VERSION 5.7 ;
  NOWIREEXTENSIONATPIN ON ;
  DIVIDERCHAR "/" ;
  BUSBITCHARS "[]" ;
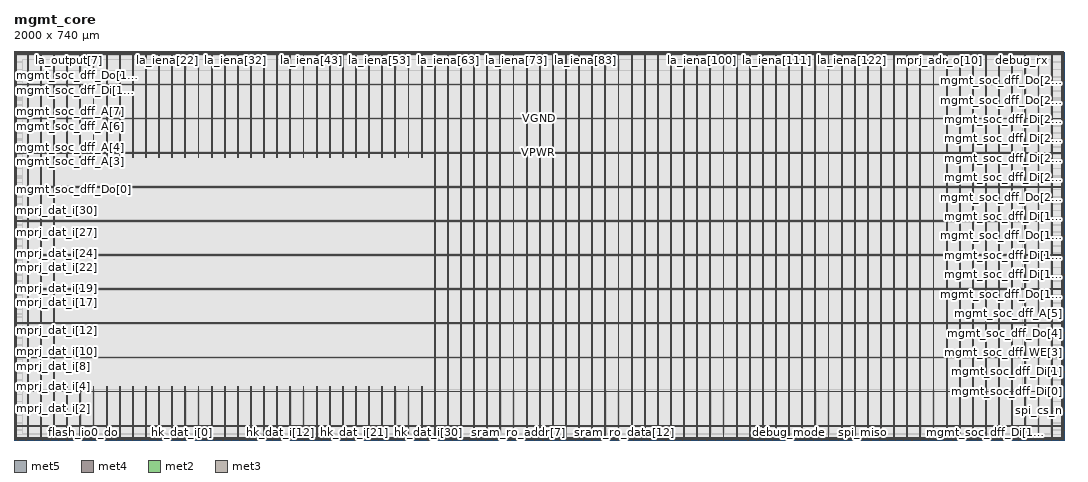
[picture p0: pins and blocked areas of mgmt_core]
MACRO mgmt_core
  CLASS BLOCK ;
  FOREIGN mgmt_core ;
  ORIGIN 0.000 0.000 ;
  SIZE 2000.000 BY 740.000 ;
  PIN VGND
    DIRECTION INPUT ;
    USE GROUND ;
    PORT
      LAYER met5 ;
        RECT 0.020 0.780 1999.600 2.380 ;
    END
    PORT
      LAYER met5 ;
        RECT 0.020 91.490 1999.600 93.090 ;
    END
    PORT
      LAYER met5 ;
        RECT 0.020 221.490 1999.600 223.090 ;
    END
    PORT
      LAYER met5 ;
        RECT 0.020 351.490 1999.600 353.090 ;
    END
    PORT
      LAYER met5 ;
        RECT 0.020 481.490 1999.600 483.090 ;
    END
    PORT
      LAYER met5 ;
        RECT 0.020 611.490 1999.600 613.090 ;
    END
    PORT
      LAYER met5 ;
        RECT 0.020 737.460 1999.600 739.060 ;
    END
    PORT
      LAYER met4 ;
        RECT 100.640 0.780 102.240 101.240 ;
    END
    PORT
      LAYER met4 ;
        RECT 150.640 0.780 152.240 101.240 ;
    END
    PORT
      LAYER met4 ;
        RECT 200.640 0.780 202.240 101.240 ;
    END
    PORT
      LAYER met4 ;
        RECT 250.640 0.780 252.240 101.240 ;
    END
    PORT
      LAYER met4 ;
        RECT 300.640 0.780 302.240 101.240 ;
    END
    PORT
      LAYER met4 ;
        RECT 350.640 0.780 352.240 101.240 ;
    END
    PORT
      LAYER met4 ;
        RECT 400.640 0.780 402.240 101.240 ;
    END
    PORT
      LAYER met4 ;
        RECT 450.640 0.780 452.240 101.240 ;
    END
    PORT
      LAYER met4 ;
        RECT 500.640 0.780 502.240 101.240 ;
    END
    PORT
      LAYER met4 ;
        RECT 550.640 0.780 552.240 101.240 ;
    END
    PORT
      LAYER met4 ;
        RECT 600.640 0.780 602.240 101.240 ;
    END
    PORT
      LAYER met4 ;
        RECT 650.640 0.780 652.240 101.240 ;
    END
    PORT
      LAYER met4 ;
        RECT 700.640 0.780 702.240 101.240 ;
    END
    PORT
      LAYER met4 ;
        RECT 750.640 0.780 752.240 101.240 ;
    END
    PORT
      LAYER met4 ;
        RECT 0.020 0.780 1.620 739.060 ;
    END
    PORT
      LAYER met4 ;
        RECT 50.640 0.780 52.240 739.060 ;
    END
    PORT
      LAYER met4 ;
        RECT 100.640 537.300 102.240 739.060 ;
    END
    PORT
      LAYER met4 ;
        RECT 150.640 537.300 152.240 739.060 ;
    END
    PORT
      LAYER met4 ;
        RECT 200.640 537.300 202.240 739.060 ;
    END
    PORT
      LAYER met4 ;
        RECT 250.640 537.300 252.240 739.060 ;
    END
    PORT
      LAYER met4 ;
        RECT 300.640 537.300 302.240 739.060 ;
    END
    PORT
      LAYER met4 ;
        RECT 350.640 537.300 352.240 739.060 ;
    END
    PORT
      LAYER met4 ;
        RECT 400.640 537.300 402.240 739.060 ;
    END
    PORT
      LAYER met4 ;
        RECT 450.640 537.300 452.240 739.060 ;
    END
    PORT
      LAYER met4 ;
        RECT 500.640 537.300 502.240 739.060 ;
    END
    PORT
      LAYER met4 ;
        RECT 550.640 537.300 552.240 739.060 ;
    END
    PORT
      LAYER met4 ;
        RECT 600.640 537.300 602.240 739.060 ;
    END
    PORT
      LAYER met4 ;
        RECT 650.640 537.300 652.240 739.060 ;
    END
    PORT
      LAYER met4 ;
        RECT 700.640 537.300 702.240 739.060 ;
    END
    PORT
      LAYER met4 ;
        RECT 750.640 537.300 752.240 739.060 ;
    END
    PORT
      LAYER met4 ;
        RECT 800.640 0.780 802.240 739.060 ;
    END
    PORT
      LAYER met4 ;
        RECT 850.640 0.780 852.240 739.060 ;
    END
    PORT
      LAYER met4 ;
        RECT 900.640 0.780 902.240 739.060 ;
    END
    PORT
      LAYER met4 ;
        RECT 950.640 0.780 952.240 739.060 ;
    END
    PORT
      LAYER met4 ;
        RECT 1000.640 0.780 1002.240 739.060 ;
    END
    PORT
      LAYER met4 ;
        RECT 1050.640 0.780 1052.240 739.060 ;
    END
    PORT
      LAYER met4 ;
        RECT 1100.640 0.780 1102.240 739.060 ;
    END
    PORT
      LAYER met4 ;
        RECT 1150.640 0.780 1152.240 739.060 ;
    END
    PORT
      LAYER met4 ;
        RECT 1200.640 0.780 1202.240 739.060 ;
    END
    PORT
      LAYER met4 ;
        RECT 1250.640 0.780 1252.240 739.060 ;
    END
    PORT
      LAYER met4 ;
        RECT 1300.640 0.780 1302.240 739.060 ;
    END
    PORT
      LAYER met4 ;
        RECT 1350.640 0.780 1352.240 739.060 ;
    END
    PORT
      LAYER met4 ;
        RECT 1400.640 0.780 1402.240 739.060 ;
    END
    PORT
      LAYER met4 ;
        RECT 1450.640 0.780 1452.240 739.060 ;
    END
    PORT
      LAYER met4 ;
        RECT 1500.640 0.780 1502.240 739.060 ;
    END
    PORT
      LAYER met4 ;
        RECT 1550.640 0.780 1552.240 739.060 ;
    END
    PORT
      LAYER met4 ;
        RECT 1600.640 0.780 1602.240 739.060 ;
    END
    PORT
      LAYER met4 ;
        RECT 1650.640 0.780 1652.240 739.060 ;
    END
    PORT
      LAYER met4 ;
        RECT 1700.640 0.780 1702.240 739.060 ;
    END
    PORT
      LAYER met4 ;
        RECT 1750.640 0.780 1752.240 739.060 ;
    END
    PORT
      LAYER met4 ;
        RECT 1800.640 0.780 1802.240 739.060 ;
    END
    PORT
      LAYER met4 ;
        RECT 1850.640 0.780 1852.240 739.060 ;
    END
    PORT
      LAYER met4 ;
        RECT 1900.640 0.780 1902.240 739.060 ;
    END
    PORT
      LAYER met4 ;
        RECT 1950.640 0.780 1952.240 739.060 ;
    END
    PORT
      LAYER met4 ;
        RECT 1998.000 0.780 1999.600 739.060 ;
    END
  END VGND
  PIN VPWR
    DIRECTION INPUT ;
    USE POWER ;
    PORT
      LAYER met5 ;
        RECT 3.320 4.080 1996.300 5.680 ;
    END
    PORT
      LAYER met5 ;
        RECT 0.020 26.490 1999.600 28.090 ;
    END
    PORT
      LAYER met5 ;
        RECT 0.020 156.490 1999.600 158.090 ;
    END
    PORT
      LAYER met5 ;
        RECT 0.020 286.490 1999.600 288.090 ;
    END
    PORT
      LAYER met5 ;
        RECT 0.020 416.490 1999.600 418.090 ;
    END
    PORT
      LAYER met5 ;
        RECT 0.020 546.490 1999.600 548.090 ;
    END
    PORT
      LAYER met5 ;
        RECT 0.020 676.490 1999.600 678.090 ;
    END
    PORT
      LAYER met5 ;
        RECT 3.320 734.160 1996.300 735.760 ;
    END
    PORT
      LAYER met4 ;
        RECT 125.640 0.780 127.240 101.240 ;
    END
    PORT
      LAYER met4 ;
        RECT 175.640 0.780 177.240 101.240 ;
    END
    PORT
      LAYER met4 ;
        RECT 225.640 0.780 227.240 101.240 ;
    END
    PORT
      LAYER met4 ;
        RECT 275.640 0.780 277.240 101.240 ;
    END
    PORT
      LAYER met4 ;
        RECT 325.640 0.780 327.240 101.240 ;
    END
    PORT
      LAYER met4 ;
        RECT 375.640 0.780 377.240 101.240 ;
    END
    PORT
      LAYER met4 ;
        RECT 425.640 0.780 427.240 101.240 ;
    END
    PORT
      LAYER met4 ;
        RECT 475.640 0.780 477.240 101.240 ;
    END
    PORT
      LAYER met4 ;
        RECT 525.640 0.780 527.240 101.240 ;
    END
    PORT
      LAYER met4 ;
        RECT 575.640 0.780 577.240 101.240 ;
    END
    PORT
      LAYER met4 ;
        RECT 625.640 0.780 627.240 101.240 ;
    END
    PORT
      LAYER met4 ;
        RECT 675.640 0.780 677.240 101.240 ;
    END
    PORT
      LAYER met4 ;
        RECT 725.640 0.780 727.240 101.240 ;
    END
    PORT
      LAYER met4 ;
        RECT 775.640 0.780 777.240 101.240 ;
    END
    PORT
      LAYER met4 ;
        RECT 3.320 4.080 4.920 735.760 ;
    END
    PORT
      LAYER met4 ;
        RECT 1994.700 4.080 1996.300 735.760 ;
    END
    PORT
      LAYER met4 ;
        RECT 25.640 0.780 27.240 739.060 ;
    END
    PORT
      LAYER met4 ;
        RECT 75.640 0.780 77.240 739.060 ;
    END
    PORT
      LAYER met4 ;
        RECT 125.640 537.300 127.240 739.060 ;
    END
    PORT
      LAYER met4 ;
        RECT 175.640 537.300 177.240 739.060 ;
    END
    PORT
      LAYER met4 ;
        RECT 225.640 537.300 227.240 739.060 ;
    END
    PORT
      LAYER met4 ;
        RECT 275.640 537.300 277.240 739.060 ;
    END
    PORT
      LAYER met4 ;
        RECT 325.640 537.300 327.240 739.060 ;
    END
    PORT
      LAYER met4 ;
        RECT 375.640 537.300 377.240 739.060 ;
    END
    PORT
      LAYER met4 ;
        RECT 425.640 537.300 427.240 739.060 ;
    END
    PORT
      LAYER met4 ;
        RECT 475.640 537.300 477.240 739.060 ;
    END
    PORT
      LAYER met4 ;
        RECT 525.640 537.300 527.240 739.060 ;
    END
    PORT
      LAYER met4 ;
        RECT 575.640 537.300 577.240 739.060 ;
    END
    PORT
      LAYER met4 ;
        RECT 625.640 537.300 627.240 739.060 ;
    END
    PORT
      LAYER met4 ;
        RECT 675.640 537.300 677.240 739.060 ;
    END
    PORT
      LAYER met4 ;
        RECT 725.640 537.300 727.240 739.060 ;
    END
    PORT
      LAYER met4 ;
        RECT 775.640 537.300 777.240 739.060 ;
    END
    PORT
      LAYER met4 ;
        RECT 825.640 0.780 827.240 739.060 ;
    END
    PORT
      LAYER met4 ;
        RECT 875.640 0.780 877.240 739.060 ;
    END
    PORT
      LAYER met4 ;
        RECT 925.640 0.780 927.240 739.060 ;
    END
    PORT
      LAYER met4 ;
        RECT 975.640 0.780 977.240 739.060 ;
    END
    PORT
      LAYER met4 ;
        RECT 1025.640 0.780 1027.240 739.060 ;
    END
    PORT
      LAYER met4 ;
        RECT 1075.640 0.780 1077.240 739.060 ;
    END
    PORT
      LAYER met4 ;
        RECT 1125.640 0.780 1127.240 739.060 ;
    END
    PORT
      LAYER met4 ;
        RECT 1175.640 0.780 1177.240 739.060 ;
    END
    PORT
      LAYER met4 ;
        RECT 1225.640 0.780 1227.240 739.060 ;
    END
    PORT
      LAYER met4 ;
        RECT 1275.640 0.780 1277.240 739.060 ;
    END
    PORT
      LAYER met4 ;
        RECT 1325.640 0.780 1327.240 739.060 ;
    END
    PORT
      LAYER met4 ;
        RECT 1375.640 0.780 1377.240 739.060 ;
    END
    PORT
      LAYER met4 ;
        RECT 1425.640 0.780 1427.240 739.060 ;
    END
    PORT
      LAYER met4 ;
        RECT 1475.640 0.780 1477.240 739.060 ;
    END
    PORT
      LAYER met4 ;
        RECT 1525.640 0.780 1527.240 739.060 ;
    END
    PORT
      LAYER met4 ;
        RECT 1575.640 0.780 1577.240 739.060 ;
    END
    PORT
      LAYER met4 ;
        RECT 1625.640 0.780 1627.240 739.060 ;
    END
    PORT
      LAYER met4 ;
        RECT 1675.640 0.780 1677.240 739.060 ;
    END
    PORT
      LAYER met4 ;
        RECT 1725.640 0.780 1727.240 739.060 ;
    END
    PORT
      LAYER met4 ;
        RECT 1775.640 0.780 1777.240 739.060 ;
    END
    PORT
      LAYER met4 ;
        RECT 1825.640 0.780 1827.240 739.060 ;
    END
    PORT
      LAYER met4 ;
        RECT 1875.640 0.780 1877.240 739.060 ;
    END
    PORT
      LAYER met4 ;
        RECT 1925.640 0.780 1927.240 739.060 ;
    END
    PORT
      LAYER met4 ;
        RECT 1975.640 0.780 1977.240 739.060 ;
    END
  END VPWR
  PIN core_clk
    DIRECTION INPUT ;
    USE SIGNAL ;
    PORT
      LAYER met2 ;
        RECT 1.470 736.000 1.750 740.000 ;
    END
  END core_clk
  PIN core_rst
    DIRECTION INPUT ;
    USE SIGNAL ;
    PORT
      LAYER met2 ;
        RECT 1569.610 0.000 1569.890 4.000 ;
    END
  END core_rst
  PIN debug_mode
    DIRECTION OUTPUT TRISTATE ;
    USE SIGNAL ;
    PORT
      LAYER met2 ;
        RECT 1476.230 0.000 1476.510 4.000 ;
    END
  END debug_mode
  PIN debug_oeb
    DIRECTION OUTPUT TRISTATE ;
    USE SIGNAL ;
    PORT
      LAYER met2 ;
        RECT 1491.870 0.000 1492.150 4.000 ;
    END
  END debug_oeb
  PIN debug_rx
    DIRECTION INPUT ;
    USE SIGNAL ;
    PORT
      LAYER met2 ;
        RECT 1919.670 736.000 1919.950 740.000 ;
    END
  END debug_rx
  PIN debug_tx
    DIRECTION OUTPUT TRISTATE ;
    USE SIGNAL ;
    PORT
      LAYER met2 ;
        RECT 1585.250 0.000 1585.530 4.000 ;
    END
  END debug_tx
  PIN flash_clk
    DIRECTION OUTPUT TRISTATE ;
    USE SIGNAL ;
    PORT
      LAYER met2 ;
        RECT 100.830 0.000 101.110 4.000 ;
    END
  END flash_clk
  PIN flash_cs_n
    DIRECTION OUTPUT TRISTATE ;
    USE SIGNAL ;
    PORT
      LAYER met2 ;
        RECT 1600.890 0.000 1601.170 4.000 ;
    END
  END flash_cs_n
  PIN flash_io0_di
    DIRECTION INPUT ;
    USE SIGNAL ;
    PORT
      LAYER met2 ;
        RECT 116.470 0.000 116.750 4.000 ;
    END
  END flash_io0_di
  PIN flash_io0_do
    DIRECTION OUTPUT TRISTATE ;
    USE SIGNAL ;
    PORT
      LAYER met2 ;
        RECT 132.110 0.000 132.390 4.000 ;
    END
  END flash_io0_do
  PIN flash_io0_oeb
    DIRECTION OUTPUT TRISTATE ;
    USE SIGNAL ;
    PORT
      LAYER met2 ;
        RECT 147.750 0.000 148.030 4.000 ;
    END
  END flash_io0_oeb
  PIN flash_io1_di
    DIRECTION INPUT ;
    USE SIGNAL ;
    PORT
      LAYER met2 ;
        RECT 163.390 0.000 163.670 4.000 ;
    END
  END flash_io1_di
  PIN flash_io1_do
    DIRECTION INPUT ;
    USE SIGNAL ;
    PORT
      LAYER met2 ;
        RECT 179.030 0.000 179.310 4.000 ;
    END
  END flash_io1_do
  PIN flash_io1_oeb
    DIRECTION INPUT ;
    USE SIGNAL ;
    PORT
      LAYER met2 ;
        RECT 194.670 0.000 194.950 4.000 ;
    END
  END flash_io1_oeb
  PIN flash_io2_di
    DIRECTION INPUT ;
    USE SIGNAL ;
    PORT
      LAYER met2 ;
        RECT 210.310 0.000 210.590 4.000 ;
    END
  END flash_io2_di
  PIN flash_io2_do
    DIRECTION INPUT ;
    USE SIGNAL ;
    PORT
      LAYER met2 ;
        RECT 225.950 0.000 226.230 4.000 ;
    END
  END flash_io2_do
  PIN flash_io2_oeb
    DIRECTION INPUT ;
    USE SIGNAL ;
    PORT
      LAYER met3 ;
        RECT 0.000 19.080 4.000 19.680 ;
    END
  END flash_io2_oeb
  PIN flash_io3_di
    DIRECTION INPUT ;
    USE SIGNAL ;
    PORT
      LAYER met2 ;
        RECT 241.590 0.000 241.870 4.000 ;
    END
  END flash_io3_di
  PIN flash_io3_do
    DIRECTION INPUT ;
    USE SIGNAL ;
    PORT
      LAYER met2 ;
        RECT 257.230 0.000 257.510 4.000 ;
    END
  END flash_io3_do
  PIN flash_io3_oeb
    DIRECTION INPUT ;
    USE SIGNAL ;
    PORT
      LAYER met3 ;
        RECT 0.000 6.160 4.000 6.760 ;
    END
  END flash_io3_oeb
  PIN gpio_in_pad
    DIRECTION INPUT ;
    USE SIGNAL ;
    PORT
      LAYER met2 ;
        RECT 7.450 0.000 7.730 4.000 ;
    END
  END gpio_in_pad
  PIN gpio_inenb_pad
    DIRECTION OUTPUT TRISTATE ;
    USE SIGNAL ;
    PORT
      LAYER met2 ;
        RECT 22.630 0.000 22.910 4.000 ;
    END
  END gpio_inenb_pad
  PIN gpio_mode0_pad
    DIRECTION OUTPUT TRISTATE ;
    USE SIGNAL ;
    PORT
      LAYER met2 ;
        RECT 38.270 0.000 38.550 4.000 ;
    END
  END gpio_mode0_pad
  PIN gpio_mode1_pad
    DIRECTION OUTPUT TRISTATE ;
    USE SIGNAL ;
    PORT
      LAYER met2 ;
        RECT 53.910 0.000 54.190 4.000 ;
    END
  END gpio_mode1_pad
  PIN gpio_out_pad
    DIRECTION OUTPUT TRISTATE ;
    USE SIGNAL ;
    PORT
      LAYER met2 ;
        RECT 69.550 0.000 69.830 4.000 ;
    END
  END gpio_out_pad
  PIN gpio_outenb_pad
    DIRECTION OUTPUT TRISTATE ;
    USE SIGNAL ;
    PORT
      LAYER met2 ;
        RECT 85.190 0.000 85.470 4.000 ;
    END
  END gpio_outenb_pad
  PIN hk_ack_i
    DIRECTION INPUT ;
    USE SIGNAL ;
    PORT
      LAYER met2 ;
        RECT 288.510 0.000 288.790 4.000 ;
    END
  END hk_ack_i
  PIN hk_dat_i[0]
    DIRECTION INPUT ;
    USE SIGNAL ;
    PORT
      LAYER met2 ;
        RECT 319.790 0.000 320.070 4.000 ;
    END
  END hk_dat_i[0]
  PIN hk_dat_i[10]
    DIRECTION INPUT ;
    USE SIGNAL ;
    PORT
      LAYER met2 ;
        RECT 476.190 0.000 476.470 4.000 ;
    END
  END hk_dat_i[10]
  PIN hk_dat_i[11]
    DIRECTION INPUT ;
    USE SIGNAL ;
    PORT
      LAYER met2 ;
        RECT 491.830 0.000 492.110 4.000 ;
    END
  END hk_dat_i[11]
  PIN hk_dat_i[12]
    DIRECTION INPUT ;
    USE SIGNAL ;
    PORT
      LAYER met2 ;
        RECT 507.470 0.000 507.750 4.000 ;
    END
  END hk_dat_i[12]
  PIN hk_dat_i[13]
    DIRECTION INPUT ;
    USE SIGNAL ;
    PORT
      LAYER met2 ;
        RECT 522.650 0.000 522.930 4.000 ;
    END
  END hk_dat_i[13]
  PIN hk_dat_i[14]
    DIRECTION INPUT ;
    USE SIGNAL ;
    PORT
      LAYER met2 ;
        RECT 538.290 0.000 538.570 4.000 ;
    END
  END hk_dat_i[14]
  PIN hk_dat_i[15]
    DIRECTION INPUT ;
    USE SIGNAL ;
    PORT
      LAYER met2 ;
        RECT 553.930 0.000 554.210 4.000 ;
    END
  END hk_dat_i[15]
  PIN hk_dat_i[16]
    DIRECTION INPUT ;
    USE SIGNAL ;
    PORT
      LAYER met2 ;
        RECT 569.570 0.000 569.850 4.000 ;
    END
  END hk_dat_i[16]
  PIN hk_dat_i[17]
    DIRECTION INPUT ;
    USE SIGNAL ;
    PORT
      LAYER met2 ;
        RECT 585.210 0.000 585.490 4.000 ;
    END
  END hk_dat_i[17]
  PIN hk_dat_i[18]
    DIRECTION INPUT ;
    USE SIGNAL ;
    PORT
      LAYER met2 ;
        RECT 600.850 0.000 601.130 4.000 ;
    END
  END hk_dat_i[18]
  PIN hk_dat_i[19]
    DIRECTION INPUT ;
    USE SIGNAL ;
    PORT
      LAYER met2 ;
        RECT 616.490 0.000 616.770 4.000 ;
    END
  END hk_dat_i[19]
  PIN hk_dat_i[1]
    DIRECTION INPUT ;
    USE SIGNAL ;
    PORT
      LAYER met2 ;
        RECT 335.430 0.000 335.710 4.000 ;
    END
  END hk_dat_i[1]
  PIN hk_dat_i[20]
    DIRECTION INPUT ;
    USE SIGNAL ;
    PORT
      LAYER met2 ;
        RECT 632.130 0.000 632.410 4.000 ;
    END
  END hk_dat_i[20]
  PIN hk_dat_i[21]
    DIRECTION INPUT ;
    USE SIGNAL ;
    PORT
      LAYER met2 ;
        RECT 647.770 0.000 648.050 4.000 ;
    END
  END hk_dat_i[21]
  PIN hk_dat_i[22]
    DIRECTION INPUT ;
    USE SIGNAL ;
    PORT
      LAYER met2 ;
        RECT 663.410 0.000 663.690 4.000 ;
    END
  END hk_dat_i[22]
  PIN hk_dat_i[23]
    DIRECTION INPUT ;
    USE SIGNAL ;
    PORT
      LAYER met2 ;
        RECT 679.050 0.000 679.330 4.000 ;
    END
  END hk_dat_i[23]
  PIN hk_dat_i[24]
    DIRECTION INPUT ;
    USE SIGNAL ;
    PORT
      LAYER met2 ;
        RECT 694.690 0.000 694.970 4.000 ;
    END
  END hk_dat_i[24]
  PIN hk_dat_i[25]
    DIRECTION INPUT ;
    USE SIGNAL ;
    PORT
      LAYER met2 ;
        RECT 710.330 0.000 710.610 4.000 ;
    END
  END hk_dat_i[25]
  PIN hk_dat_i[26]
    DIRECTION INPUT ;
    USE SIGNAL ;
    PORT
      LAYER met2 ;
        RECT 725.970 0.000 726.250 4.000 ;
    END
  END hk_dat_i[26]
  PIN hk_dat_i[27]
    DIRECTION INPUT ;
    USE SIGNAL ;
    PORT
      LAYER met2 ;
        RECT 741.610 0.000 741.890 4.000 ;
    END
  END hk_dat_i[27]
  PIN hk_dat_i[28]
    DIRECTION INPUT ;
    USE SIGNAL ;
    PORT
      LAYER met2 ;
        RECT 757.250 0.000 757.530 4.000 ;
    END
  END hk_dat_i[28]
  PIN hk_dat_i[29]
    DIRECTION INPUT ;
    USE SIGNAL ;
    PORT
      LAYER met2 ;
        RECT 772.890 0.000 773.170 4.000 ;
    END
  END hk_dat_i[29]
  PIN hk_dat_i[2]
    DIRECTION INPUT ;
    USE SIGNAL ;
    PORT
      LAYER met2 ;
        RECT 351.070 0.000 351.350 4.000 ;
    END
  END hk_dat_i[2]
  PIN hk_dat_i[30]
    DIRECTION INPUT ;
    USE SIGNAL ;
    PORT
      LAYER met2 ;
        RECT 788.530 0.000 788.810 4.000 ;
    END
  END hk_dat_i[30]
  PIN hk_dat_i[31]
    DIRECTION INPUT ;
    USE SIGNAL ;
    PORT
      LAYER met2 ;
        RECT 804.170 0.000 804.450 4.000 ;
    END
  END hk_dat_i[31]
  PIN hk_dat_i[3]
    DIRECTION INPUT ;
    USE SIGNAL ;
    PORT
      LAYER met2 ;
        RECT 366.710 0.000 366.990 4.000 ;
    END
  END hk_dat_i[3]
  PIN hk_dat_i[4]
    DIRECTION INPUT ;
    USE SIGNAL ;
    PORT
      LAYER met2 ;
        RECT 382.350 0.000 382.630 4.000 ;
    END
  END hk_dat_i[4]
  PIN hk_dat_i[5]
    DIRECTION INPUT ;
    USE SIGNAL ;
    PORT
      LAYER met2 ;
        RECT 397.990 0.000 398.270 4.000 ;
    END
  END hk_dat_i[5]
  PIN hk_dat_i[6]
    DIRECTION INPUT ;
    USE SIGNAL ;
    PORT
      LAYER met2 ;
        RECT 413.630 0.000 413.910 4.000 ;
    END
  END hk_dat_i[6]
  PIN hk_dat_i[7]
    DIRECTION INPUT ;
    USE SIGNAL ;
    PORT
      LAYER met2 ;
        RECT 429.270 0.000 429.550 4.000 ;
    END
  END hk_dat_i[7]
  PIN hk_dat_i[8]
    DIRECTION INPUT ;
    USE SIGNAL ;
    PORT
      LAYER met2 ;
        RECT 444.910 0.000 445.190 4.000 ;
    END
  END hk_dat_i[8]
  PIN hk_dat_i[9]
    DIRECTION INPUT ;
    USE SIGNAL ;
    PORT
      LAYER met2 ;
        RECT 460.550 0.000 460.830 4.000 ;
    END
  END hk_dat_i[9]
  PIN hk_stb_o
    DIRECTION OUTPUT TRISTATE ;
    USE SIGNAL ;
    PORT
      LAYER met2 ;
        RECT 304.150 0.000 304.430 4.000 ;
    END
  END hk_stb_o
  PIN la_iena[0]
    DIRECTION OUTPUT TRISTATE ;
    USE SIGNAL ;
    PORT
      LAYER met2 ;
        RECT 4.690 736.000 4.970 740.000 ;
    END
  END la_iena[0]
  PIN la_iena[100]
    DIRECTION OUTPUT TRISTATE ;
    USE SIGNAL ;
    PORT
      LAYER met2 ;
        RECT 1309.710 736.000 1309.990 740.000 ;
    END
  END la_iena[100]
  PIN la_iena[101]
    DIRECTION OUTPUT TRISTATE ;
    USE SIGNAL ;
    PORT
      LAYER met2 ;
        RECT 1322.590 736.000 1322.870 740.000 ;
    END
  END la_iena[101]
  PIN la_iena[102]
    DIRECTION OUTPUT TRISTATE ;
    USE SIGNAL ;
    PORT
      LAYER met2 ;
        RECT 1335.930 736.000 1336.210 740.000 ;
    END
  END la_iena[102]
  PIN la_iena[103]
    DIRECTION OUTPUT TRISTATE ;
    USE SIGNAL ;
    PORT
      LAYER met2 ;
        RECT 1348.810 736.000 1349.090 740.000 ;
    END
  END la_iena[103]
  PIN la_iena[104]
    DIRECTION OUTPUT TRISTATE ;
    USE SIGNAL ;
    PORT
      LAYER met2 ;
        RECT 1361.690 736.000 1361.970 740.000 ;
    END
  END la_iena[104]
  PIN la_iena[105]
    DIRECTION OUTPUT TRISTATE ;
    USE SIGNAL ;
    PORT
      LAYER met2 ;
        RECT 1375.030 736.000 1375.310 740.000 ;
    END
  END la_iena[105]
  PIN la_iena[106]
    DIRECTION OUTPUT TRISTATE ;
    USE SIGNAL ;
    PORT
      LAYER met2 ;
        RECT 1387.910 736.000 1388.190 740.000 ;
    END
  END la_iena[106]
  PIN la_iena[107]
    DIRECTION OUTPUT TRISTATE ;
    USE SIGNAL ;
    PORT
      LAYER met2 ;
        RECT 1400.790 736.000 1401.070 740.000 ;
    END
  END la_iena[107]
  PIN la_iena[108]
    DIRECTION OUTPUT TRISTATE ;
    USE SIGNAL ;
    PORT
      LAYER met2 ;
        RECT 1414.130 736.000 1414.410 740.000 ;
    END
  END la_iena[108]
  PIN la_iena[109]
    DIRECTION OUTPUT TRISTATE ;
    USE SIGNAL ;
    PORT
      LAYER met2 ;
        RECT 1427.010 736.000 1427.290 740.000 ;
    END
  END la_iena[109]
  PIN la_iena[10]
    DIRECTION OUTPUT TRISTATE ;
    USE SIGNAL ;
    PORT
      LAYER met2 ;
        RECT 134.870 736.000 135.150 740.000 ;
    END
  END la_iena[10]
  PIN la_iena[110]
    DIRECTION OUTPUT TRISTATE ;
    USE SIGNAL ;
    PORT
      LAYER met2 ;
        RECT 1440.350 736.000 1440.630 740.000 ;
    END
  END la_iena[110]
  PIN la_iena[111]
    DIRECTION OUTPUT TRISTATE ;
    USE SIGNAL ;
    PORT
      LAYER met2 ;
        RECT 1453.230 736.000 1453.510 740.000 ;
    END
  END la_iena[111]
  PIN la_iena[112]
    DIRECTION OUTPUT TRISTATE ;
    USE SIGNAL ;
    PORT
      LAYER met2 ;
        RECT 1466.110 736.000 1466.390 740.000 ;
    END
  END la_iena[112]
  PIN la_iena[113]
    DIRECTION OUTPUT TRISTATE ;
    USE SIGNAL ;
    PORT
      LAYER met2 ;
        RECT 1479.450 736.000 1479.730 740.000 ;
    END
  END la_iena[113]
  PIN la_iena[114]
    DIRECTION OUTPUT TRISTATE ;
    USE SIGNAL ;
    PORT
      LAYER met2 ;
        RECT 1492.330 736.000 1492.610 740.000 ;
    END
  END la_iena[114]
  PIN la_iena[115]
    DIRECTION OUTPUT TRISTATE ;
    USE SIGNAL ;
    PORT
      LAYER met2 ;
        RECT 1505.210 736.000 1505.490 740.000 ;
    END
  END la_iena[115]
  PIN la_iena[116]
    DIRECTION OUTPUT TRISTATE ;
    USE SIGNAL ;
    PORT
      LAYER met2 ;
        RECT 1518.550 736.000 1518.830 740.000 ;
    END
  END la_iena[116]
  PIN la_iena[117]
    DIRECTION OUTPUT TRISTATE ;
    USE SIGNAL ;
    PORT
      LAYER met2 ;
        RECT 1531.430 736.000 1531.710 740.000 ;
    END
  END la_iena[117]
  PIN la_iena[118]
    DIRECTION OUTPUT TRISTATE ;
    USE SIGNAL ;
    PORT
      LAYER met2 ;
        RECT 1544.310 736.000 1544.590 740.000 ;
    END
  END la_iena[118]
  PIN la_iena[119]
    DIRECTION OUTPUT TRISTATE ;
    USE SIGNAL ;
    PORT
      LAYER met2 ;
        RECT 1557.650 736.000 1557.930 740.000 ;
    END
  END la_iena[119]
  PIN la_iena[11]
    DIRECTION OUTPUT TRISTATE ;
    USE SIGNAL ;
    PORT
      LAYER met2 ;
        RECT 148.210 736.000 148.490 740.000 ;
    END
  END la_iena[11]
  PIN la_iena[120]
    DIRECTION OUTPUT TRISTATE ;
    USE SIGNAL ;
    PORT
      LAYER met2 ;
        RECT 1570.530 736.000 1570.810 740.000 ;
    END
  END la_iena[120]
  PIN la_iena[121]
    DIRECTION OUTPUT TRISTATE ;
    USE SIGNAL ;
    PORT
      LAYER met2 ;
        RECT 1583.870 736.000 1584.150 740.000 ;
    END
  END la_iena[121]
  PIN la_iena[122]
    DIRECTION OUTPUT TRISTATE ;
    USE SIGNAL ;
    PORT
      LAYER met2 ;
        RECT 1596.750 736.000 1597.030 740.000 ;
    END
  END la_iena[122]
  PIN la_iena[123]
    DIRECTION OUTPUT TRISTATE ;
    USE SIGNAL ;
    PORT
      LAYER met2 ;
        RECT 1609.630 736.000 1609.910 740.000 ;
    END
  END la_iena[123]
  PIN la_iena[124]
    DIRECTION OUTPUT TRISTATE ;
    USE SIGNAL ;
    PORT
      LAYER met2 ;
        RECT 1622.970 736.000 1623.250 740.000 ;
    END
  END la_iena[124]
  PIN la_iena[125]
    DIRECTION OUTPUT TRISTATE ;
    USE SIGNAL ;
    PORT
      LAYER met2 ;
        RECT 1635.850 736.000 1636.130 740.000 ;
    END
  END la_iena[125]
  PIN la_iena[126]
    DIRECTION OUTPUT TRISTATE ;
    USE SIGNAL ;
    PORT
      LAYER met2 ;
        RECT 1648.730 736.000 1649.010 740.000 ;
    END
  END la_iena[126]
  PIN la_iena[127]
    DIRECTION OUTPUT TRISTATE ;
    USE SIGNAL ;
    PORT
      LAYER met2 ;
        RECT 1662.070 736.000 1662.350 740.000 ;
    END
  END la_iena[127]
  PIN la_iena[12]
    DIRECTION OUTPUT TRISTATE ;
    USE SIGNAL ;
    PORT
      LAYER met2 ;
        RECT 161.090 736.000 161.370 740.000 ;
    END
  END la_iena[12]
  PIN la_iena[13]
    DIRECTION OUTPUT TRISTATE ;
    USE SIGNAL ;
    PORT
      LAYER met2 ;
        RECT 173.970 736.000 174.250 740.000 ;
    END
  END la_iena[13]
  PIN la_iena[14]
    DIRECTION OUTPUT TRISTATE ;
    USE SIGNAL ;
    PORT
      LAYER met2 ;
        RECT 187.310 736.000 187.590 740.000 ;
    END
  END la_iena[14]
  PIN la_iena[15]
    DIRECTION OUTPUT TRISTATE ;
    USE SIGNAL ;
    PORT
      LAYER met2 ;
        RECT 200.190 736.000 200.470 740.000 ;
    END
  END la_iena[15]
  PIN la_iena[16]
    DIRECTION OUTPUT TRISTATE ;
    USE SIGNAL ;
    PORT
      LAYER met2 ;
        RECT 213.530 736.000 213.810 740.000 ;
    END
  END la_iena[16]
  PIN la_iena[17]
    DIRECTION OUTPUT TRISTATE ;
    USE SIGNAL ;
    PORT
      LAYER met2 ;
        RECT 226.410 736.000 226.690 740.000 ;
    END
  END la_iena[17]
  PIN la_iena[18]
    DIRECTION OUTPUT TRISTATE ;
    USE SIGNAL ;
    PORT
      LAYER met2 ;
        RECT 239.290 736.000 239.570 740.000 ;
    END
  END la_iena[18]
  PIN la_iena[19]
    DIRECTION OUTPUT TRISTATE ;
    USE SIGNAL ;
    PORT
      LAYER met2 ;
        RECT 252.630 736.000 252.910 740.000 ;
    END
  END la_iena[19]
  PIN la_iena[1]
    DIRECTION OUTPUT TRISTATE ;
    USE SIGNAL ;
    PORT
      LAYER met2 ;
        RECT 17.570 736.000 17.850 740.000 ;
    END
  END la_iena[1]
  PIN la_iena[20]
    DIRECTION OUTPUT TRISTATE ;
    USE SIGNAL ;
    PORT
      LAYER met2 ;
        RECT 265.510 736.000 265.790 740.000 ;
    END
  END la_iena[20]
  PIN la_iena[21]
    DIRECTION OUTPUT TRISTATE ;
    USE SIGNAL ;
    PORT
      LAYER met2 ;
        RECT 278.390 736.000 278.670 740.000 ;
    END
  END la_iena[21]
  PIN la_iena[22]
    DIRECTION OUTPUT TRISTATE ;
    USE SIGNAL ;
    PORT
      LAYER met2 ;
        RECT 291.730 736.000 292.010 740.000 ;
    END
  END la_iena[22]
  PIN la_iena[23]
    DIRECTION OUTPUT TRISTATE ;
    USE SIGNAL ;
    PORT
      LAYER met2 ;
        RECT 304.610 736.000 304.890 740.000 ;
    END
  END la_iena[23]
  PIN la_iena[24]
    DIRECTION OUTPUT TRISTATE ;
    USE SIGNAL ;
    PORT
      LAYER met2 ;
        RECT 317.950 736.000 318.230 740.000 ;
    END
  END la_iena[24]
  PIN la_iena[25]
    DIRECTION OUTPUT TRISTATE ;
    USE SIGNAL ;
    PORT
      LAYER met2 ;
        RECT 330.830 736.000 331.110 740.000 ;
    END
  END la_iena[25]
  PIN la_iena[26]
    DIRECTION OUTPUT TRISTATE ;
    USE SIGNAL ;
    PORT
      LAYER met2 ;
        RECT 343.710 736.000 343.990 740.000 ;
    END
  END la_iena[26]
  PIN la_iena[27]
    DIRECTION OUTPUT TRISTATE ;
    USE SIGNAL ;
    PORT
      LAYER met2 ;
        RECT 357.050 736.000 357.330 740.000 ;
    END
  END la_iena[27]
  PIN la_iena[28]
    DIRECTION OUTPUT TRISTATE ;
    USE SIGNAL ;
    PORT
      LAYER met2 ;
        RECT 369.930 736.000 370.210 740.000 ;
    END
  END la_iena[28]
  PIN la_iena[29]
    DIRECTION OUTPUT TRISTATE ;
    USE SIGNAL ;
    PORT
      LAYER met2 ;
        RECT 382.810 736.000 383.090 740.000 ;
    END
  END la_iena[29]
  PIN la_iena[2]
    DIRECTION OUTPUT TRISTATE ;
    USE SIGNAL ;
    PORT
      LAYER met2 ;
        RECT 30.450 736.000 30.730 740.000 ;
    END
  END la_iena[2]
  PIN la_iena[30]
    DIRECTION OUTPUT TRISTATE ;
    USE SIGNAL ;
    PORT
      LAYER met2 ;
        RECT 396.150 736.000 396.430 740.000 ;
    END
  END la_iena[30]
  PIN la_iena[31]
    DIRECTION OUTPUT TRISTATE ;
    USE SIGNAL ;
    PORT
      LAYER met2 ;
        RECT 409.030 736.000 409.310 740.000 ;
    END
  END la_iena[31]
  PIN la_iena[32]
    DIRECTION OUTPUT TRISTATE ;
    USE SIGNAL ;
    PORT
      LAYER met2 ;
        RECT 421.910 736.000 422.190 740.000 ;
    END
  END la_iena[32]
  PIN la_iena[33]
    DIRECTION OUTPUT TRISTATE ;
    USE SIGNAL ;
    PORT
      LAYER met2 ;
        RECT 435.250 736.000 435.530 740.000 ;
    END
  END la_iena[33]
  PIN la_iena[34]
    DIRECTION OUTPUT TRISTATE ;
    USE SIGNAL ;
    PORT
      LAYER met2 ;
        RECT 448.130 736.000 448.410 740.000 ;
    END
  END la_iena[34]
  PIN la_iena[35]
    DIRECTION OUTPUT TRISTATE ;
    USE SIGNAL ;
    PORT
      LAYER met2 ;
        RECT 461.470 736.000 461.750 740.000 ;
    END
  END la_iena[35]
  PIN la_iena[36]
    DIRECTION OUTPUT TRISTATE ;
    USE SIGNAL ;
    PORT
      LAYER met2 ;
        RECT 474.350 736.000 474.630 740.000 ;
    END
  END la_iena[36]
  PIN la_iena[37]
    DIRECTION OUTPUT TRISTATE ;
    USE SIGNAL ;
    PORT
      LAYER met2 ;
        RECT 487.230 736.000 487.510 740.000 ;
    END
  END la_iena[37]
  PIN la_iena[38]
    DIRECTION OUTPUT TRISTATE ;
    USE SIGNAL ;
    PORT
      LAYER met2 ;
        RECT 500.570 736.000 500.850 740.000 ;
    END
  END la_iena[38]
  PIN la_iena[39]
    DIRECTION OUTPUT TRISTATE ;
    USE SIGNAL ;
    PORT
      LAYER met2 ;
        RECT 513.450 736.000 513.730 740.000 ;
    END
  END la_iena[39]
  PIN la_iena[3]
    DIRECTION OUTPUT TRISTATE ;
    USE SIGNAL ;
    PORT
      LAYER met2 ;
        RECT 43.790 736.000 44.070 740.000 ;
    END
  END la_iena[3]
  PIN la_iena[40]
    DIRECTION OUTPUT TRISTATE ;
    USE SIGNAL ;
    PORT
      LAYER met2 ;
        RECT 526.330 736.000 526.610 740.000 ;
    END
  END la_iena[40]
  PIN la_iena[41]
    DIRECTION OUTPUT TRISTATE ;
    USE SIGNAL ;
    PORT
      LAYER met2 ;
        RECT 539.670 736.000 539.950 740.000 ;
    END
  END la_iena[41]
  PIN la_iena[42]
    DIRECTION OUTPUT TRISTATE ;
    USE SIGNAL ;
    PORT
      LAYER met2 ;
        RECT 552.550 736.000 552.830 740.000 ;
    END
  END la_iena[42]
  PIN la_iena[43]
    DIRECTION OUTPUT TRISTATE ;
    USE SIGNAL ;
    PORT
      LAYER met2 ;
        RECT 565.890 736.000 566.170 740.000 ;
    END
  END la_iena[43]
  PIN la_iena[44]
    DIRECTION OUTPUT TRISTATE ;
    USE SIGNAL ;
    PORT
      LAYER met2 ;
        RECT 578.770 736.000 579.050 740.000 ;
    END
  END la_iena[44]
  PIN la_iena[45]
    DIRECTION OUTPUT TRISTATE ;
    USE SIGNAL ;
    PORT
      LAYER met2 ;
        RECT 591.650 736.000 591.930 740.000 ;
    END
  END la_iena[45]
  PIN la_iena[46]
    DIRECTION OUTPUT TRISTATE ;
    USE SIGNAL ;
    PORT
      LAYER met2 ;
        RECT 604.990 736.000 605.270 740.000 ;
    END
  END la_iena[46]
  PIN la_iena[47]
    DIRECTION OUTPUT TRISTATE ;
    USE SIGNAL ;
    PORT
      LAYER met2 ;
        RECT 617.870 736.000 618.150 740.000 ;
    END
  END la_iena[47]
  PIN la_iena[48]
    DIRECTION OUTPUT TRISTATE ;
    USE SIGNAL ;
    PORT
      LAYER met2 ;
        RECT 630.750 736.000 631.030 740.000 ;
    END
  END la_iena[48]
  PIN la_iena[49]
    DIRECTION OUTPUT TRISTATE ;
    USE SIGNAL ;
    PORT
      LAYER met2 ;
        RECT 644.090 736.000 644.370 740.000 ;
    END
  END la_iena[49]
  PIN la_iena[4]
    DIRECTION OUTPUT TRISTATE ;
    USE SIGNAL ;
    PORT
      LAYER met2 ;
        RECT 56.670 736.000 56.950 740.000 ;
    END
  END la_iena[4]
  PIN la_iena[50]
    DIRECTION OUTPUT TRISTATE ;
    USE SIGNAL ;
    PORT
      LAYER met2 ;
        RECT 656.970 736.000 657.250 740.000 ;
    END
  END la_iena[50]
  PIN la_iena[51]
    DIRECTION OUTPUT TRISTATE ;
    USE SIGNAL ;
    PORT
      LAYER met2 ;
        RECT 670.310 736.000 670.590 740.000 ;
    END
  END la_iena[51]
  PIN la_iena[52]
    DIRECTION OUTPUT TRISTATE ;
    USE SIGNAL ;
    PORT
      LAYER met2 ;
        RECT 683.190 736.000 683.470 740.000 ;
    END
  END la_iena[52]
  PIN la_iena[53]
    DIRECTION OUTPUT TRISTATE ;
    USE SIGNAL ;
    PORT
      LAYER met2 ;
        RECT 696.070 736.000 696.350 740.000 ;
    END
  END la_iena[53]
  PIN la_iena[54]
    DIRECTION OUTPUT TRISTATE ;
    USE SIGNAL ;
    PORT
      LAYER met2 ;
        RECT 709.410 736.000 709.690 740.000 ;
    END
  END la_iena[54]
  PIN la_iena[55]
    DIRECTION OUTPUT TRISTATE ;
    USE SIGNAL ;
    PORT
      LAYER met2 ;
        RECT 722.290 736.000 722.570 740.000 ;
    END
  END la_iena[55]
  PIN la_iena[56]
    DIRECTION OUTPUT TRISTATE ;
    USE SIGNAL ;
    PORT
      LAYER met2 ;
        RECT 735.170 736.000 735.450 740.000 ;
    END
  END la_iena[56]
  PIN la_iena[57]
    DIRECTION OUTPUT TRISTATE ;
    USE SIGNAL ;
    PORT
      LAYER met2 ;
        RECT 748.510 736.000 748.790 740.000 ;
    END
  END la_iena[57]
  PIN la_iena[58]
    DIRECTION OUTPUT TRISTATE ;
    USE SIGNAL ;
    PORT
      LAYER met2 ;
        RECT 761.390 736.000 761.670 740.000 ;
    END
  END la_iena[58]
  PIN la_iena[59]
    DIRECTION OUTPUT TRISTATE ;
    USE SIGNAL ;
    PORT
      LAYER met2 ;
        RECT 774.730 736.000 775.010 740.000 ;
    END
  END la_iena[59]
  PIN la_iena[5]
    DIRECTION OUTPUT TRISTATE ;
    USE SIGNAL ;
    PORT
      LAYER met2 ;
        RECT 69.550 736.000 69.830 740.000 ;
    END
  END la_iena[5]
  PIN la_iena[60]
    DIRECTION OUTPUT TRISTATE ;
    USE SIGNAL ;
    PORT
      LAYER met2 ;
        RECT 787.610 736.000 787.890 740.000 ;
    END
  END la_iena[60]
  PIN la_iena[61]
    DIRECTION OUTPUT TRISTATE ;
    USE SIGNAL ;
    PORT
      LAYER met2 ;
        RECT 800.490 736.000 800.770 740.000 ;
    END
  END la_iena[61]
  PIN la_iena[62]
    DIRECTION OUTPUT TRISTATE ;
    USE SIGNAL ;
    PORT
      LAYER met2 ;
        RECT 813.830 736.000 814.110 740.000 ;
    END
  END la_iena[62]
  PIN la_iena[63]
    DIRECTION OUTPUT TRISTATE ;
    USE SIGNAL ;
    PORT
      LAYER met2 ;
        RECT 826.710 736.000 826.990 740.000 ;
    END
  END la_iena[63]
  PIN la_iena[64]
    DIRECTION OUTPUT TRISTATE ;
    USE SIGNAL ;
    PORT
      LAYER met2 ;
        RECT 839.590 736.000 839.870 740.000 ;
    END
  END la_iena[64]
  PIN la_iena[65]
    DIRECTION OUTPUT TRISTATE ;
    USE SIGNAL ;
    PORT
      LAYER met2 ;
        RECT 852.930 736.000 853.210 740.000 ;
    END
  END la_iena[65]
  PIN la_iena[66]
    DIRECTION OUTPUT TRISTATE ;
    USE SIGNAL ;
    PORT
      LAYER met2 ;
        RECT 865.810 736.000 866.090 740.000 ;
    END
  END la_iena[66]
  PIN la_iena[67]
    DIRECTION OUTPUT TRISTATE ;
    USE SIGNAL ;
    PORT
      LAYER met2 ;
        RECT 879.150 736.000 879.430 740.000 ;
    END
  END la_iena[67]
  PIN la_iena[68]
    DIRECTION OUTPUT TRISTATE ;
    USE SIGNAL ;
    PORT
      LAYER met2 ;
        RECT 892.030 736.000 892.310 740.000 ;
    END
  END la_iena[68]
  PIN la_iena[69]
    DIRECTION OUTPUT TRISTATE ;
    USE SIGNAL ;
    PORT
      LAYER met2 ;
        RECT 904.910 736.000 905.190 740.000 ;
    END
  END la_iena[69]
  PIN la_iena[6]
    DIRECTION OUTPUT TRISTATE ;
    USE SIGNAL ;
    PORT
      LAYER met2 ;
        RECT 82.890 736.000 83.170 740.000 ;
    END
  END la_iena[6]
  PIN la_iena[70]
    DIRECTION OUTPUT TRISTATE ;
    USE SIGNAL ;
    PORT
      LAYER met2 ;
        RECT 918.250 736.000 918.530 740.000 ;
    END
  END la_iena[70]
  PIN la_iena[71]
    DIRECTION OUTPUT TRISTATE ;
    USE SIGNAL ;
    PORT
      LAYER met2 ;
        RECT 931.130 736.000 931.410 740.000 ;
    END
  END la_iena[71]
  PIN la_iena[72]
    DIRECTION OUTPUT TRISTATE ;
    USE SIGNAL ;
    PORT
      LAYER met2 ;
        RECT 944.010 736.000 944.290 740.000 ;
    END
  END la_iena[72]
  PIN la_iena[73]
    DIRECTION OUTPUT TRISTATE ;
    USE SIGNAL ;
    PORT
      LAYER met2 ;
        RECT 957.350 736.000 957.630 740.000 ;
    END
  END la_iena[73]
  PIN la_iena[74]
    DIRECTION OUTPUT TRISTATE ;
    USE SIGNAL ;
    PORT
      LAYER met2 ;
        RECT 970.230 736.000 970.510 740.000 ;
    END
  END la_iena[74]
  PIN la_iena[75]
    DIRECTION OUTPUT TRISTATE ;
    USE SIGNAL ;
    PORT
      LAYER met2 ;
        RECT 983.110 736.000 983.390 740.000 ;
    END
  END la_iena[75]
  PIN la_iena[76]
    DIRECTION OUTPUT TRISTATE ;
    USE SIGNAL ;
    PORT
      LAYER met2 ;
        RECT 996.450 736.000 996.730 740.000 ;
    END
  END la_iena[76]
  PIN la_iena[77]
    DIRECTION OUTPUT TRISTATE ;
    USE SIGNAL ;
    PORT
      LAYER met2 ;
        RECT 1009.330 736.000 1009.610 740.000 ;
    END
  END la_iena[77]
  PIN la_iena[78]
    DIRECTION OUTPUT TRISTATE ;
    USE SIGNAL ;
    PORT
      LAYER met2 ;
        RECT 1022.670 736.000 1022.950 740.000 ;
    END
  END la_iena[78]
  PIN la_iena[79]
    DIRECTION OUTPUT TRISTATE ;
    USE SIGNAL ;
    PORT
      LAYER met2 ;
        RECT 1035.550 736.000 1035.830 740.000 ;
    END
  END la_iena[79]
  PIN la_iena[7]
    DIRECTION OUTPUT TRISTATE ;
    USE SIGNAL ;
    PORT
      LAYER met2 ;
        RECT 95.770 736.000 96.050 740.000 ;
    END
  END la_iena[7]
  PIN la_iena[80]
    DIRECTION OUTPUT TRISTATE ;
    USE SIGNAL ;
    PORT
      LAYER met2 ;
        RECT 1048.430 736.000 1048.710 740.000 ;
    END
  END la_iena[80]
  PIN la_iena[81]
    DIRECTION OUTPUT TRISTATE ;
    USE SIGNAL ;
    PORT
      LAYER met2 ;
        RECT 1061.770 736.000 1062.050 740.000 ;
    END
  END la_iena[81]
  PIN la_iena[82]
    DIRECTION OUTPUT TRISTATE ;
    USE SIGNAL ;
    PORT
      LAYER met2 ;
        RECT 1074.650 736.000 1074.930 740.000 ;
    END
  END la_iena[82]
  PIN la_iena[83]
    DIRECTION OUTPUT TRISTATE ;
    USE SIGNAL ;
    PORT
      LAYER met2 ;
        RECT 1087.530 736.000 1087.810 740.000 ;
    END
  END la_iena[83]
  PIN la_iena[84]
    DIRECTION OUTPUT TRISTATE ;
    USE SIGNAL ;
    PORT
      LAYER met2 ;
        RECT 1100.870 736.000 1101.150 740.000 ;
    END
  END la_iena[84]
  PIN la_iena[85]
    DIRECTION OUTPUT TRISTATE ;
    USE SIGNAL ;
    PORT
      LAYER met2 ;
        RECT 1113.750 736.000 1114.030 740.000 ;
    END
  END la_iena[85]
  PIN la_iena[86]
    DIRECTION OUTPUT TRISTATE ;
    USE SIGNAL ;
    PORT
      LAYER met2 ;
        RECT 1127.090 736.000 1127.370 740.000 ;
    END
  END la_iena[86]
  PIN la_iena[87]
    DIRECTION OUTPUT TRISTATE ;
    USE SIGNAL ;
    PORT
      LAYER met2 ;
        RECT 1139.970 736.000 1140.250 740.000 ;
    END
  END la_iena[87]
  PIN la_iena[88]
    DIRECTION OUTPUT TRISTATE ;
    USE SIGNAL ;
    PORT
      LAYER met2 ;
        RECT 1152.850 736.000 1153.130 740.000 ;
    END
  END la_iena[88]
  PIN la_iena[89]
    DIRECTION OUTPUT TRISTATE ;
    USE SIGNAL ;
    PORT
      LAYER met2 ;
        RECT 1166.190 736.000 1166.470 740.000 ;
    END
  END la_iena[89]
  PIN la_iena[8]
    DIRECTION OUTPUT TRISTATE ;
    USE SIGNAL ;
    PORT
      LAYER met2 ;
        RECT 109.110 736.000 109.390 740.000 ;
    END
  END la_iena[8]
  PIN la_iena[90]
    DIRECTION OUTPUT TRISTATE ;
    USE SIGNAL ;
    PORT
      LAYER met2 ;
        RECT 1179.070 736.000 1179.350 740.000 ;
    END
  END la_iena[90]
  PIN la_iena[91]
    DIRECTION OUTPUT TRISTATE ;
    USE SIGNAL ;
    PORT
      LAYER met2 ;
        RECT 1191.950 736.000 1192.230 740.000 ;
    END
  END la_iena[91]
  PIN la_iena[92]
    DIRECTION OUTPUT TRISTATE ;
    USE SIGNAL ;
    PORT
      LAYER met2 ;
        RECT 1205.290 736.000 1205.570 740.000 ;
    END
  END la_iena[92]
  PIN la_iena[93]
    DIRECTION OUTPUT TRISTATE ;
    USE SIGNAL ;
    PORT
      LAYER met2 ;
        RECT 1218.170 736.000 1218.450 740.000 ;
    END
  END la_iena[93]
  PIN la_iena[94]
    DIRECTION OUTPUT TRISTATE ;
    USE SIGNAL ;
    PORT
      LAYER met2 ;
        RECT 1231.510 736.000 1231.790 740.000 ;
    END
  END la_iena[94]
  PIN la_iena[95]
    DIRECTION OUTPUT TRISTATE ;
    USE SIGNAL ;
    PORT
      LAYER met2 ;
        RECT 1244.390 736.000 1244.670 740.000 ;
    END
  END la_iena[95]
  PIN la_iena[96]
    DIRECTION OUTPUT TRISTATE ;
    USE SIGNAL ;
    PORT
      LAYER met2 ;
        RECT 1257.270 736.000 1257.550 740.000 ;
    END
  END la_iena[96]
  PIN la_iena[97]
    DIRECTION OUTPUT TRISTATE ;
    USE SIGNAL ;
    PORT
      LAYER met2 ;
        RECT 1270.610 736.000 1270.890 740.000 ;
    END
  END la_iena[97]
  PIN la_iena[98]
    DIRECTION OUTPUT TRISTATE ;
    USE SIGNAL ;
    PORT
      LAYER met2 ;
        RECT 1283.490 736.000 1283.770 740.000 ;
    END
  END la_iena[98]
  PIN la_iena[99]
    DIRECTION OUTPUT TRISTATE ;
    USE SIGNAL ;
    PORT
      LAYER met2 ;
        RECT 1296.370 736.000 1296.650 740.000 ;
    END
  END la_iena[99]
  PIN la_iena[9]
    DIRECTION OUTPUT TRISTATE ;
    USE SIGNAL ;
    PORT
      LAYER met2 ;
        RECT 121.990 736.000 122.270 740.000 ;
    END
  END la_iena[9]
  PIN la_input[0]
    DIRECTION INPUT ;
    USE SIGNAL ;
    PORT
      LAYER met2 ;
        RECT 7.910 736.000 8.190 740.000 ;
    END
  END la_input[0]
  PIN la_input[100]
    DIRECTION INPUT ;
    USE SIGNAL ;
    PORT
      LAYER met2 ;
        RECT 1312.930 736.000 1313.210 740.000 ;
    END
  END la_input[100]
  PIN la_input[101]
    DIRECTION INPUT ;
    USE SIGNAL ;
    PORT
      LAYER met2 ;
        RECT 1325.810 736.000 1326.090 740.000 ;
    END
  END la_input[101]
  PIN la_input[102]
    DIRECTION INPUT ;
    USE SIGNAL ;
    PORT
      LAYER met2 ;
        RECT 1339.150 736.000 1339.430 740.000 ;
    END
  END la_input[102]
  PIN la_input[103]
    DIRECTION INPUT ;
    USE SIGNAL ;
    PORT
      LAYER met2 ;
        RECT 1352.030 736.000 1352.310 740.000 ;
    END
  END la_input[103]
  PIN la_input[104]
    DIRECTION INPUT ;
    USE SIGNAL ;
    PORT
      LAYER met2 ;
        RECT 1364.910 736.000 1365.190 740.000 ;
    END
  END la_input[104]
  PIN la_input[105]
    DIRECTION INPUT ;
    USE SIGNAL ;
    PORT
      LAYER met2 ;
        RECT 1378.250 736.000 1378.530 740.000 ;
    END
  END la_input[105]
  PIN la_input[106]
    DIRECTION INPUT ;
    USE SIGNAL ;
    PORT
      LAYER met2 ;
        RECT 1391.130 736.000 1391.410 740.000 ;
    END
  END la_input[106]
  PIN la_input[107]
    DIRECTION INPUT ;
    USE SIGNAL ;
    PORT
      LAYER met2 ;
        RECT 1404.010 736.000 1404.290 740.000 ;
    END
  END la_input[107]
  PIN la_input[108]
    DIRECTION INPUT ;
    USE SIGNAL ;
    PORT
      LAYER met2 ;
        RECT 1417.350 736.000 1417.630 740.000 ;
    END
  END la_input[108]
  PIN la_input[109]
    DIRECTION INPUT ;
    USE SIGNAL ;
    PORT
      LAYER met2 ;
        RECT 1430.230 736.000 1430.510 740.000 ;
    END
  END la_input[109]
  PIN la_input[10]
    DIRECTION INPUT ;
    USE SIGNAL ;
    PORT
      LAYER met2 ;
        RECT 138.090 736.000 138.370 740.000 ;
    END
  END la_input[10]
  PIN la_input[110]
    DIRECTION INPUT ;
    USE SIGNAL ;
    PORT
      LAYER met2 ;
        RECT 1443.570 736.000 1443.850 740.000 ;
    END
  END la_input[110]
  PIN la_input[111]
    DIRECTION INPUT ;
    USE SIGNAL ;
    PORT
      LAYER met2 ;
        RECT 1456.450 736.000 1456.730 740.000 ;
    END
  END la_input[111]
  PIN la_input[112]
    DIRECTION INPUT ;
    USE SIGNAL ;
    PORT
      LAYER met2 ;
        RECT 1469.330 736.000 1469.610 740.000 ;
    END
  END la_input[112]
  PIN la_input[113]
    DIRECTION INPUT ;
    USE SIGNAL ;
    PORT
      LAYER met2 ;
        RECT 1482.670 736.000 1482.950 740.000 ;
    END
  END la_input[113]
  PIN la_input[114]
    DIRECTION INPUT ;
    USE SIGNAL ;
    PORT
      LAYER met2 ;
        RECT 1495.550 736.000 1495.830 740.000 ;
    END
  END la_input[114]
  PIN la_input[115]
    DIRECTION INPUT ;
    USE SIGNAL ;
    PORT
      LAYER met2 ;
        RECT 1508.430 736.000 1508.710 740.000 ;
    END
  END la_input[115]
  PIN la_input[116]
    DIRECTION INPUT ;
    USE SIGNAL ;
    PORT
      LAYER met2 ;
        RECT 1521.770 736.000 1522.050 740.000 ;
    END
  END la_input[116]
  PIN la_input[117]
    DIRECTION INPUT ;
    USE SIGNAL ;
    PORT
      LAYER met2 ;
        RECT 1534.650 736.000 1534.930 740.000 ;
    END
  END la_input[117]
  PIN la_input[118]
    DIRECTION INPUT ;
    USE SIGNAL ;
    PORT
      LAYER met2 ;
        RECT 1547.990 736.000 1548.270 740.000 ;
    END
  END la_input[118]
  PIN la_input[119]
    DIRECTION INPUT ;
    USE SIGNAL ;
    PORT
      LAYER met2 ;
        RECT 1560.870 736.000 1561.150 740.000 ;
    END
  END la_input[119]
  PIN la_input[11]
    DIRECTION INPUT ;
    USE SIGNAL ;
    PORT
      LAYER met2 ;
        RECT 151.430 736.000 151.710 740.000 ;
    END
  END la_input[11]
  PIN la_input[120]
    DIRECTION INPUT ;
    USE SIGNAL ;
    PORT
      LAYER met2 ;
        RECT 1573.750 736.000 1574.030 740.000 ;
    END
  END la_input[120]
  PIN la_input[121]
    DIRECTION INPUT ;
    USE SIGNAL ;
    PORT
      LAYER met2 ;
        RECT 1587.090 736.000 1587.370 740.000 ;
    END
  END la_input[121]
  PIN la_input[122]
    DIRECTION INPUT ;
    USE SIGNAL ;
    PORT
      LAYER met2 ;
        RECT 1599.970 736.000 1600.250 740.000 ;
    END
  END la_input[122]
  PIN la_input[123]
    DIRECTION INPUT ;
    USE SIGNAL ;
    PORT
      LAYER met2 ;
        RECT 1612.850 736.000 1613.130 740.000 ;
    END
  END la_input[123]
  PIN la_input[124]
    DIRECTION INPUT ;
    USE SIGNAL ;
    PORT
      LAYER met2 ;
        RECT 1626.190 736.000 1626.470 740.000 ;
    END
  END la_input[124]
  PIN la_input[125]
    DIRECTION INPUT ;
    USE SIGNAL ;
    PORT
      LAYER met2 ;
        RECT 1639.070 736.000 1639.350 740.000 ;
    END
  END la_input[125]
  PIN la_input[126]
    DIRECTION INPUT ;
    USE SIGNAL ;
    PORT
      LAYER met2 ;
        RECT 1652.410 736.000 1652.690 740.000 ;
    END
  END la_input[126]
  PIN la_input[127]
    DIRECTION INPUT ;
    USE SIGNAL ;
    PORT
      LAYER met2 ;
        RECT 1665.290 736.000 1665.570 740.000 ;
    END
  END la_input[127]
  PIN la_input[12]
    DIRECTION INPUT ;
    USE SIGNAL ;
    PORT
      LAYER met2 ;
        RECT 164.310 736.000 164.590 740.000 ;
    END
  END la_input[12]
  PIN la_input[13]
    DIRECTION INPUT ;
    USE SIGNAL ;
    PORT
      LAYER met2 ;
        RECT 177.650 736.000 177.930 740.000 ;
    END
  END la_input[13]
  PIN la_input[14]
    DIRECTION INPUT ;
    USE SIGNAL ;
    PORT
      LAYER met2 ;
        RECT 190.530 736.000 190.810 740.000 ;
    END
  END la_input[14]
  PIN la_input[15]
    DIRECTION INPUT ;
    USE SIGNAL ;
    PORT
      LAYER met2 ;
        RECT 203.410 736.000 203.690 740.000 ;
    END
  END la_input[15]
  PIN la_input[16]
    DIRECTION INPUT ;
    USE SIGNAL ;
    PORT
      LAYER met2 ;
        RECT 216.750 736.000 217.030 740.000 ;
    END
  END la_input[16]
  PIN la_input[17]
    DIRECTION INPUT ;
    USE SIGNAL ;
    PORT
      LAYER met2 ;
        RECT 229.630 736.000 229.910 740.000 ;
    END
  END la_input[17]
  PIN la_input[18]
    DIRECTION INPUT ;
    USE SIGNAL ;
    PORT
      LAYER met2 ;
        RECT 242.510 736.000 242.790 740.000 ;
    END
  END la_input[18]
  PIN la_input[19]
    DIRECTION INPUT ;
    USE SIGNAL ;
    PORT
      LAYER met2 ;
        RECT 255.850 736.000 256.130 740.000 ;
    END
  END la_input[19]
  PIN la_input[1]
    DIRECTION INPUT ;
    USE SIGNAL ;
    PORT
      LAYER met2 ;
        RECT 20.790 736.000 21.070 740.000 ;
    END
  END la_input[1]
  PIN la_input[20]
    DIRECTION INPUT ;
    USE SIGNAL ;
    PORT
      LAYER met2 ;
        RECT 268.730 736.000 269.010 740.000 ;
    END
  END la_input[20]
  PIN la_input[21]
    DIRECTION INPUT ;
    USE SIGNAL ;
    PORT
      LAYER met2 ;
        RECT 281.610 736.000 281.890 740.000 ;
    END
  END la_input[21]
  PIN la_input[22]
    DIRECTION INPUT ;
    USE SIGNAL ;
    PORT
      LAYER met2 ;
        RECT 294.950 736.000 295.230 740.000 ;
    END
  END la_input[22]
  PIN la_input[23]
    DIRECTION INPUT ;
    USE SIGNAL ;
    PORT
      LAYER met2 ;
        RECT 307.830 736.000 308.110 740.000 ;
    END
  END la_input[23]
  PIN la_input[24]
    DIRECTION INPUT ;
    USE SIGNAL ;
    PORT
      LAYER met2 ;
        RECT 321.170 736.000 321.450 740.000 ;
    END
  END la_input[24]
  PIN la_input[25]
    DIRECTION INPUT ;
    USE SIGNAL ;
    PORT
      LAYER met2 ;
        RECT 334.050 736.000 334.330 740.000 ;
    END
  END la_input[25]
  PIN la_input[26]
    DIRECTION INPUT ;
    USE SIGNAL ;
    PORT
      LAYER met2 ;
        RECT 346.930 736.000 347.210 740.000 ;
    END
  END la_input[26]
  PIN la_input[27]
    DIRECTION INPUT ;
    USE SIGNAL ;
    PORT
      LAYER met2 ;
        RECT 360.270 736.000 360.550 740.000 ;
    END
  END la_input[27]
  PIN la_input[28]
    DIRECTION INPUT ;
    USE SIGNAL ;
    PORT
      LAYER met2 ;
        RECT 373.150 736.000 373.430 740.000 ;
    END
  END la_input[28]
  PIN la_input[29]
    DIRECTION INPUT ;
    USE SIGNAL ;
    PORT
      LAYER met2 ;
        RECT 386.030 736.000 386.310 740.000 ;
    END
  END la_input[29]
  PIN la_input[2]
    DIRECTION INPUT ;
    USE SIGNAL ;
    PORT
      LAYER met2 ;
        RECT 33.670 736.000 33.950 740.000 ;
    END
  END la_input[2]
  PIN la_input[30]
    DIRECTION INPUT ;
    USE SIGNAL ;
    PORT
      LAYER met2 ;
        RECT 399.370 736.000 399.650 740.000 ;
    END
  END la_input[30]
  PIN la_input[31]
    DIRECTION INPUT ;
    USE SIGNAL ;
    PORT
      LAYER met2 ;
        RECT 412.250 736.000 412.530 740.000 ;
    END
  END la_input[31]
  PIN la_input[32]
    DIRECTION INPUT ;
    USE SIGNAL ;
    PORT
      LAYER met2 ;
        RECT 425.590 736.000 425.870 740.000 ;
    END
  END la_input[32]
  PIN la_input[33]
    DIRECTION INPUT ;
    USE SIGNAL ;
    PORT
      LAYER met2 ;
        RECT 438.470 736.000 438.750 740.000 ;
    END
  END la_input[33]
  PIN la_input[34]
    DIRECTION INPUT ;
    USE SIGNAL ;
    PORT
      LAYER met2 ;
        RECT 451.350 736.000 451.630 740.000 ;
    END
  END la_input[34]
  PIN la_input[35]
    DIRECTION INPUT ;
    USE SIGNAL ;
    PORT
      LAYER met2 ;
        RECT 464.690 736.000 464.970 740.000 ;
    END
  END la_input[35]
  PIN la_input[36]
    DIRECTION INPUT ;
    USE SIGNAL ;
    PORT
      LAYER met2 ;
        RECT 477.570 736.000 477.850 740.000 ;
    END
  END la_input[36]
  PIN la_input[37]
    DIRECTION INPUT ;
    USE SIGNAL ;
    PORT
      LAYER met2 ;
        RECT 490.450 736.000 490.730 740.000 ;
    END
  END la_input[37]
  PIN la_input[38]
    DIRECTION INPUT ;
    USE SIGNAL ;
    PORT
      LAYER met2 ;
        RECT 503.790 736.000 504.070 740.000 ;
    END
  END la_input[38]
  PIN la_input[39]
    DIRECTION INPUT ;
    USE SIGNAL ;
    PORT
      LAYER met2 ;
        RECT 516.670 736.000 516.950 740.000 ;
    END
  END la_input[39]
  PIN la_input[3]
    DIRECTION INPUT ;
    USE SIGNAL ;
    PORT
      LAYER met2 ;
        RECT 47.010 736.000 47.290 740.000 ;
    END
  END la_input[3]
  PIN la_input[40]
    DIRECTION INPUT ;
    USE SIGNAL ;
    PORT
      LAYER met2 ;
        RECT 530.010 736.000 530.290 740.000 ;
    END
  END la_input[40]
  PIN la_input[41]
    DIRECTION INPUT ;
    USE SIGNAL ;
    PORT
      LAYER met2 ;
        RECT 542.890 736.000 543.170 740.000 ;
    END
  END la_input[41]
  PIN la_input[42]
    DIRECTION INPUT ;
    USE SIGNAL ;
    PORT
      LAYER met2 ;
        RECT 555.770 736.000 556.050 740.000 ;
    END
  END la_input[42]
  PIN la_input[43]
    DIRECTION INPUT ;
    USE SIGNAL ;
    PORT
      LAYER met2 ;
        RECT 569.110 736.000 569.390 740.000 ;
    END
  END la_input[43]
  PIN la_input[44]
    DIRECTION INPUT ;
    USE SIGNAL ;
    PORT
      LAYER met2 ;
        RECT 581.990 736.000 582.270 740.000 ;
    END
  END la_input[44]
  PIN la_input[45]
    DIRECTION INPUT ;
    USE SIGNAL ;
    PORT
      LAYER met2 ;
        RECT 594.870 736.000 595.150 740.000 ;
    END
  END la_input[45]
  PIN la_input[46]
    DIRECTION INPUT ;
    USE SIGNAL ;
    PORT
      LAYER met2 ;
        RECT 608.210 736.000 608.490 740.000 ;
    END
  END la_input[46]
  PIN la_input[47]
    DIRECTION INPUT ;
    USE SIGNAL ;
    PORT
      LAYER met2 ;
        RECT 621.090 736.000 621.370 740.000 ;
    END
  END la_input[47]
  PIN la_input[48]
    DIRECTION INPUT ;
    USE SIGNAL ;
    PORT
      LAYER met2 ;
        RECT 634.430 736.000 634.710 740.000 ;
    END
  END la_input[48]
  PIN la_input[49]
    DIRECTION INPUT ;
    USE SIGNAL ;
    PORT
      LAYER met2 ;
        RECT 647.310 736.000 647.590 740.000 ;
    END
  END la_input[49]
  PIN la_input[4]
    DIRECTION INPUT ;
    USE SIGNAL ;
    PORT
      LAYER met2 ;
        RECT 59.890 736.000 60.170 740.000 ;
    END
  END la_input[4]
  PIN la_input[50]
    DIRECTION INPUT ;
    USE SIGNAL ;
    PORT
      LAYER met2 ;
        RECT 660.190 736.000 660.470 740.000 ;
    END
  END la_input[50]
  PIN la_input[51]
    DIRECTION INPUT ;
    USE SIGNAL ;
    PORT
      LAYER met2 ;
        RECT 673.530 736.000 673.810 740.000 ;
    END
  END la_input[51]
  PIN la_input[52]
    DIRECTION INPUT ;
    USE SIGNAL ;
    PORT
      LAYER met2 ;
        RECT 686.410 736.000 686.690 740.000 ;
    END
  END la_input[52]
  PIN la_input[53]
    DIRECTION INPUT ;
    USE SIGNAL ;
    PORT
      LAYER met2 ;
        RECT 699.290 736.000 699.570 740.000 ;
    END
  END la_input[53]
  PIN la_input[54]
    DIRECTION INPUT ;
    USE SIGNAL ;
    PORT
      LAYER met2 ;
        RECT 712.630 736.000 712.910 740.000 ;
    END
  END la_input[54]
  PIN la_input[55]
    DIRECTION INPUT ;
    USE SIGNAL ;
    PORT
      LAYER met2 ;
        RECT 725.510 736.000 725.790 740.000 ;
    END
  END la_input[55]
  PIN la_input[56]
    DIRECTION INPUT ;
    USE SIGNAL ;
    PORT
      LAYER met2 ;
        RECT 738.850 736.000 739.130 740.000 ;
    END
  END la_input[56]
  PIN la_input[57]
    DIRECTION INPUT ;
    USE SIGNAL ;
    PORT
      LAYER met2 ;
        RECT 751.730 736.000 752.010 740.000 ;
    END
  END la_input[57]
  PIN la_input[58]
    DIRECTION INPUT ;
    USE SIGNAL ;
    PORT
      LAYER met2 ;
        RECT 764.610 736.000 764.890 740.000 ;
    END
  END la_input[58]
  PIN la_input[59]
    DIRECTION INPUT ;
    USE SIGNAL ;
    PORT
      LAYER met2 ;
        RECT 777.950 736.000 778.230 740.000 ;
    END
  END la_input[59]
  PIN la_input[5]
    DIRECTION INPUT ;
    USE SIGNAL ;
    PORT
      LAYER met2 ;
        RECT 73.230 736.000 73.510 740.000 ;
    END
  END la_input[5]
  PIN la_input[60]
    DIRECTION INPUT ;
    USE SIGNAL ;
    PORT
      LAYER met2 ;
        RECT 790.830 736.000 791.110 740.000 ;
    END
  END la_input[60]
  PIN la_input[61]
    DIRECTION INPUT ;
    USE SIGNAL ;
    PORT
      LAYER met2 ;
        RECT 803.710 736.000 803.990 740.000 ;
    END
  END la_input[61]
  PIN la_input[62]
    DIRECTION INPUT ;
    USE SIGNAL ;
    PORT
      LAYER met2 ;
        RECT 817.050 736.000 817.330 740.000 ;
    END
  END la_input[62]
  PIN la_input[63]
    DIRECTION INPUT ;
    USE SIGNAL ;
    PORT
      LAYER met2 ;
        RECT 829.930 736.000 830.210 740.000 ;
    END
  END la_input[63]
  PIN la_input[64]
    DIRECTION INPUT ;
    USE SIGNAL ;
    PORT
      LAYER met2 ;
        RECT 842.810 736.000 843.090 740.000 ;
    END
  END la_input[64]
  PIN la_input[65]
    DIRECTION INPUT ;
    USE SIGNAL ;
    PORT
      LAYER met2 ;
        RECT 856.150 736.000 856.430 740.000 ;
    END
  END la_input[65]
  PIN la_input[66]
    DIRECTION INPUT ;
    USE SIGNAL ;
    PORT
      LAYER met2 ;
        RECT 869.030 736.000 869.310 740.000 ;
    END
  END la_input[66]
  PIN la_input[67]
    DIRECTION INPUT ;
    USE SIGNAL ;
    PORT
      LAYER met2 ;
        RECT 882.370 736.000 882.650 740.000 ;
    END
  END la_input[67]
  PIN la_input[68]
    DIRECTION INPUT ;
    USE SIGNAL ;
    PORT
      LAYER met2 ;
        RECT 895.250 736.000 895.530 740.000 ;
    END
  END la_input[68]
  PIN la_input[69]
    DIRECTION INPUT ;
    USE SIGNAL ;
    PORT
      LAYER met2 ;
        RECT 908.130 736.000 908.410 740.000 ;
    END
  END la_input[69]
  PIN la_input[6]
    DIRECTION INPUT ;
    USE SIGNAL ;
    PORT
      LAYER met2 ;
        RECT 86.110 736.000 86.390 740.000 ;
    END
  END la_input[6]
  PIN la_input[70]
    DIRECTION INPUT ;
    USE SIGNAL ;
    PORT
      LAYER met2 ;
        RECT 921.470 736.000 921.750 740.000 ;
    END
  END la_input[70]
  PIN la_input[71]
    DIRECTION INPUT ;
    USE SIGNAL ;
    PORT
      LAYER met2 ;
        RECT 934.350 736.000 934.630 740.000 ;
    END
  END la_input[71]
  PIN la_input[72]
    DIRECTION INPUT ;
    USE SIGNAL ;
    PORT
      LAYER met2 ;
        RECT 947.230 736.000 947.510 740.000 ;
    END
  END la_input[72]
  PIN la_input[73]
    DIRECTION INPUT ;
    USE SIGNAL ;
    PORT
      LAYER met2 ;
        RECT 960.570 736.000 960.850 740.000 ;
    END
  END la_input[73]
  PIN la_input[74]
    DIRECTION INPUT ;
    USE SIGNAL ;
    PORT
      LAYER met2 ;
        RECT 973.450 736.000 973.730 740.000 ;
    END
  END la_input[74]
  PIN la_input[75]
    DIRECTION INPUT ;
    USE SIGNAL ;
    PORT
      LAYER met2 ;
        RECT 986.790 736.000 987.070 740.000 ;
    END
  END la_input[75]
  PIN la_input[76]
    DIRECTION INPUT ;
    USE SIGNAL ;
    PORT
      LAYER met2 ;
        RECT 999.670 736.000 999.950 740.000 ;
    END
  END la_input[76]
  PIN la_input[77]
    DIRECTION INPUT ;
    USE SIGNAL ;
    PORT
      LAYER met2 ;
        RECT 1012.550 736.000 1012.830 740.000 ;
    END
  END la_input[77]
  PIN la_input[78]
    DIRECTION INPUT ;
    USE SIGNAL ;
    PORT
      LAYER met2 ;
        RECT 1025.890 736.000 1026.170 740.000 ;
    END
  END la_input[78]
  PIN la_input[79]
    DIRECTION INPUT ;
    USE SIGNAL ;
    PORT
      LAYER met2 ;
        RECT 1038.770 736.000 1039.050 740.000 ;
    END
  END la_input[79]
  PIN la_input[7]
    DIRECTION INPUT ;
    USE SIGNAL ;
    PORT
      LAYER met2 ;
        RECT 98.990 736.000 99.270 740.000 ;
    END
  END la_input[7]
  PIN la_input[80]
    DIRECTION INPUT ;
    USE SIGNAL ;
    PORT
      LAYER met2 ;
        RECT 1051.650 736.000 1051.930 740.000 ;
    END
  END la_input[80]
  PIN la_input[81]
    DIRECTION INPUT ;
    USE SIGNAL ;
    PORT
      LAYER met2 ;
        RECT 1064.990 736.000 1065.270 740.000 ;
    END
  END la_input[81]
  PIN la_input[82]
    DIRECTION INPUT ;
    USE SIGNAL ;
    PORT
      LAYER met2 ;
        RECT 1077.870 736.000 1078.150 740.000 ;
    END
  END la_input[82]
  PIN la_input[83]
    DIRECTION INPUT ;
    USE SIGNAL ;
    PORT
      LAYER met2 ;
        RECT 1091.210 736.000 1091.490 740.000 ;
    END
  END la_input[83]
  PIN la_input[84]
    DIRECTION INPUT ;
    USE SIGNAL ;
    PORT
      LAYER met2 ;
        RECT 1104.090 736.000 1104.370 740.000 ;
    END
  END la_input[84]
  PIN la_input[85]
    DIRECTION INPUT ;
    USE SIGNAL ;
    PORT
      LAYER met2 ;
        RECT 1116.970 736.000 1117.250 740.000 ;
    END
  END la_input[85]
  PIN la_input[86]
    DIRECTION INPUT ;
    USE SIGNAL ;
    PORT
      LAYER met2 ;
        RECT 1130.310 736.000 1130.590 740.000 ;
    END
  END la_input[86]
  PIN la_input[87]
    DIRECTION INPUT ;
    USE SIGNAL ;
    PORT
      LAYER met2 ;
        RECT 1143.190 736.000 1143.470 740.000 ;
    END
  END la_input[87]
  PIN la_input[88]
    DIRECTION INPUT ;
    USE SIGNAL ;
    PORT
      LAYER met2 ;
        RECT 1156.070 736.000 1156.350 740.000 ;
    END
  END la_input[88]
  PIN la_input[89]
    DIRECTION INPUT ;
    USE SIGNAL ;
    PORT
      LAYER met2 ;
        RECT 1169.410 736.000 1169.690 740.000 ;
    END
  END la_input[89]
  PIN la_input[8]
    DIRECTION INPUT ;
    USE SIGNAL ;
    PORT
      LAYER met2 ;
        RECT 112.330 736.000 112.610 740.000 ;
    END
  END la_input[8]
  PIN la_input[90]
    DIRECTION INPUT ;
    USE SIGNAL ;
    PORT
      LAYER met2 ;
        RECT 1182.290 736.000 1182.570 740.000 ;
    END
  END la_input[90]
  PIN la_input[91]
    DIRECTION INPUT ;
    USE SIGNAL ;
    PORT
      LAYER met2 ;
        RECT 1195.630 736.000 1195.910 740.000 ;
    END
  END la_input[91]
  PIN la_input[92]
    DIRECTION INPUT ;
    USE SIGNAL ;
    PORT
      LAYER met2 ;
        RECT 1208.510 736.000 1208.790 740.000 ;
    END
  END la_input[92]
  PIN la_input[93]
    DIRECTION INPUT ;
    USE SIGNAL ;
    PORT
      LAYER met2 ;
        RECT 1221.390 736.000 1221.670 740.000 ;
    END
  END la_input[93]
  PIN la_input[94]
    DIRECTION INPUT ;
    USE SIGNAL ;
    PORT
      LAYER met2 ;
        RECT 1234.730 736.000 1235.010 740.000 ;
    END
  END la_input[94]
  PIN la_input[95]
    DIRECTION INPUT ;
    USE SIGNAL ;
    PORT
      LAYER met2 ;
        RECT 1247.610 736.000 1247.890 740.000 ;
    END
  END la_input[95]
  PIN la_input[96]
    DIRECTION INPUT ;
    USE SIGNAL ;
    PORT
      LAYER met2 ;
        RECT 1260.490 736.000 1260.770 740.000 ;
    END
  END la_input[96]
  PIN la_input[97]
    DIRECTION INPUT ;
    USE SIGNAL ;
    PORT
      LAYER met2 ;
        RECT 1273.830 736.000 1274.110 740.000 ;
    END
  END la_input[97]
  PIN la_input[98]
    DIRECTION INPUT ;
    USE SIGNAL ;
    PORT
      LAYER met2 ;
        RECT 1286.710 736.000 1286.990 740.000 ;
    END
  END la_input[98]
  PIN la_input[99]
    DIRECTION INPUT ;
    USE SIGNAL ;
    PORT
      LAYER met2 ;
        RECT 1300.050 736.000 1300.330 740.000 ;
    END
  END la_input[99]
  PIN la_input[9]
    DIRECTION INPUT ;
    USE SIGNAL ;
    PORT
      LAYER met2 ;
        RECT 125.210 736.000 125.490 740.000 ;
    END
  END la_input[9]
  PIN la_oenb[0]
    DIRECTION OUTPUT TRISTATE ;
    USE SIGNAL ;
    PORT
      LAYER met2 ;
        RECT 11.130 736.000 11.410 740.000 ;
    END
  END la_oenb[0]
  PIN la_oenb[100]
    DIRECTION OUTPUT TRISTATE ;
    USE SIGNAL ;
    PORT
      LAYER met2 ;
        RECT 1316.150 736.000 1316.430 740.000 ;
    END
  END la_oenb[100]
  PIN la_oenb[101]
    DIRECTION OUTPUT TRISTATE ;
    USE SIGNAL ;
    PORT
      LAYER met2 ;
        RECT 1329.030 736.000 1329.310 740.000 ;
    END
  END la_oenb[101]
  PIN la_oenb[102]
    DIRECTION OUTPUT TRISTATE ;
    USE SIGNAL ;
    PORT
      LAYER met2 ;
        RECT 1342.370 736.000 1342.650 740.000 ;
    END
  END la_oenb[102]
  PIN la_oenb[103]
    DIRECTION OUTPUT TRISTATE ;
    USE SIGNAL ;
    PORT
      LAYER met2 ;
        RECT 1355.250 736.000 1355.530 740.000 ;
    END
  END la_oenb[103]
  PIN la_oenb[104]
    DIRECTION OUTPUT TRISTATE ;
    USE SIGNAL ;
    PORT
      LAYER met2 ;
        RECT 1368.130 736.000 1368.410 740.000 ;
    END
  END la_oenb[104]
  PIN la_oenb[105]
    DIRECTION OUTPUT TRISTATE ;
    USE SIGNAL ;
    PORT
      LAYER met2 ;
        RECT 1381.470 736.000 1381.750 740.000 ;
    END
  END la_oenb[105]
  PIN la_oenb[106]
    DIRECTION OUTPUT TRISTATE ;
    USE SIGNAL ;
    PORT
      LAYER met2 ;
        RECT 1394.350 736.000 1394.630 740.000 ;
    END
  END la_oenb[106]
  PIN la_oenb[107]
    DIRECTION OUTPUT TRISTATE ;
    USE SIGNAL ;
    PORT
      LAYER met2 ;
        RECT 1407.690 736.000 1407.970 740.000 ;
    END
  END la_oenb[107]
  PIN la_oenb[108]
    DIRECTION OUTPUT TRISTATE ;
    USE SIGNAL ;
    PORT
      LAYER met2 ;
        RECT 1420.570 736.000 1420.850 740.000 ;
    END
  END la_oenb[108]
  PIN la_oenb[109]
    DIRECTION OUTPUT TRISTATE ;
    USE SIGNAL ;
    PORT
      LAYER met2 ;
        RECT 1433.450 736.000 1433.730 740.000 ;
    END
  END la_oenb[109]
  PIN la_oenb[10]
    DIRECTION OUTPUT TRISTATE ;
    USE SIGNAL ;
    PORT
      LAYER met2 ;
        RECT 141.310 736.000 141.590 740.000 ;
    END
  END la_oenb[10]
  PIN la_oenb[110]
    DIRECTION OUTPUT TRISTATE ;
    USE SIGNAL ;
    PORT
      LAYER met2 ;
        RECT 1446.790 736.000 1447.070 740.000 ;
    END
  END la_oenb[110]
  PIN la_oenb[111]
    DIRECTION OUTPUT TRISTATE ;
    USE SIGNAL ;
    PORT
      LAYER met2 ;
        RECT 1459.670 736.000 1459.950 740.000 ;
    END
  END la_oenb[111]
  PIN la_oenb[112]
    DIRECTION OUTPUT TRISTATE ;
    USE SIGNAL ;
    PORT
      LAYER met2 ;
        RECT 1472.550 736.000 1472.830 740.000 ;
    END
  END la_oenb[112]
  PIN la_oenb[113]
    DIRECTION OUTPUT TRISTATE ;
    USE SIGNAL ;
    PORT
      LAYER met2 ;
        RECT 1485.890 736.000 1486.170 740.000 ;
    END
  END la_oenb[113]
  PIN la_oenb[114]
    DIRECTION OUTPUT TRISTATE ;
    USE SIGNAL ;
    PORT
      LAYER met2 ;
        RECT 1498.770 736.000 1499.050 740.000 ;
    END
  END la_oenb[114]
  PIN la_oenb[115]
    DIRECTION OUTPUT TRISTATE ;
    USE SIGNAL ;
    PORT
      LAYER met2 ;
        RECT 1512.110 736.000 1512.390 740.000 ;
    END
  END la_oenb[115]
  PIN la_oenb[116]
    DIRECTION OUTPUT TRISTATE ;
    USE SIGNAL ;
    PORT
      LAYER met2 ;
        RECT 1524.990 736.000 1525.270 740.000 ;
    END
  END la_oenb[116]
  PIN la_oenb[117]
    DIRECTION OUTPUT TRISTATE ;
    USE SIGNAL ;
    PORT
      LAYER met2 ;
        RECT 1537.870 736.000 1538.150 740.000 ;
    END
  END la_oenb[117]
  PIN la_oenb[118]
    DIRECTION OUTPUT TRISTATE ;
    USE SIGNAL ;
    PORT
      LAYER met2 ;
        RECT 1551.210 736.000 1551.490 740.000 ;
    END
  END la_oenb[118]
  PIN la_oenb[119]
    DIRECTION OUTPUT TRISTATE ;
    USE SIGNAL ;
    PORT
      LAYER met2 ;
        RECT 1564.090 736.000 1564.370 740.000 ;
    END
  END la_oenb[119]
  PIN la_oenb[11]
    DIRECTION OUTPUT TRISTATE ;
    USE SIGNAL ;
    PORT
      LAYER met2 ;
        RECT 154.650 736.000 154.930 740.000 ;
    END
  END la_oenb[11]
  PIN la_oenb[120]
    DIRECTION OUTPUT TRISTATE ;
    USE SIGNAL ;
    PORT
      LAYER met2 ;
        RECT 1576.970 736.000 1577.250 740.000 ;
    END
  END la_oenb[120]
  PIN la_oenb[121]
    DIRECTION OUTPUT TRISTATE ;
    USE SIGNAL ;
    PORT
      LAYER met2 ;
        RECT 1590.310 736.000 1590.590 740.000 ;
    END
  END la_oenb[121]
  PIN la_oenb[122]
    DIRECTION OUTPUT TRISTATE ;
    USE SIGNAL ;
    PORT
      LAYER met2 ;
        RECT 1603.190 736.000 1603.470 740.000 ;
    END
  END la_oenb[122]
  PIN la_oenb[123]
    DIRECTION OUTPUT TRISTATE ;
    USE SIGNAL ;
    PORT
      LAYER met2 ;
        RECT 1616.530 736.000 1616.810 740.000 ;
    END
  END la_oenb[123]
  PIN la_oenb[124]
    DIRECTION OUTPUT TRISTATE ;
    USE SIGNAL ;
    PORT
      LAYER met2 ;
        RECT 1629.410 736.000 1629.690 740.000 ;
    END
  END la_oenb[124]
  PIN la_oenb[125]
    DIRECTION OUTPUT TRISTATE ;
    USE SIGNAL ;
    PORT
      LAYER met2 ;
        RECT 1642.290 736.000 1642.570 740.000 ;
    END
  END la_oenb[125]
  PIN la_oenb[126]
    DIRECTION OUTPUT TRISTATE ;
    USE SIGNAL ;
    PORT
      LAYER met2 ;
        RECT 1655.630 736.000 1655.910 740.000 ;
    END
  END la_oenb[126]
  PIN la_oenb[127]
    DIRECTION OUTPUT TRISTATE ;
    USE SIGNAL ;
    PORT
      LAYER met2 ;
        RECT 1668.510 736.000 1668.790 740.000 ;
    END
  END la_oenb[127]
  PIN la_oenb[12]
    DIRECTION OUTPUT TRISTATE ;
    USE SIGNAL ;
    PORT
      LAYER met2 ;
        RECT 167.530 736.000 167.810 740.000 ;
    END
  END la_oenb[12]
  PIN la_oenb[13]
    DIRECTION OUTPUT TRISTATE ;
    USE SIGNAL ;
    PORT
      LAYER met2 ;
        RECT 180.870 736.000 181.150 740.000 ;
    END
  END la_oenb[13]
  PIN la_oenb[14]
    DIRECTION OUTPUT TRISTATE ;
    USE SIGNAL ;
    PORT
      LAYER met2 ;
        RECT 193.750 736.000 194.030 740.000 ;
    END
  END la_oenb[14]
  PIN la_oenb[15]
    DIRECTION OUTPUT TRISTATE ;
    USE SIGNAL ;
    PORT
      LAYER met2 ;
        RECT 206.630 736.000 206.910 740.000 ;
    END
  END la_oenb[15]
  PIN la_oenb[16]
    DIRECTION OUTPUT TRISTATE ;
    USE SIGNAL ;
    PORT
      LAYER met2 ;
        RECT 219.970 736.000 220.250 740.000 ;
    END
  END la_oenb[16]
  PIN la_oenb[17]
    DIRECTION OUTPUT TRISTATE ;
    USE SIGNAL ;
    PORT
      LAYER met2 ;
        RECT 232.850 736.000 233.130 740.000 ;
    END
  END la_oenb[17]
  PIN la_oenb[18]
    DIRECTION OUTPUT TRISTATE ;
    USE SIGNAL ;
    PORT
      LAYER met2 ;
        RECT 245.730 736.000 246.010 740.000 ;
    END
  END la_oenb[18]
  PIN la_oenb[19]
    DIRECTION OUTPUT TRISTATE ;
    USE SIGNAL ;
    PORT
      LAYER met2 ;
        RECT 259.070 736.000 259.350 740.000 ;
    END
  END la_oenb[19]
  PIN la_oenb[1]
    DIRECTION OUTPUT TRISTATE ;
    USE SIGNAL ;
    PORT
      LAYER met2 ;
        RECT 24.010 736.000 24.290 740.000 ;
    END
  END la_oenb[1]
  PIN la_oenb[20]
    DIRECTION OUTPUT TRISTATE ;
    USE SIGNAL ;
    PORT
      LAYER met2 ;
        RECT 271.950 736.000 272.230 740.000 ;
    END
  END la_oenb[20]
  PIN la_oenb[21]
    DIRECTION OUTPUT TRISTATE ;
    USE SIGNAL ;
    PORT
      LAYER met2 ;
        RECT 285.290 736.000 285.570 740.000 ;
    END
  END la_oenb[21]
  PIN la_oenb[22]
    DIRECTION OUTPUT TRISTATE ;
    USE SIGNAL ;
    PORT
      LAYER met2 ;
        RECT 298.170 736.000 298.450 740.000 ;
    END
  END la_oenb[22]
  PIN la_oenb[23]
    DIRECTION OUTPUT TRISTATE ;
    USE SIGNAL ;
    PORT
      LAYER met2 ;
        RECT 311.050 736.000 311.330 740.000 ;
    END
  END la_oenb[23]
  PIN la_oenb[24]
    DIRECTION OUTPUT TRISTATE ;
    USE SIGNAL ;
    PORT
      LAYER met2 ;
        RECT 324.390 736.000 324.670 740.000 ;
    END
  END la_oenb[24]
  PIN la_oenb[25]
    DIRECTION OUTPUT TRISTATE ;
    USE SIGNAL ;
    PORT
      LAYER met2 ;
        RECT 337.270 736.000 337.550 740.000 ;
    END
  END la_oenb[25]
  PIN la_oenb[26]
    DIRECTION OUTPUT TRISTATE ;
    USE SIGNAL ;
    PORT
      LAYER met2 ;
        RECT 350.150 736.000 350.430 740.000 ;
    END
  END la_oenb[26]
  PIN la_oenb[27]
    DIRECTION OUTPUT TRISTATE ;
    USE SIGNAL ;
    PORT
      LAYER met2 ;
        RECT 363.490 736.000 363.770 740.000 ;
    END
  END la_oenb[27]
  PIN la_oenb[28]
    DIRECTION OUTPUT TRISTATE ;
    USE SIGNAL ;
    PORT
      LAYER met2 ;
        RECT 376.370 736.000 376.650 740.000 ;
    END
  END la_oenb[28]
  PIN la_oenb[29]
    DIRECTION OUTPUT TRISTATE ;
    USE SIGNAL ;
    PORT
      LAYER met2 ;
        RECT 389.710 736.000 389.990 740.000 ;
    END
  END la_oenb[29]
  PIN la_oenb[2]
    DIRECTION OUTPUT TRISTATE ;
    USE SIGNAL ;
    PORT
      LAYER met2 ;
        RECT 37.350 736.000 37.630 740.000 ;
    END
  END la_oenb[2]
  PIN la_oenb[30]
    DIRECTION OUTPUT TRISTATE ;
    USE SIGNAL ;
    PORT
      LAYER met2 ;
        RECT 402.590 736.000 402.870 740.000 ;
    END
  END la_oenb[30]
  PIN la_oenb[31]
    DIRECTION OUTPUT TRISTATE ;
    USE SIGNAL ;
    PORT
      LAYER met2 ;
        RECT 415.470 736.000 415.750 740.000 ;
    END
  END la_oenb[31]
  PIN la_oenb[32]
    DIRECTION OUTPUT TRISTATE ;
    USE SIGNAL ;
    PORT
      LAYER met2 ;
        RECT 428.810 736.000 429.090 740.000 ;
    END
  END la_oenb[32]
  PIN la_oenb[33]
    DIRECTION OUTPUT TRISTATE ;
    USE SIGNAL ;
    PORT
      LAYER met2 ;
        RECT 441.690 736.000 441.970 740.000 ;
    END
  END la_oenb[33]
  PIN la_oenb[34]
    DIRECTION OUTPUT TRISTATE ;
    USE SIGNAL ;
    PORT
      LAYER met2 ;
        RECT 454.570 736.000 454.850 740.000 ;
    END
  END la_oenb[34]
  PIN la_oenb[35]
    DIRECTION OUTPUT TRISTATE ;
    USE SIGNAL ;
    PORT
      LAYER met2 ;
        RECT 467.910 736.000 468.190 740.000 ;
    END
  END la_oenb[35]
  PIN la_oenb[36]
    DIRECTION OUTPUT TRISTATE ;
    USE SIGNAL ;
    PORT
      LAYER met2 ;
        RECT 480.790 736.000 481.070 740.000 ;
    END
  END la_oenb[36]
  PIN la_oenb[37]
    DIRECTION OUTPUT TRISTATE ;
    USE SIGNAL ;
    PORT
      LAYER met2 ;
        RECT 494.130 736.000 494.410 740.000 ;
    END
  END la_oenb[37]
  PIN la_oenb[38]
    DIRECTION OUTPUT TRISTATE ;
    USE SIGNAL ;
    PORT
      LAYER met2 ;
        RECT 507.010 736.000 507.290 740.000 ;
    END
  END la_oenb[38]
  PIN la_oenb[39]
    DIRECTION OUTPUT TRISTATE ;
    USE SIGNAL ;
    PORT
      LAYER met2 ;
        RECT 519.890 736.000 520.170 740.000 ;
    END
  END la_oenb[39]
  PIN la_oenb[3]
    DIRECTION OUTPUT TRISTATE ;
    USE SIGNAL ;
    PORT
      LAYER met2 ;
        RECT 50.230 736.000 50.510 740.000 ;
    END
  END la_oenb[3]
  PIN la_oenb[40]
    DIRECTION OUTPUT TRISTATE ;
    USE SIGNAL ;
    PORT
      LAYER met2 ;
        RECT 533.230 736.000 533.510 740.000 ;
    END
  END la_oenb[40]
  PIN la_oenb[41]
    DIRECTION OUTPUT TRISTATE ;
    USE SIGNAL ;
    PORT
      LAYER met2 ;
        RECT 546.110 736.000 546.390 740.000 ;
    END
  END la_oenb[41]
  PIN la_oenb[42]
    DIRECTION OUTPUT TRISTATE ;
    USE SIGNAL ;
    PORT
      LAYER met2 ;
        RECT 558.990 736.000 559.270 740.000 ;
    END
  END la_oenb[42]
  PIN la_oenb[43]
    DIRECTION OUTPUT TRISTATE ;
    USE SIGNAL ;
    PORT
      LAYER met2 ;
        RECT 572.330 736.000 572.610 740.000 ;
    END
  END la_oenb[43]
  PIN la_oenb[44]
    DIRECTION OUTPUT TRISTATE ;
    USE SIGNAL ;
    PORT
      LAYER met2 ;
        RECT 585.210 736.000 585.490 740.000 ;
    END
  END la_oenb[44]
  PIN la_oenb[45]
    DIRECTION OUTPUT TRISTATE ;
    USE SIGNAL ;
    PORT
      LAYER met2 ;
        RECT 598.550 736.000 598.830 740.000 ;
    END
  END la_oenb[45]
  PIN la_oenb[46]
    DIRECTION OUTPUT TRISTATE ;
    USE SIGNAL ;
    PORT
      LAYER met2 ;
        RECT 611.430 736.000 611.710 740.000 ;
    END
  END la_oenb[46]
  PIN la_oenb[47]
    DIRECTION OUTPUT TRISTATE ;
    USE SIGNAL ;
    PORT
      LAYER met2 ;
        RECT 624.310 736.000 624.590 740.000 ;
    END
  END la_oenb[47]
  PIN la_oenb[48]
    DIRECTION OUTPUT TRISTATE ;
    USE SIGNAL ;
    PORT
      LAYER met2 ;
        RECT 637.650 736.000 637.930 740.000 ;
    END
  END la_oenb[48]
  PIN la_oenb[49]
    DIRECTION OUTPUT TRISTATE ;
    USE SIGNAL ;
    PORT
      LAYER met2 ;
        RECT 650.530 736.000 650.810 740.000 ;
    END
  END la_oenb[49]
  PIN la_oenb[4]
    DIRECTION OUTPUT TRISTATE ;
    USE SIGNAL ;
    PORT
      LAYER met2 ;
        RECT 63.110 736.000 63.390 740.000 ;
    END
  END la_oenb[4]
  PIN la_oenb[50]
    DIRECTION OUTPUT TRISTATE ;
    USE SIGNAL ;
    PORT
      LAYER met2 ;
        RECT 663.410 736.000 663.690 740.000 ;
    END
  END la_oenb[50]
  PIN la_oenb[51]
    DIRECTION OUTPUT TRISTATE ;
    USE SIGNAL ;
    PORT
      LAYER met2 ;
        RECT 676.750 736.000 677.030 740.000 ;
    END
  END la_oenb[51]
  PIN la_oenb[52]
    DIRECTION OUTPUT TRISTATE ;
    USE SIGNAL ;
    PORT
      LAYER met2 ;
        RECT 689.630 736.000 689.910 740.000 ;
    END
  END la_oenb[52]
  PIN la_oenb[53]
    DIRECTION OUTPUT TRISTATE ;
    USE SIGNAL ;
    PORT
      LAYER met2 ;
        RECT 702.510 736.000 702.790 740.000 ;
    END
  END la_oenb[53]
  PIN la_oenb[54]
    DIRECTION OUTPUT TRISTATE ;
    USE SIGNAL ;
    PORT
      LAYER met2 ;
        RECT 715.850 736.000 716.130 740.000 ;
    END
  END la_oenb[54]
  PIN la_oenb[55]
    DIRECTION OUTPUT TRISTATE ;
    USE SIGNAL ;
    PORT
      LAYER met2 ;
        RECT 728.730 736.000 729.010 740.000 ;
    END
  END la_oenb[55]
  PIN la_oenb[56]
    DIRECTION OUTPUT TRISTATE ;
    USE SIGNAL ;
    PORT
      LAYER met2 ;
        RECT 742.070 736.000 742.350 740.000 ;
    END
  END la_oenb[56]
  PIN la_oenb[57]
    DIRECTION OUTPUT TRISTATE ;
    USE SIGNAL ;
    PORT
      LAYER met2 ;
        RECT 754.950 736.000 755.230 740.000 ;
    END
  END la_oenb[57]
  PIN la_oenb[58]
    DIRECTION OUTPUT TRISTATE ;
    USE SIGNAL ;
    PORT
      LAYER met2 ;
        RECT 767.830 736.000 768.110 740.000 ;
    END
  END la_oenb[58]
  PIN la_oenb[59]
    DIRECTION OUTPUT TRISTATE ;
    USE SIGNAL ;
    PORT
      LAYER met2 ;
        RECT 781.170 736.000 781.450 740.000 ;
    END
  END la_oenb[59]
  PIN la_oenb[5]
    DIRECTION OUTPUT TRISTATE ;
    USE SIGNAL ;
    PORT
      LAYER met2 ;
        RECT 76.450 736.000 76.730 740.000 ;
    END
  END la_oenb[5]
  PIN la_oenb[60]
    DIRECTION OUTPUT TRISTATE ;
    USE SIGNAL ;
    PORT
      LAYER met2 ;
        RECT 794.050 736.000 794.330 740.000 ;
    END
  END la_oenb[60]
  PIN la_oenb[61]
    DIRECTION OUTPUT TRISTATE ;
    USE SIGNAL ;
    PORT
      LAYER met2 ;
        RECT 806.930 736.000 807.210 740.000 ;
    END
  END la_oenb[61]
  PIN la_oenb[62]
    DIRECTION OUTPUT TRISTATE ;
    USE SIGNAL ;
    PORT
      LAYER met2 ;
        RECT 820.270 736.000 820.550 740.000 ;
    END
  END la_oenb[62]
  PIN la_oenb[63]
    DIRECTION OUTPUT TRISTATE ;
    USE SIGNAL ;
    PORT
      LAYER met2 ;
        RECT 833.150 736.000 833.430 740.000 ;
    END
  END la_oenb[63]
  PIN la_oenb[64]
    DIRECTION OUTPUT TRISTATE ;
    USE SIGNAL ;
    PORT
      LAYER met2 ;
        RECT 846.490 736.000 846.770 740.000 ;
    END
  END la_oenb[64]
  PIN la_oenb[65]
    DIRECTION OUTPUT TRISTATE ;
    USE SIGNAL ;
    PORT
      LAYER met2 ;
        RECT 859.370 736.000 859.650 740.000 ;
    END
  END la_oenb[65]
  PIN la_oenb[66]
    DIRECTION OUTPUT TRISTATE ;
    USE SIGNAL ;
    PORT
      LAYER met2 ;
        RECT 872.250 736.000 872.530 740.000 ;
    END
  END la_oenb[66]
  PIN la_oenb[67]
    DIRECTION OUTPUT TRISTATE ;
    USE SIGNAL ;
    PORT
      LAYER met2 ;
        RECT 885.590 736.000 885.870 740.000 ;
    END
  END la_oenb[67]
  PIN la_oenb[68]
    DIRECTION OUTPUT TRISTATE ;
    USE SIGNAL ;
    PORT
      LAYER met2 ;
        RECT 898.470 736.000 898.750 740.000 ;
    END
  END la_oenb[68]
  PIN la_oenb[69]
    DIRECTION OUTPUT TRISTATE ;
    USE SIGNAL ;
    PORT
      LAYER met2 ;
        RECT 911.350 736.000 911.630 740.000 ;
    END
  END la_oenb[69]
  PIN la_oenb[6]
    DIRECTION OUTPUT TRISTATE ;
    USE SIGNAL ;
    PORT
      LAYER met2 ;
        RECT 89.330 736.000 89.610 740.000 ;
    END
  END la_oenb[6]
  PIN la_oenb[70]
    DIRECTION OUTPUT TRISTATE ;
    USE SIGNAL ;
    PORT
      LAYER met2 ;
        RECT 924.690 736.000 924.970 740.000 ;
    END
  END la_oenb[70]
  PIN la_oenb[71]
    DIRECTION OUTPUT TRISTATE ;
    USE SIGNAL ;
    PORT
      LAYER met2 ;
        RECT 937.570 736.000 937.850 740.000 ;
    END
  END la_oenb[71]
  PIN la_oenb[72]
    DIRECTION OUTPUT TRISTATE ;
    USE SIGNAL ;
    PORT
      LAYER met2 ;
        RECT 950.910 736.000 951.190 740.000 ;
    END
  END la_oenb[72]
  PIN la_oenb[73]
    DIRECTION OUTPUT TRISTATE ;
    USE SIGNAL ;
    PORT
      LAYER met2 ;
        RECT 963.790 736.000 964.070 740.000 ;
    END
  END la_oenb[73]
  PIN la_oenb[74]
    DIRECTION OUTPUT TRISTATE ;
    USE SIGNAL ;
    PORT
      LAYER met2 ;
        RECT 976.670 736.000 976.950 740.000 ;
    END
  END la_oenb[74]
  PIN la_oenb[75]
    DIRECTION OUTPUT TRISTATE ;
    USE SIGNAL ;
    PORT
      LAYER met2 ;
        RECT 990.010 736.000 990.290 740.000 ;
    END
  END la_oenb[75]
  PIN la_oenb[76]
    DIRECTION OUTPUT TRISTATE ;
    USE SIGNAL ;
    PORT
      LAYER met2 ;
        RECT 1002.890 736.000 1003.170 740.000 ;
    END
  END la_oenb[76]
  PIN la_oenb[77]
    DIRECTION OUTPUT TRISTATE ;
    USE SIGNAL ;
    PORT
      LAYER met2 ;
        RECT 1015.770 736.000 1016.050 740.000 ;
    END
  END la_oenb[77]
  PIN la_oenb[78]
    DIRECTION OUTPUT TRISTATE ;
    USE SIGNAL ;
    PORT
      LAYER met2 ;
        RECT 1029.110 736.000 1029.390 740.000 ;
    END
  END la_oenb[78]
  PIN la_oenb[79]
    DIRECTION OUTPUT TRISTATE ;
    USE SIGNAL ;
    PORT
      LAYER met2 ;
        RECT 1041.990 736.000 1042.270 740.000 ;
    END
  END la_oenb[79]
  PIN la_oenb[7]
    DIRECTION OUTPUT TRISTATE ;
    USE SIGNAL ;
    PORT
      LAYER met2 ;
        RECT 102.210 736.000 102.490 740.000 ;
    END
  END la_oenb[7]
  PIN la_oenb[80]
    DIRECTION OUTPUT TRISTATE ;
    USE SIGNAL ;
    PORT
      LAYER met2 ;
        RECT 1055.330 736.000 1055.610 740.000 ;
    END
  END la_oenb[80]
  PIN la_oenb[81]
    DIRECTION OUTPUT TRISTATE ;
    USE SIGNAL ;
    PORT
      LAYER met2 ;
        RECT 1068.210 736.000 1068.490 740.000 ;
    END
  END la_oenb[81]
  PIN la_oenb[82]
    DIRECTION OUTPUT TRISTATE ;
    USE SIGNAL ;
    PORT
      LAYER met2 ;
        RECT 1081.090 736.000 1081.370 740.000 ;
    END
  END la_oenb[82]
  PIN la_oenb[83]
    DIRECTION OUTPUT TRISTATE ;
    USE SIGNAL ;
    PORT
      LAYER met2 ;
        RECT 1094.430 736.000 1094.710 740.000 ;
    END
  END la_oenb[83]
  PIN la_oenb[84]
    DIRECTION OUTPUT TRISTATE ;
    USE SIGNAL ;
    PORT
      LAYER met2 ;
        RECT 1107.310 736.000 1107.590 740.000 ;
    END
  END la_oenb[84]
  PIN la_oenb[85]
    DIRECTION OUTPUT TRISTATE ;
    USE SIGNAL ;
    PORT
      LAYER met2 ;
        RECT 1120.190 736.000 1120.470 740.000 ;
    END
  END la_oenb[85]
  PIN la_oenb[86]
    DIRECTION OUTPUT TRISTATE ;
    USE SIGNAL ;
    PORT
      LAYER met2 ;
        RECT 1133.530 736.000 1133.810 740.000 ;
    END
  END la_oenb[86]
  PIN la_oenb[87]
    DIRECTION OUTPUT TRISTATE ;
    USE SIGNAL ;
    PORT
      LAYER met2 ;
        RECT 1146.410 736.000 1146.690 740.000 ;
    END
  END la_oenb[87]
  PIN la_oenb[88]
    DIRECTION OUTPUT TRISTATE ;
    USE SIGNAL ;
    PORT
      LAYER met2 ;
        RECT 1159.750 736.000 1160.030 740.000 ;
    END
  END la_oenb[88]
  PIN la_oenb[89]
    DIRECTION OUTPUT TRISTATE ;
    USE SIGNAL ;
    PORT
      LAYER met2 ;
        RECT 1172.630 736.000 1172.910 740.000 ;
    END
  END la_oenb[89]
  PIN la_oenb[8]
    DIRECTION OUTPUT TRISTATE ;
    USE SIGNAL ;
    PORT
      LAYER met2 ;
        RECT 115.550 736.000 115.830 740.000 ;
    END
  END la_oenb[8]
  PIN la_oenb[90]
    DIRECTION OUTPUT TRISTATE ;
    USE SIGNAL ;
    PORT
      LAYER met2 ;
        RECT 1185.510 736.000 1185.790 740.000 ;
    END
  END la_oenb[90]
  PIN la_oenb[91]
    DIRECTION OUTPUT TRISTATE ;
    USE SIGNAL ;
    PORT
      LAYER met2 ;
        RECT 1198.850 736.000 1199.130 740.000 ;
    END
  END la_oenb[91]
  PIN la_oenb[92]
    DIRECTION OUTPUT TRISTATE ;
    USE SIGNAL ;
    PORT
      LAYER met2 ;
        RECT 1211.730 736.000 1212.010 740.000 ;
    END
  END la_oenb[92]
  PIN la_oenb[93]
    DIRECTION OUTPUT TRISTATE ;
    USE SIGNAL ;
    PORT
      LAYER met2 ;
        RECT 1224.610 736.000 1224.890 740.000 ;
    END
  END la_oenb[93]
  PIN la_oenb[94]
    DIRECTION OUTPUT TRISTATE ;
    USE SIGNAL ;
    PORT
      LAYER met2 ;
        RECT 1237.950 736.000 1238.230 740.000 ;
    END
  END la_oenb[94]
  PIN la_oenb[95]
    DIRECTION OUTPUT TRISTATE ;
    USE SIGNAL ;
    PORT
      LAYER met2 ;
        RECT 1250.830 736.000 1251.110 740.000 ;
    END
  END la_oenb[95]
  PIN la_oenb[96]
    DIRECTION OUTPUT TRISTATE ;
    USE SIGNAL ;
    PORT
      LAYER met2 ;
        RECT 1263.710 736.000 1263.990 740.000 ;
    END
  END la_oenb[96]
  PIN la_oenb[97]
    DIRECTION OUTPUT TRISTATE ;
    USE SIGNAL ;
    PORT
      LAYER met2 ;
        RECT 1277.050 736.000 1277.330 740.000 ;
    END
  END la_oenb[97]
  PIN la_oenb[98]
    DIRECTION OUTPUT TRISTATE ;
    USE SIGNAL ;
    PORT
      LAYER met2 ;
        RECT 1289.930 736.000 1290.210 740.000 ;
    END
  END la_oenb[98]
  PIN la_oenb[99]
    DIRECTION OUTPUT TRISTATE ;
    USE SIGNAL ;
    PORT
      LAYER met2 ;
        RECT 1303.270 736.000 1303.550 740.000 ;
    END
  END la_oenb[99]
  PIN la_oenb[9]
    DIRECTION OUTPUT TRISTATE ;
    USE SIGNAL ;
    PORT
      LAYER met2 ;
        RECT 128.430 736.000 128.710 740.000 ;
    END
  END la_oenb[9]
  PIN la_output[0]
    DIRECTION OUTPUT TRISTATE ;
    USE SIGNAL ;
    PORT
      LAYER met2 ;
        RECT 14.350 736.000 14.630 740.000 ;
    END
  END la_output[0]
  PIN la_output[100]
    DIRECTION OUTPUT TRISTATE ;
    USE SIGNAL ;
    PORT
      LAYER met2 ;
        RECT 1319.370 736.000 1319.650 740.000 ;
    END
  END la_output[100]
  PIN la_output[101]
    DIRECTION OUTPUT TRISTATE ;
    USE SIGNAL ;
    PORT
      LAYER met2 ;
        RECT 1332.250 736.000 1332.530 740.000 ;
    END
  END la_output[101]
  PIN la_output[102]
    DIRECTION OUTPUT TRISTATE ;
    USE SIGNAL ;
    PORT
      LAYER met2 ;
        RECT 1345.590 736.000 1345.870 740.000 ;
    END
  END la_output[102]
  PIN la_output[103]
    DIRECTION OUTPUT TRISTATE ;
    USE SIGNAL ;
    PORT
      LAYER met2 ;
        RECT 1358.470 736.000 1358.750 740.000 ;
    END
  END la_output[103]
  PIN la_output[104]
    DIRECTION OUTPUT TRISTATE ;
    USE SIGNAL ;
    PORT
      LAYER met2 ;
        RECT 1371.810 736.000 1372.090 740.000 ;
    END
  END la_output[104]
  PIN la_output[105]
    DIRECTION OUTPUT TRISTATE ;
    USE SIGNAL ;
    PORT
      LAYER met2 ;
        RECT 1384.690 736.000 1384.970 740.000 ;
    END
  END la_output[105]
  PIN la_output[106]
    DIRECTION OUTPUT TRISTATE ;
    USE SIGNAL ;
    PORT
      LAYER met2 ;
        RECT 1397.570 736.000 1397.850 740.000 ;
    END
  END la_output[106]
  PIN la_output[107]
    DIRECTION OUTPUT TRISTATE ;
    USE SIGNAL ;
    PORT
      LAYER met2 ;
        RECT 1410.910 736.000 1411.190 740.000 ;
    END
  END la_output[107]
  PIN la_output[108]
    DIRECTION OUTPUT TRISTATE ;
    USE SIGNAL ;
    PORT
      LAYER met2 ;
        RECT 1423.790 736.000 1424.070 740.000 ;
    END
  END la_output[108]
  PIN la_output[109]
    DIRECTION OUTPUT TRISTATE ;
    USE SIGNAL ;
    PORT
      LAYER met2 ;
        RECT 1436.670 736.000 1436.950 740.000 ;
    END
  END la_output[109]
  PIN la_output[10]
    DIRECTION OUTPUT TRISTATE ;
    USE SIGNAL ;
    PORT
      LAYER met2 ;
        RECT 144.990 736.000 145.270 740.000 ;
    END
  END la_output[10]
  PIN la_output[110]
    DIRECTION OUTPUT TRISTATE ;
    USE SIGNAL ;
    PORT
      LAYER met2 ;
        RECT 1450.010 736.000 1450.290 740.000 ;
    END
  END la_output[110]
  PIN la_output[111]
    DIRECTION OUTPUT TRISTATE ;
    USE SIGNAL ;
    PORT
      LAYER met2 ;
        RECT 1462.890 736.000 1463.170 740.000 ;
    END
  END la_output[111]
  PIN la_output[112]
    DIRECTION OUTPUT TRISTATE ;
    USE SIGNAL ;
    PORT
      LAYER met2 ;
        RECT 1476.230 736.000 1476.510 740.000 ;
    END
  END la_output[112]
  PIN la_output[113]
    DIRECTION OUTPUT TRISTATE ;
    USE SIGNAL ;
    PORT
      LAYER met2 ;
        RECT 1489.110 736.000 1489.390 740.000 ;
    END
  END la_output[113]
  PIN la_output[114]
    DIRECTION OUTPUT TRISTATE ;
    USE SIGNAL ;
    PORT
      LAYER met2 ;
        RECT 1501.990 736.000 1502.270 740.000 ;
    END
  END la_output[114]
  PIN la_output[115]
    DIRECTION OUTPUT TRISTATE ;
    USE SIGNAL ;
    PORT
      LAYER met2 ;
        RECT 1515.330 736.000 1515.610 740.000 ;
    END
  END la_output[115]
  PIN la_output[116]
    DIRECTION OUTPUT TRISTATE ;
    USE SIGNAL ;
    PORT
      LAYER met2 ;
        RECT 1528.210 736.000 1528.490 740.000 ;
    END
  END la_output[116]
  PIN la_output[117]
    DIRECTION OUTPUT TRISTATE ;
    USE SIGNAL ;
    PORT
      LAYER met2 ;
        RECT 1541.090 736.000 1541.370 740.000 ;
    END
  END la_output[117]
  PIN la_output[118]
    DIRECTION OUTPUT TRISTATE ;
    USE SIGNAL ;
    PORT
      LAYER met2 ;
        RECT 1554.430 736.000 1554.710 740.000 ;
    END
  END la_output[118]
  PIN la_output[119]
    DIRECTION OUTPUT TRISTATE ;
    USE SIGNAL ;
    PORT
      LAYER met2 ;
        RECT 1567.310 736.000 1567.590 740.000 ;
    END
  END la_output[119]
  PIN la_output[11]
    DIRECTION OUTPUT TRISTATE ;
    USE SIGNAL ;
    PORT
      LAYER met2 ;
        RECT 157.870 736.000 158.150 740.000 ;
    END
  END la_output[11]
  PIN la_output[120]
    DIRECTION OUTPUT TRISTATE ;
    USE SIGNAL ;
    PORT
      LAYER met2 ;
        RECT 1580.650 736.000 1580.930 740.000 ;
    END
  END la_output[120]
  PIN la_output[121]
    DIRECTION OUTPUT TRISTATE ;
    USE SIGNAL ;
    PORT
      LAYER met2 ;
        RECT 1593.530 736.000 1593.810 740.000 ;
    END
  END la_output[121]
  PIN la_output[122]
    DIRECTION OUTPUT TRISTATE ;
    USE SIGNAL ;
    PORT
      LAYER met2 ;
        RECT 1606.410 736.000 1606.690 740.000 ;
    END
  END la_output[122]
  PIN la_output[123]
    DIRECTION OUTPUT TRISTATE ;
    USE SIGNAL ;
    PORT
      LAYER met2 ;
        RECT 1619.750 736.000 1620.030 740.000 ;
    END
  END la_output[123]
  PIN la_output[124]
    DIRECTION OUTPUT TRISTATE ;
    USE SIGNAL ;
    PORT
      LAYER met2 ;
        RECT 1632.630 736.000 1632.910 740.000 ;
    END
  END la_output[124]
  PIN la_output[125]
    DIRECTION OUTPUT TRISTATE ;
    USE SIGNAL ;
    PORT
      LAYER met2 ;
        RECT 1645.510 736.000 1645.790 740.000 ;
    END
  END la_output[125]
  PIN la_output[126]
    DIRECTION OUTPUT TRISTATE ;
    USE SIGNAL ;
    PORT
      LAYER met2 ;
        RECT 1658.850 736.000 1659.130 740.000 ;
    END
  END la_output[126]
  PIN la_output[127]
    DIRECTION OUTPUT TRISTATE ;
    USE SIGNAL ;
    PORT
      LAYER met2 ;
        RECT 1671.730 736.000 1672.010 740.000 ;
    END
  END la_output[127]
  PIN la_output[12]
    DIRECTION OUTPUT TRISTATE ;
    USE SIGNAL ;
    PORT
      LAYER met2 ;
        RECT 170.750 736.000 171.030 740.000 ;
    END
  END la_output[12]
  PIN la_output[13]
    DIRECTION OUTPUT TRISTATE ;
    USE SIGNAL ;
    PORT
      LAYER met2 ;
        RECT 184.090 736.000 184.370 740.000 ;
    END
  END la_output[13]
  PIN la_output[14]
    DIRECTION OUTPUT TRISTATE ;
    USE SIGNAL ;
    PORT
      LAYER met2 ;
        RECT 196.970 736.000 197.250 740.000 ;
    END
  END la_output[14]
  PIN la_output[15]
    DIRECTION OUTPUT TRISTATE ;
    USE SIGNAL ;
    PORT
      LAYER met2 ;
        RECT 209.850 736.000 210.130 740.000 ;
    END
  END la_output[15]
  PIN la_output[16]
    DIRECTION OUTPUT TRISTATE ;
    USE SIGNAL ;
    PORT
      LAYER met2 ;
        RECT 223.190 736.000 223.470 740.000 ;
    END
  END la_output[16]
  PIN la_output[17]
    DIRECTION OUTPUT TRISTATE ;
    USE SIGNAL ;
    PORT
      LAYER met2 ;
        RECT 236.070 736.000 236.350 740.000 ;
    END
  END la_output[17]
  PIN la_output[18]
    DIRECTION OUTPUT TRISTATE ;
    USE SIGNAL ;
    PORT
      LAYER met2 ;
        RECT 249.410 736.000 249.690 740.000 ;
    END
  END la_output[18]
  PIN la_output[19]
    DIRECTION OUTPUT TRISTATE ;
    USE SIGNAL ;
    PORT
      LAYER met2 ;
        RECT 262.290 736.000 262.570 740.000 ;
    END
  END la_output[19]
  PIN la_output[1]
    DIRECTION OUTPUT TRISTATE ;
    USE SIGNAL ;
    PORT
      LAYER met2 ;
        RECT 27.230 736.000 27.510 740.000 ;
    END
  END la_output[1]
  PIN la_output[20]
    DIRECTION OUTPUT TRISTATE ;
    USE SIGNAL ;
    PORT
      LAYER met2 ;
        RECT 275.170 736.000 275.450 740.000 ;
    END
  END la_output[20]
  PIN la_output[21]
    DIRECTION OUTPUT TRISTATE ;
    USE SIGNAL ;
    PORT
      LAYER met2 ;
        RECT 288.510 736.000 288.790 740.000 ;
    END
  END la_output[21]
  PIN la_output[22]
    DIRECTION OUTPUT TRISTATE ;
    USE SIGNAL ;
    PORT
      LAYER met2 ;
        RECT 301.390 736.000 301.670 740.000 ;
    END
  END la_output[22]
  PIN la_output[23]
    DIRECTION OUTPUT TRISTATE ;
    USE SIGNAL ;
    PORT
      LAYER met2 ;
        RECT 314.270 736.000 314.550 740.000 ;
    END
  END la_output[23]
  PIN la_output[24]
    DIRECTION OUTPUT TRISTATE ;
    USE SIGNAL ;
    PORT
      LAYER met2 ;
        RECT 327.610 736.000 327.890 740.000 ;
    END
  END la_output[24]
  PIN la_output[25]
    DIRECTION OUTPUT TRISTATE ;
    USE SIGNAL ;
    PORT
      LAYER met2 ;
        RECT 340.490 736.000 340.770 740.000 ;
    END
  END la_output[25]
  PIN la_output[26]
    DIRECTION OUTPUT TRISTATE ;
    USE SIGNAL ;
    PORT
      LAYER met2 ;
        RECT 353.830 736.000 354.110 740.000 ;
    END
  END la_output[26]
  PIN la_output[27]
    DIRECTION OUTPUT TRISTATE ;
    USE SIGNAL ;
    PORT
      LAYER met2 ;
        RECT 366.710 736.000 366.990 740.000 ;
    END
  END la_output[27]
  PIN la_output[28]
    DIRECTION OUTPUT TRISTATE ;
    USE SIGNAL ;
    PORT
      LAYER met2 ;
        RECT 379.590 736.000 379.870 740.000 ;
    END
  END la_output[28]
  PIN la_output[29]
    DIRECTION OUTPUT TRISTATE ;
    USE SIGNAL ;
    PORT
      LAYER met2 ;
        RECT 392.930 736.000 393.210 740.000 ;
    END
  END la_output[29]
  PIN la_output[2]
    DIRECTION OUTPUT TRISTATE ;
    USE SIGNAL ;
    PORT
      LAYER met2 ;
        RECT 40.570 736.000 40.850 740.000 ;
    END
  END la_output[2]
  PIN la_output[30]
    DIRECTION OUTPUT TRISTATE ;
    USE SIGNAL ;
    PORT
      LAYER met2 ;
        RECT 405.810 736.000 406.090 740.000 ;
    END
  END la_output[30]
  PIN la_output[31]
    DIRECTION OUTPUT TRISTATE ;
    USE SIGNAL ;
    PORT
      LAYER met2 ;
        RECT 418.690 736.000 418.970 740.000 ;
    END
  END la_output[31]
  PIN la_output[32]
    DIRECTION OUTPUT TRISTATE ;
    USE SIGNAL ;
    PORT
      LAYER met2 ;
        RECT 432.030 736.000 432.310 740.000 ;
    END
  END la_output[32]
  PIN la_output[33]
    DIRECTION OUTPUT TRISTATE ;
    USE SIGNAL ;
    PORT
      LAYER met2 ;
        RECT 444.910 736.000 445.190 740.000 ;
    END
  END la_output[33]
  PIN la_output[34]
    DIRECTION OUTPUT TRISTATE ;
    USE SIGNAL ;
    PORT
      LAYER met2 ;
        RECT 458.250 736.000 458.530 740.000 ;
    END
  END la_output[34]
  PIN la_output[35]
    DIRECTION OUTPUT TRISTATE ;
    USE SIGNAL ;
    PORT
      LAYER met2 ;
        RECT 471.130 736.000 471.410 740.000 ;
    END
  END la_output[35]
  PIN la_output[36]
    DIRECTION OUTPUT TRISTATE ;
    USE SIGNAL ;
    PORT
      LAYER met2 ;
        RECT 484.010 736.000 484.290 740.000 ;
    END
  END la_output[36]
  PIN la_output[37]
    DIRECTION OUTPUT TRISTATE ;
    USE SIGNAL ;
    PORT
      LAYER met2 ;
        RECT 497.350 736.000 497.630 740.000 ;
    END
  END la_output[37]
  PIN la_output[38]
    DIRECTION OUTPUT TRISTATE ;
    USE SIGNAL ;
    PORT
      LAYER met2 ;
        RECT 510.230 736.000 510.510 740.000 ;
    END
  END la_output[38]
  PIN la_output[39]
    DIRECTION OUTPUT TRISTATE ;
    USE SIGNAL ;
    PORT
      LAYER met2 ;
        RECT 523.110 736.000 523.390 740.000 ;
    END
  END la_output[39]
  PIN la_output[3]
    DIRECTION OUTPUT TRISTATE ;
    USE SIGNAL ;
    PORT
      LAYER met2 ;
        RECT 53.450 736.000 53.730 740.000 ;
    END
  END la_output[3]
  PIN la_output[40]
    DIRECTION OUTPUT TRISTATE ;
    USE SIGNAL ;
    PORT
      LAYER met2 ;
        RECT 536.450 736.000 536.730 740.000 ;
    END
  END la_output[40]
  PIN la_output[41]
    DIRECTION OUTPUT TRISTATE ;
    USE SIGNAL ;
    PORT
      LAYER met2 ;
        RECT 549.330 736.000 549.610 740.000 ;
    END
  END la_output[41]
  PIN la_output[42]
    DIRECTION OUTPUT TRISTATE ;
    USE SIGNAL ;
    PORT
      LAYER met2 ;
        RECT 562.210 736.000 562.490 740.000 ;
    END
  END la_output[42]
  PIN la_output[43]
    DIRECTION OUTPUT TRISTATE ;
    USE SIGNAL ;
    PORT
      LAYER met2 ;
        RECT 575.550 736.000 575.830 740.000 ;
    END
  END la_output[43]
  PIN la_output[44]
    DIRECTION OUTPUT TRISTATE ;
    USE SIGNAL ;
    PORT
      LAYER met2 ;
        RECT 588.430 736.000 588.710 740.000 ;
    END
  END la_output[44]
  PIN la_output[45]
    DIRECTION OUTPUT TRISTATE ;
    USE SIGNAL ;
    PORT
      LAYER met2 ;
        RECT 601.770 736.000 602.050 740.000 ;
    END
  END la_output[45]
  PIN la_output[46]
    DIRECTION OUTPUT TRISTATE ;
    USE SIGNAL ;
    PORT
      LAYER met2 ;
        RECT 614.650 736.000 614.930 740.000 ;
    END
  END la_output[46]
  PIN la_output[47]
    DIRECTION OUTPUT TRISTATE ;
    USE SIGNAL ;
    PORT
      LAYER met2 ;
        RECT 627.530 736.000 627.810 740.000 ;
    END
  END la_output[47]
  PIN la_output[48]
    DIRECTION OUTPUT TRISTATE ;
    USE SIGNAL ;
    PORT
      LAYER met2 ;
        RECT 640.870 736.000 641.150 740.000 ;
    END
  END la_output[48]
  PIN la_output[49]
    DIRECTION OUTPUT TRISTATE ;
    USE SIGNAL ;
    PORT
      LAYER met2 ;
        RECT 653.750 736.000 654.030 740.000 ;
    END
  END la_output[49]
  PIN la_output[4]
    DIRECTION OUTPUT TRISTATE ;
    USE SIGNAL ;
    PORT
      LAYER met2 ;
        RECT 66.330 736.000 66.610 740.000 ;
    END
  END la_output[4]
  PIN la_output[50]
    DIRECTION OUTPUT TRISTATE ;
    USE SIGNAL ;
    PORT
      LAYER met2 ;
        RECT 666.630 736.000 666.910 740.000 ;
    END
  END la_output[50]
  PIN la_output[51]
    DIRECTION OUTPUT TRISTATE ;
    USE SIGNAL ;
    PORT
      LAYER met2 ;
        RECT 679.970 736.000 680.250 740.000 ;
    END
  END la_output[51]
  PIN la_output[52]
    DIRECTION OUTPUT TRISTATE ;
    USE SIGNAL ;
    PORT
      LAYER met2 ;
        RECT 692.850 736.000 693.130 740.000 ;
    END
  END la_output[52]
  PIN la_output[53]
    DIRECTION OUTPUT TRISTATE ;
    USE SIGNAL ;
    PORT
      LAYER met2 ;
        RECT 706.190 736.000 706.470 740.000 ;
    END
  END la_output[53]
  PIN la_output[54]
    DIRECTION OUTPUT TRISTATE ;
    USE SIGNAL ;
    PORT
      LAYER met2 ;
        RECT 719.070 736.000 719.350 740.000 ;
    END
  END la_output[54]
  PIN la_output[55]
    DIRECTION OUTPUT TRISTATE ;
    USE SIGNAL ;
    PORT
      LAYER met2 ;
        RECT 731.950 736.000 732.230 740.000 ;
    END
  END la_output[55]
  PIN la_output[56]
    DIRECTION OUTPUT TRISTATE ;
    USE SIGNAL ;
    PORT
      LAYER met2 ;
        RECT 745.290 736.000 745.570 740.000 ;
    END
  END la_output[56]
  PIN la_output[57]
    DIRECTION OUTPUT TRISTATE ;
    USE SIGNAL ;
    PORT
      LAYER met2 ;
        RECT 758.170 736.000 758.450 740.000 ;
    END
  END la_output[57]
  PIN la_output[58]
    DIRECTION OUTPUT TRISTATE ;
    USE SIGNAL ;
    PORT
      LAYER met2 ;
        RECT 771.050 736.000 771.330 740.000 ;
    END
  END la_output[58]
  PIN la_output[59]
    DIRECTION OUTPUT TRISTATE ;
    USE SIGNAL ;
    PORT
      LAYER met2 ;
        RECT 784.390 736.000 784.670 740.000 ;
    END
  END la_output[59]
  PIN la_output[5]
    DIRECTION OUTPUT TRISTATE ;
    USE SIGNAL ;
    PORT
      LAYER met2 ;
        RECT 79.670 736.000 79.950 740.000 ;
    END
  END la_output[5]
  PIN la_output[60]
    DIRECTION OUTPUT TRISTATE ;
    USE SIGNAL ;
    PORT
      LAYER met2 ;
        RECT 797.270 736.000 797.550 740.000 ;
    END
  END la_output[60]
  PIN la_output[61]
    DIRECTION OUTPUT TRISTATE ;
    USE SIGNAL ;
    PORT
      LAYER met2 ;
        RECT 810.610 736.000 810.890 740.000 ;
    END
  END la_output[61]
  PIN la_output[62]
    DIRECTION OUTPUT TRISTATE ;
    USE SIGNAL ;
    PORT
      LAYER met2 ;
        RECT 823.490 736.000 823.770 740.000 ;
    END
  END la_output[62]
  PIN la_output[63]
    DIRECTION OUTPUT TRISTATE ;
    USE SIGNAL ;
    PORT
      LAYER met2 ;
        RECT 836.370 736.000 836.650 740.000 ;
    END
  END la_output[63]
  PIN la_output[64]
    DIRECTION OUTPUT TRISTATE ;
    USE SIGNAL ;
    PORT
      LAYER met2 ;
        RECT 849.710 736.000 849.990 740.000 ;
    END
  END la_output[64]
  PIN la_output[65]
    DIRECTION OUTPUT TRISTATE ;
    USE SIGNAL ;
    PORT
      LAYER met2 ;
        RECT 862.590 736.000 862.870 740.000 ;
    END
  END la_output[65]
  PIN la_output[66]
    DIRECTION OUTPUT TRISTATE ;
    USE SIGNAL ;
    PORT
      LAYER met2 ;
        RECT 875.470 736.000 875.750 740.000 ;
    END
  END la_output[66]
  PIN la_output[67]
    DIRECTION OUTPUT TRISTATE ;
    USE SIGNAL ;
    PORT
      LAYER met2 ;
        RECT 888.810 736.000 889.090 740.000 ;
    END
  END la_output[67]
  PIN la_output[68]
    DIRECTION OUTPUT TRISTATE ;
    USE SIGNAL ;
    PORT
      LAYER met2 ;
        RECT 901.690 736.000 901.970 740.000 ;
    END
  END la_output[68]
  PIN la_output[69]
    DIRECTION OUTPUT TRISTATE ;
    USE SIGNAL ;
    PORT
      LAYER met2 ;
        RECT 915.030 736.000 915.310 740.000 ;
    END
  END la_output[69]
  PIN la_output[6]
    DIRECTION OUTPUT TRISTATE ;
    USE SIGNAL ;
    PORT
      LAYER met2 ;
        RECT 92.550 736.000 92.830 740.000 ;
    END
  END la_output[6]
  PIN la_output[70]
    DIRECTION OUTPUT TRISTATE ;
    USE SIGNAL ;
    PORT
      LAYER met2 ;
        RECT 927.910 736.000 928.190 740.000 ;
    END
  END la_output[70]
  PIN la_output[71]
    DIRECTION OUTPUT TRISTATE ;
    USE SIGNAL ;
    PORT
      LAYER met2 ;
        RECT 940.790 736.000 941.070 740.000 ;
    END
  END la_output[71]
  PIN la_output[72]
    DIRECTION OUTPUT TRISTATE ;
    USE SIGNAL ;
    PORT
      LAYER met2 ;
        RECT 954.130 736.000 954.410 740.000 ;
    END
  END la_output[72]
  PIN la_output[73]
    DIRECTION OUTPUT TRISTATE ;
    USE SIGNAL ;
    PORT
      LAYER met2 ;
        RECT 967.010 736.000 967.290 740.000 ;
    END
  END la_output[73]
  PIN la_output[74]
    DIRECTION OUTPUT TRISTATE ;
    USE SIGNAL ;
    PORT
      LAYER met2 ;
        RECT 979.890 736.000 980.170 740.000 ;
    END
  END la_output[74]
  PIN la_output[75]
    DIRECTION OUTPUT TRISTATE ;
    USE SIGNAL ;
    PORT
      LAYER met2 ;
        RECT 993.230 736.000 993.510 740.000 ;
    END
  END la_output[75]
  PIN la_output[76]
    DIRECTION OUTPUT TRISTATE ;
    USE SIGNAL ;
    PORT
      LAYER met2 ;
        RECT 1006.110 736.000 1006.390 740.000 ;
    END
  END la_output[76]
  PIN la_output[77]
    DIRECTION OUTPUT TRISTATE ;
    USE SIGNAL ;
    PORT
      LAYER met2 ;
        RECT 1019.450 736.000 1019.730 740.000 ;
    END
  END la_output[77]
  PIN la_output[78]
    DIRECTION OUTPUT TRISTATE ;
    USE SIGNAL ;
    PORT
      LAYER met2 ;
        RECT 1032.330 736.000 1032.610 740.000 ;
    END
  END la_output[78]
  PIN la_output[79]
    DIRECTION OUTPUT TRISTATE ;
    USE SIGNAL ;
    PORT
      LAYER met2 ;
        RECT 1045.210 736.000 1045.490 740.000 ;
    END
  END la_output[79]
  PIN la_output[7]
    DIRECTION OUTPUT TRISTATE ;
    USE SIGNAL ;
    PORT
      LAYER met2 ;
        RECT 105.430 736.000 105.710 740.000 ;
    END
  END la_output[7]
  PIN la_output[80]
    DIRECTION OUTPUT TRISTATE ;
    USE SIGNAL ;
    PORT
      LAYER met2 ;
        RECT 1058.550 736.000 1058.830 740.000 ;
    END
  END la_output[80]
  PIN la_output[81]
    DIRECTION OUTPUT TRISTATE ;
    USE SIGNAL ;
    PORT
      LAYER met2 ;
        RECT 1071.430 736.000 1071.710 740.000 ;
    END
  END la_output[81]
  PIN la_output[82]
    DIRECTION OUTPUT TRISTATE ;
    USE SIGNAL ;
    PORT
      LAYER met2 ;
        RECT 1084.310 736.000 1084.590 740.000 ;
    END
  END la_output[82]
  PIN la_output[83]
    DIRECTION OUTPUT TRISTATE ;
    USE SIGNAL ;
    PORT
      LAYER met2 ;
        RECT 1097.650 736.000 1097.930 740.000 ;
    END
  END la_output[83]
  PIN la_output[84]
    DIRECTION OUTPUT TRISTATE ;
    USE SIGNAL ;
    PORT
      LAYER met2 ;
        RECT 1110.530 736.000 1110.810 740.000 ;
    END
  END la_output[84]
  PIN la_output[85]
    DIRECTION OUTPUT TRISTATE ;
    USE SIGNAL ;
    PORT
      LAYER met2 ;
        RECT 1123.410 736.000 1123.690 740.000 ;
    END
  END la_output[85]
  PIN la_output[86]
    DIRECTION OUTPUT TRISTATE ;
    USE SIGNAL ;
    PORT
      LAYER met2 ;
        RECT 1136.750 736.000 1137.030 740.000 ;
    END
  END la_output[86]
  PIN la_output[87]
    DIRECTION OUTPUT TRISTATE ;
    USE SIGNAL ;
    PORT
      LAYER met2 ;
        RECT 1149.630 736.000 1149.910 740.000 ;
    END
  END la_output[87]
  PIN la_output[88]
    DIRECTION OUTPUT TRISTATE ;
    USE SIGNAL ;
    PORT
      LAYER met2 ;
        RECT 1162.970 736.000 1163.250 740.000 ;
    END
  END la_output[88]
  PIN la_output[89]
    DIRECTION OUTPUT TRISTATE ;
    USE SIGNAL ;
    PORT
      LAYER met2 ;
        RECT 1175.850 736.000 1176.130 740.000 ;
    END
  END la_output[89]
  PIN la_output[8]
    DIRECTION OUTPUT TRISTATE ;
    USE SIGNAL ;
    PORT
      LAYER met2 ;
        RECT 118.770 736.000 119.050 740.000 ;
    END
  END la_output[8]
  PIN la_output[90]
    DIRECTION OUTPUT TRISTATE ;
    USE SIGNAL ;
    PORT
      LAYER met2 ;
        RECT 1188.730 736.000 1189.010 740.000 ;
    END
  END la_output[90]
  PIN la_output[91]
    DIRECTION OUTPUT TRISTATE ;
    USE SIGNAL ;
    PORT
      LAYER met2 ;
        RECT 1202.070 736.000 1202.350 740.000 ;
    END
  END la_output[91]
  PIN la_output[92]
    DIRECTION OUTPUT TRISTATE ;
    USE SIGNAL ;
    PORT
      LAYER met2 ;
        RECT 1214.950 736.000 1215.230 740.000 ;
    END
  END la_output[92]
  PIN la_output[93]
    DIRECTION OUTPUT TRISTATE ;
    USE SIGNAL ;
    PORT
      LAYER met2 ;
        RECT 1227.830 736.000 1228.110 740.000 ;
    END
  END la_output[93]
  PIN la_output[94]
    DIRECTION OUTPUT TRISTATE ;
    USE SIGNAL ;
    PORT
      LAYER met2 ;
        RECT 1241.170 736.000 1241.450 740.000 ;
    END
  END la_output[94]
  PIN la_output[95]
    DIRECTION OUTPUT TRISTATE ;
    USE SIGNAL ;
    PORT
      LAYER met2 ;
        RECT 1254.050 736.000 1254.330 740.000 ;
    END
  END la_output[95]
  PIN la_output[96]
    DIRECTION OUTPUT TRISTATE ;
    USE SIGNAL ;
    PORT
      LAYER met2 ;
        RECT 1267.390 736.000 1267.670 740.000 ;
    END
  END la_output[96]
  PIN la_output[97]
    DIRECTION OUTPUT TRISTATE ;
    USE SIGNAL ;
    PORT
      LAYER met2 ;
        RECT 1280.270 736.000 1280.550 740.000 ;
    END
  END la_output[97]
  PIN la_output[98]
    DIRECTION OUTPUT TRISTATE ;
    USE SIGNAL ;
    PORT
      LAYER met2 ;
        RECT 1293.150 736.000 1293.430 740.000 ;
    END
  END la_output[98]
  PIN la_output[99]
    DIRECTION OUTPUT TRISTATE ;
    USE SIGNAL ;
    PORT
      LAYER met2 ;
        RECT 1306.490 736.000 1306.770 740.000 ;
    END
  END la_output[99]
  PIN la_output[9]
    DIRECTION OUTPUT TRISTATE ;
    USE SIGNAL ;
    PORT
      LAYER met2 ;
        RECT 131.650 736.000 131.930 740.000 ;
    END
  END la_output[9]
  PIN mgmt_soc_dff_A[0]
    DIRECTION OUTPUT TRISTATE ;
    USE SIGNAL ;
    PORT
      LAYER met2 ;
        RECT 1632.170 0.000 1632.450 4.000 ;
    END
  END mgmt_soc_dff_A[0]
  PIN mgmt_soc_dff_A[1]
    DIRECTION OUTPUT TRISTATE ;
    USE SIGNAL ;
    PORT
      LAYER met2 ;
        RECT 1939.450 736.000 1939.730 740.000 ;
    END
  END mgmt_soc_dff_A[1]
  PIN mgmt_soc_dff_A[2]
    DIRECTION OUTPUT TRISTATE ;
    USE SIGNAL ;
    PORT
      LAYER met2 ;
        RECT 1647.810 0.000 1648.090 4.000 ;
    END
  END mgmt_soc_dff_A[2]
  PIN mgmt_soc_dff_A[3]
    DIRECTION OUTPUT TRISTATE ;
    USE SIGNAL ;
    PORT
      LAYER met3 ;
        RECT 0.000 530.440 4.000 531.040 ;
    END
  END mgmt_soc_dff_A[3]
  PIN mgmt_soc_dff_A[4]
    DIRECTION OUTPUT TRISTATE ;
    USE SIGNAL ;
    PORT
      LAYER met3 ;
        RECT 0.000 557.640 4.000 558.240 ;
    END
  END mgmt_soc_dff_A[4]
  PIN mgmt_soc_dff_A[5]
    DIRECTION OUTPUT TRISTATE ;
    USE SIGNAL ;
    PORT
      LAYER met3 ;
        RECT 1996.000 240.080 2000.000 240.680 ;
    END
  END mgmt_soc_dff_A[5]
  PIN mgmt_soc_dff_A[6]
    DIRECTION OUTPUT TRISTATE ;
    USE SIGNAL ;
    PORT
      LAYER met3 ;
        RECT 0.000 597.760 4.000 598.360 ;
    END
  END mgmt_soc_dff_A[6]
  PIN mgmt_soc_dff_A[7]
    DIRECTION OUTPUT TRISTATE ;
    USE SIGNAL ;
    PORT
      LAYER met3 ;
        RECT 0.000 611.360 4.000 611.960 ;
    END
  END mgmt_soc_dff_A[7]
  PIN mgmt_soc_dff_Di[0]
    DIRECTION OUTPUT TRISTATE ;
    USE SIGNAL ;
    PORT
      LAYER met3 ;
        RECT 1996.000 91.840 2000.000 92.440 ;
    END
  END mgmt_soc_dff_Di[0]
  PIN mgmt_soc_dff_Di[10]
    DIRECTION OUTPUT TRISTATE ;
    USE SIGNAL ;
    PORT
      LAYER met2 ;
        RECT 1961.990 736.000 1962.270 740.000 ;
    END
  END mgmt_soc_dff_Di[10]
  PIN mgmt_soc_dff_Di[11]
    DIRECTION OUTPUT TRISTATE ;
    USE SIGNAL ;
    PORT
      LAYER met3 ;
        RECT 1996.000 314.200 2000.000 314.800 ;
    END
  END mgmt_soc_dff_Di[11]
  PIN mgmt_soc_dff_Di[12]
    DIRECTION OUTPUT TRISTATE ;
    USE SIGNAL ;
    PORT
      LAYER met3 ;
        RECT 1996.000 350.920 2000.000 351.520 ;
    END
  END mgmt_soc_dff_Di[12]
  PIN mgmt_soc_dff_Di[13]
    DIRECTION OUTPUT TRISTATE ;
    USE SIGNAL ;
    PORT
      LAYER met2 ;
        RECT 1851.130 0.000 1851.410 4.000 ;
    END
  END mgmt_soc_dff_Di[13]
  PIN mgmt_soc_dff_Di[14]
    DIRECTION OUTPUT TRISTATE ;
    USE SIGNAL ;
    PORT
      LAYER met3 ;
        RECT 0.000 665.080 4.000 665.680 ;
    END
  END mgmt_soc_dff_Di[14]
  PIN mgmt_soc_dff_Di[15]
    DIRECTION OUTPUT TRISTATE ;
    USE SIGNAL ;
    PORT
      LAYER met2 ;
        RECT 1965.210 736.000 1965.490 740.000 ;
    END
  END mgmt_soc_dff_Di[15]
  PIN mgmt_soc_dff_Di[16]
    DIRECTION OUTPUT TRISTATE ;
    USE SIGNAL ;
    PORT
      LAYER met2 ;
        RECT 1866.770 0.000 1867.050 4.000 ;
    END
  END mgmt_soc_dff_Di[16]
  PIN mgmt_soc_dff_Di[17]
    DIRECTION OUTPUT TRISTATE ;
    USE SIGNAL ;
    PORT
      LAYER met3 ;
        RECT 1996.000 425.040 2000.000 425.640 ;
    END
  END mgmt_soc_dff_Di[17]
  PIN mgmt_soc_dff_Di[18]
    DIRECTION OUTPUT TRISTATE ;
    USE SIGNAL ;
    PORT
      LAYER met2 ;
        RECT 1913.690 0.000 1913.970 4.000 ;
    END
  END mgmt_soc_dff_Di[18]
  PIN mgmt_soc_dff_Di[19]
    DIRECTION OUTPUT TRISTATE ;
    USE SIGNAL ;
    PORT
      LAYER met2 ;
        RECT 1929.330 0.000 1929.610 4.000 ;
    END
  END mgmt_soc_dff_Di[19]
  PIN mgmt_soc_dff_Di[1]
    DIRECTION OUTPUT TRISTATE ;
    USE SIGNAL ;
    PORT
      LAYER met3 ;
        RECT 1996.000 129.240 2000.000 129.840 ;
    END
  END mgmt_soc_dff_Di[1]
  PIN mgmt_soc_dff_Di[20]
    DIRECTION OUTPUT TRISTATE ;
    USE SIGNAL ;
    PORT
      LAYER met2 ;
        RECT 1975.330 736.000 1975.610 740.000 ;
    END
  END mgmt_soc_dff_Di[20]
  PIN mgmt_soc_dff_Di[21]
    DIRECTION OUTPUT TRISTATE ;
    USE SIGNAL ;
    PORT
      LAYER met2 ;
        RECT 1978.550 736.000 1978.830 740.000 ;
    END
  END mgmt_soc_dff_Di[21]
  PIN mgmt_soc_dff_Di[22]
    DIRECTION OUTPUT TRISTATE ;
    USE SIGNAL ;
    PORT
      LAYER met2 ;
        RECT 1976.250 0.000 1976.530 4.000 ;
    END
  END mgmt_soc_dff_Di[22]
  PIN mgmt_soc_dff_Di[23]
    DIRECTION OUTPUT TRISTATE ;
    USE SIGNAL ;
    PORT
      LAYER met3 ;
        RECT 1996.000 499.160 2000.000 499.760 ;
    END
  END mgmt_soc_dff_Di[23]
  PIN mgmt_soc_dff_Di[24]
    DIRECTION OUTPUT TRISTATE ;
    USE SIGNAL ;
    PORT
      LAYER met3 ;
        RECT 1996.000 535.880 2000.000 536.480 ;
    END
  END mgmt_soc_dff_Di[24]
  PIN mgmt_soc_dff_Di[25]
    DIRECTION OUTPUT TRISTATE ;
    USE SIGNAL ;
    PORT
      LAYER met2 ;
        RECT 1984.990 736.000 1985.270 740.000 ;
    END
  END mgmt_soc_dff_Di[25]
  PIN mgmt_soc_dff_Di[26]
    DIRECTION OUTPUT TRISTATE ;
    USE SIGNAL ;
    PORT
      LAYER met3 ;
        RECT 1996.000 573.280 2000.000 573.880 ;
    END
  END mgmt_soc_dff_Di[26]
  PIN mgmt_soc_dff_Di[27]
    DIRECTION OUTPUT TRISTATE ;
    USE SIGNAL ;
    PORT
      LAYER met3 ;
        RECT 1996.000 610.000 2000.000 610.600 ;
    END
  END mgmt_soc_dff_Di[27]
  PIN mgmt_soc_dff_Di[28]
    DIRECTION OUTPUT TRISTATE ;
    USE SIGNAL ;
    PORT
      LAYER met2 ;
        RECT 1988.210 736.000 1988.490 740.000 ;
    END
  END mgmt_soc_dff_Di[28]
  PIN mgmt_soc_dff_Di[29]
    DIRECTION OUTPUT TRISTATE ;
    USE SIGNAL ;
    PORT
      LAYER met3 ;
        RECT 0.000 718.800 4.000 719.400 ;
    END
  END mgmt_soc_dff_Di[29]
  PIN mgmt_soc_dff_Di[2]
    DIRECTION OUTPUT TRISTATE ;
    USE SIGNAL ;
    PORT
      LAYER met2 ;
        RECT 1663.450 0.000 1663.730 4.000 ;
    END
  END mgmt_soc_dff_Di[2]
  PIN mgmt_soc_dff_Di[30]
    DIRECTION OUTPUT TRISTATE ;
    USE SIGNAL ;
    PORT
      LAYER met3 ;
        RECT 0.000 732.400 4.000 733.000 ;
    END
  END mgmt_soc_dff_Di[30]
  PIN mgmt_soc_dff_Di[31]
    DIRECTION OUTPUT TRISTATE ;
    USE SIGNAL ;
    PORT
      LAYER met2 ;
        RECT 1994.650 736.000 1994.930 740.000 ;
    END
  END mgmt_soc_dff_Di[31]
  PIN mgmt_soc_dff_Di[3]
    DIRECTION OUTPUT TRISTATE ;
    USE SIGNAL ;
    PORT
      LAYER met2 ;
        RECT 1949.110 736.000 1949.390 740.000 ;
    END
  END mgmt_soc_dff_Di[3]
  PIN mgmt_soc_dff_Di[4]
    DIRECTION OUTPUT TRISTATE ;
    USE SIGNAL ;
    PORT
      LAYER met2 ;
        RECT 1726.010 0.000 1726.290 4.000 ;
    END
  END mgmt_soc_dff_Di[4]
  PIN mgmt_soc_dff_Di[5]
    DIRECTION OUTPUT TRISTATE ;
    USE SIGNAL ;
    PORT
      LAYER met2 ;
        RECT 1741.650 0.000 1741.930 4.000 ;
    END
  END mgmt_soc_dff_Di[5]
  PIN mgmt_soc_dff_Di[6]
    DIRECTION OUTPUT TRISTATE ;
    USE SIGNAL ;
    PORT
      LAYER met2 ;
        RECT 1772.930 0.000 1773.210 4.000 ;
    END
  END mgmt_soc_dff_Di[6]
  PIN mgmt_soc_dff_Di[7]
    DIRECTION OUTPUT TRISTATE ;
    USE SIGNAL ;
    PORT
      LAYER met2 ;
        RECT 1955.550 736.000 1955.830 740.000 ;
    END
  END mgmt_soc_dff_Di[7]
  PIN mgmt_soc_dff_Di[8]
    DIRECTION OUTPUT TRISTATE ;
    USE SIGNAL ;
    PORT
      LAYER met3 ;
        RECT 0.000 624.280 4.000 624.880 ;
    END
  END mgmt_soc_dff_Di[8]
  PIN mgmt_soc_dff_Di[9]
    DIRECTION OUTPUT TRISTATE ;
    USE SIGNAL ;
    PORT
      LAYER met2 ;
        RECT 1804.210 0.000 1804.490 4.000 ;
    END
  END mgmt_soc_dff_Di[9]
  PIN mgmt_soc_dff_Do[0]
    DIRECTION INPUT ;
    USE SIGNAL ;
    PORT
      LAYER met3 ;
        RECT 0.000 476.720 4.000 477.320 ;
    END
  END mgmt_soc_dff_Do[0]
  PIN mgmt_soc_dff_Do[10]
    DIRECTION INPUT ;
    USE SIGNAL ;
    PORT
      LAYER met3 ;
        RECT 1996.000 276.800 2000.000 277.400 ;
    END
  END mgmt_soc_dff_Do[10]
  PIN mgmt_soc_dff_Do[11]
    DIRECTION INPUT ;
    USE SIGNAL ;
    PORT
      LAYER met3 ;
        RECT 0.000 637.880 4.000 638.480 ;
    END
  END mgmt_soc_dff_Do[11]
  PIN mgmt_soc_dff_Do[12]
    DIRECTION INPUT ;
    USE SIGNAL ;
    PORT
      LAYER met2 ;
        RECT 1835.490 0.000 1835.770 4.000 ;
    END
  END mgmt_soc_dff_Do[12]
  PIN mgmt_soc_dff_Do[13]
    DIRECTION INPUT ;
    USE SIGNAL ;
    PORT
      LAYER met3 ;
        RECT 0.000 651.480 4.000 652.080 ;
    END
  END mgmt_soc_dff_Do[13]
  PIN mgmt_soc_dff_Do[14]
    DIRECTION INPUT ;
    USE SIGNAL ;
    PORT
      LAYER met3 ;
        RECT 1996.000 388.320 2000.000 388.920 ;
    END
  END mgmt_soc_dff_Do[14]
  PIN mgmt_soc_dff_Do[15]
    DIRECTION INPUT ;
    USE SIGNAL ;
    PORT
      LAYER met3 ;
        RECT 0.000 678.680 4.000 679.280 ;
    END
  END mgmt_soc_dff_Do[15]
  PIN mgmt_soc_dff_Do[16]
    DIRECTION INPUT ;
    USE SIGNAL ;
    PORT
      LAYER met2 ;
        RECT 1882.410 0.000 1882.690 4.000 ;
    END
  END mgmt_soc_dff_Do[16]
  PIN mgmt_soc_dff_Do[17]
    DIRECTION INPUT ;
    USE SIGNAL ;
    PORT
      LAYER met2 ;
        RECT 1898.050 0.000 1898.330 4.000 ;
    END
  END mgmt_soc_dff_Do[17]
  PIN mgmt_soc_dff_Do[18]
    DIRECTION INPUT ;
    USE SIGNAL ;
    PORT
      LAYER met2 ;
        RECT 1968.890 736.000 1969.170 740.000 ;
    END
  END mgmt_soc_dff_Do[18]
  PIN mgmt_soc_dff_Do[19]
    DIRECTION INPUT ;
    USE SIGNAL ;
    PORT
      LAYER met2 ;
        RECT 1972.110 736.000 1972.390 740.000 ;
    END
  END mgmt_soc_dff_Do[19]
  PIN mgmt_soc_dff_Do[1]
    DIRECTION INPUT ;
    USE SIGNAL ;
    PORT
      LAYER met3 ;
        RECT 0.000 503.240 4.000 503.840 ;
    END
  END mgmt_soc_dff_Do[1]
  PIN mgmt_soc_dff_Do[20]
    DIRECTION INPUT ;
    USE SIGNAL ;
    PORT
      LAYER met2 ;
        RECT 1944.970 0.000 1945.250 4.000 ;
    END
  END mgmt_soc_dff_Do[20]
  PIN mgmt_soc_dff_Do[21]
    DIRECTION INPUT ;
    USE SIGNAL ;
    PORT
      LAYER met2 ;
        RECT 1960.610 0.000 1960.890 4.000 ;
    END
  END mgmt_soc_dff_Do[21]
  PIN mgmt_soc_dff_Do[22]
    DIRECTION INPUT ;
    USE SIGNAL ;
    PORT
      LAYER met3 ;
        RECT 1996.000 461.760 2000.000 462.360 ;
    END
  END mgmt_soc_dff_Do[22]
  PIN mgmt_soc_dff_Do[23]
    DIRECTION INPUT ;
    USE SIGNAL ;
    PORT
      LAYER met2 ;
        RECT 1981.770 736.000 1982.050 740.000 ;
    END
  END mgmt_soc_dff_Do[23]
  PIN mgmt_soc_dff_Do[24]
    DIRECTION INPUT ;
    USE SIGNAL ;
    PORT
      LAYER met2 ;
        RECT 1991.890 0.000 1992.170 4.000 ;
    END
  END mgmt_soc_dff_Do[24]
  PIN mgmt_soc_dff_Do[25]
    DIRECTION INPUT ;
    USE SIGNAL ;
    PORT
      LAYER met3 ;
        RECT 0.000 691.600 4.000 692.200 ;
    END
  END mgmt_soc_dff_Do[25]
  PIN mgmt_soc_dff_Do[26]
    DIRECTION INPUT ;
    USE SIGNAL ;
    PORT
      LAYER met3 ;
        RECT 0.000 705.200 4.000 705.800 ;
    END
  END mgmt_soc_dff_Do[26]
  PIN mgmt_soc_dff_Do[27]
    DIRECTION INPUT ;
    USE SIGNAL ;
    PORT
      LAYER met3 ;
        RECT 1996.000 646.720 2000.000 647.320 ;
    END
  END mgmt_soc_dff_Do[27]
  PIN mgmt_soc_dff_Do[28]
    DIRECTION INPUT ;
    USE SIGNAL ;
    PORT
      LAYER met3 ;
        RECT 1996.000 684.120 2000.000 684.720 ;
    END
  END mgmt_soc_dff_Do[28]
  PIN mgmt_soc_dff_Do[29]
    DIRECTION INPUT ;
    USE SIGNAL ;
    PORT
      LAYER met3 ;
        RECT 1996.000 720.840 2000.000 721.440 ;
    END
  END mgmt_soc_dff_Do[29]
  PIN mgmt_soc_dff_Do[2]
    DIRECTION INPUT ;
    USE SIGNAL ;
    PORT
      LAYER met2 ;
        RECT 1679.090 0.000 1679.370 4.000 ;
    END
  END mgmt_soc_dff_Do[2]
  PIN mgmt_soc_dff_Do[30]
    DIRECTION INPUT ;
    USE SIGNAL ;
    PORT
      LAYER met2 ;
        RECT 1991.430 736.000 1991.710 740.000 ;
    END
  END mgmt_soc_dff_Do[30]
  PIN mgmt_soc_dff_Do[31]
    DIRECTION INPUT ;
    USE SIGNAL ;
    PORT
      LAYER met2 ;
        RECT 1997.870 736.000 1998.150 740.000 ;
    END
  END mgmt_soc_dff_Do[31]
  PIN mgmt_soc_dff_Do[3]
    DIRECTION INPUT ;
    USE SIGNAL ;
    PORT
      LAYER met3 ;
        RECT 0.000 544.040 4.000 544.640 ;
    END
  END mgmt_soc_dff_Do[3]
  PIN mgmt_soc_dff_Do[4]
    DIRECTION INPUT ;
    USE SIGNAL ;
    PORT
      LAYER met3 ;
        RECT 1996.000 203.360 2000.000 203.960 ;
    END
  END mgmt_soc_dff_Do[4]
  PIN mgmt_soc_dff_Do[5]
    DIRECTION INPUT ;
    USE SIGNAL ;
    PORT
      LAYER met3 ;
        RECT 0.000 584.160 4.000 584.760 ;
    END
  END mgmt_soc_dff_Do[5]
  PIN mgmt_soc_dff_Do[6]
    DIRECTION INPUT ;
    USE SIGNAL ;
    PORT
      LAYER met2 ;
        RECT 1952.330 736.000 1952.610 740.000 ;
    END
  END mgmt_soc_dff_Do[6]
  PIN mgmt_soc_dff_Do[7]
    DIRECTION INPUT ;
    USE SIGNAL ;
    PORT
      LAYER met2 ;
        RECT 1788.570 0.000 1788.850 4.000 ;
    END
  END mgmt_soc_dff_Do[7]
  PIN mgmt_soc_dff_Do[8]
    DIRECTION INPUT ;
    USE SIGNAL ;
    PORT
      LAYER met2 ;
        RECT 1958.770 736.000 1959.050 740.000 ;
    END
  END mgmt_soc_dff_Do[8]
  PIN mgmt_soc_dff_Do[9]
    DIRECTION INPUT ;
    USE SIGNAL ;
    PORT
      LAYER met2 ;
        RECT 1819.850 0.000 1820.130 4.000 ;
    END
  END mgmt_soc_dff_Do[9]
  PIN mgmt_soc_dff_EN
    DIRECTION OUTPUT TRISTATE ;
    USE SIGNAL ;
    PORT
      LAYER met2 ;
        RECT 1922.890 736.000 1923.170 740.000 ;
    END
  END mgmt_soc_dff_EN
  PIN mgmt_soc_dff_WE[0]
    DIRECTION OUTPUT TRISTATE ;
    USE SIGNAL ;
    PORT
      LAYER met2 ;
        RECT 1936.230 736.000 1936.510 740.000 ;
    END
  END mgmt_soc_dff_WE[0]
  PIN mgmt_soc_dff_WE[1]
    DIRECTION OUTPUT TRISTATE ;
    USE SIGNAL ;
    PORT
      LAYER met3 ;
        RECT 0.000 516.840 4.000 517.440 ;
    END
  END mgmt_soc_dff_WE[1]
  PIN mgmt_soc_dff_WE[2]
    DIRECTION OUTPUT TRISTATE ;
    USE SIGNAL ;
    PORT
      LAYER met2 ;
        RECT 1945.890 736.000 1946.170 740.000 ;
    END
  END mgmt_soc_dff_WE[2]
  PIN mgmt_soc_dff_WE[3]
    DIRECTION OUTPUT TRISTATE ;
    USE SIGNAL ;
    PORT
      LAYER met3 ;
        RECT 1996.000 165.960 2000.000 166.560 ;
    END
  END mgmt_soc_dff_WE[3]
  PIN mprj_ack_i
    DIRECTION INPUT ;
    USE SIGNAL ;
    PORT
      LAYER met3 ;
        RECT 0.000 463.120 4.000 463.720 ;
    END
  END mprj_ack_i
  PIN mprj_adr_o[0]
    DIRECTION OUTPUT TRISTATE ;
    USE SIGNAL ;
    PORT
      LAYER met2 ;
        RECT 1684.610 736.000 1684.890 740.000 ;
    END
  END mprj_adr_o[0]
  PIN mprj_adr_o[10]
    DIRECTION OUTPUT TRISTATE ;
    USE SIGNAL ;
    PORT
      LAYER met2 ;
        RECT 1763.270 736.000 1763.550 740.000 ;
    END
  END mprj_adr_o[10]
  PIN mprj_adr_o[11]
    DIRECTION OUTPUT TRISTATE ;
    USE SIGNAL ;
    PORT
      LAYER met2 ;
        RECT 1769.710 736.000 1769.990 740.000 ;
    END
  END mprj_adr_o[11]
  PIN mprj_adr_o[12]
    DIRECTION OUTPUT TRISTATE ;
    USE SIGNAL ;
    PORT
      LAYER met2 ;
        RECT 1776.150 736.000 1776.430 740.000 ;
    END
  END mprj_adr_o[12]
  PIN mprj_adr_o[13]
    DIRECTION OUTPUT TRISTATE ;
    USE SIGNAL ;
    PORT
      LAYER met2 ;
        RECT 1782.590 736.000 1782.870 740.000 ;
    END
  END mprj_adr_o[13]
  PIN mprj_adr_o[14]
    DIRECTION OUTPUT TRISTATE ;
    USE SIGNAL ;
    PORT
      LAYER met2 ;
        RECT 1789.030 736.000 1789.310 740.000 ;
    END
  END mprj_adr_o[14]
  PIN mprj_adr_o[15]
    DIRECTION OUTPUT TRISTATE ;
    USE SIGNAL ;
    PORT
      LAYER met2 ;
        RECT 1795.930 736.000 1796.210 740.000 ;
    END
  END mprj_adr_o[15]
  PIN mprj_adr_o[16]
    DIRECTION OUTPUT TRISTATE ;
    USE SIGNAL ;
    PORT
      LAYER met2 ;
        RECT 1802.370 736.000 1802.650 740.000 ;
    END
  END mprj_adr_o[16]
  PIN mprj_adr_o[17]
    DIRECTION OUTPUT TRISTATE ;
    USE SIGNAL ;
    PORT
      LAYER met2 ;
        RECT 1808.810 736.000 1809.090 740.000 ;
    END
  END mprj_adr_o[17]
  PIN mprj_adr_o[18]
    DIRECTION OUTPUT TRISTATE ;
    USE SIGNAL ;
    PORT
      LAYER met2 ;
        RECT 1815.250 736.000 1815.530 740.000 ;
    END
  END mprj_adr_o[18]
  PIN mprj_adr_o[19]
    DIRECTION OUTPUT TRISTATE ;
    USE SIGNAL ;
    PORT
      LAYER met2 ;
        RECT 1821.690 736.000 1821.970 740.000 ;
    END
  END mprj_adr_o[19]
  PIN mprj_adr_o[1]
    DIRECTION OUTPUT TRISTATE ;
    USE SIGNAL ;
    PORT
      LAYER met2 ;
        RECT 1694.730 736.000 1695.010 740.000 ;
    END
  END mprj_adr_o[1]
  PIN mprj_adr_o[20]
    DIRECTION OUTPUT TRISTATE ;
    USE SIGNAL ;
    PORT
      LAYER met2 ;
        RECT 1828.590 736.000 1828.870 740.000 ;
    END
  END mprj_adr_o[20]
  PIN mprj_adr_o[21]
    DIRECTION OUTPUT TRISTATE ;
    USE SIGNAL ;
    PORT
      LAYER met2 ;
        RECT 1835.030 736.000 1835.310 740.000 ;
    END
  END mprj_adr_o[21]
  PIN mprj_adr_o[22]
    DIRECTION OUTPUT TRISTATE ;
    USE SIGNAL ;
    PORT
      LAYER met2 ;
        RECT 1841.470 736.000 1841.750 740.000 ;
    END
  END mprj_adr_o[22]
  PIN mprj_adr_o[23]
    DIRECTION OUTPUT TRISTATE ;
    USE SIGNAL ;
    PORT
      LAYER met2 ;
        RECT 1847.910 736.000 1848.190 740.000 ;
    END
  END mprj_adr_o[23]
  PIN mprj_adr_o[24]
    DIRECTION OUTPUT TRISTATE ;
    USE SIGNAL ;
    PORT
      LAYER met2 ;
        RECT 1854.350 736.000 1854.630 740.000 ;
    END
  END mprj_adr_o[24]
  PIN mprj_adr_o[25]
    DIRECTION OUTPUT TRISTATE ;
    USE SIGNAL ;
    PORT
      LAYER met2 ;
        RECT 1861.250 736.000 1861.530 740.000 ;
    END
  END mprj_adr_o[25]
  PIN mprj_adr_o[26]
    DIRECTION OUTPUT TRISTATE ;
    USE SIGNAL ;
    PORT
      LAYER met2 ;
        RECT 1867.690 736.000 1867.970 740.000 ;
    END
  END mprj_adr_o[26]
  PIN mprj_adr_o[27]
    DIRECTION OUTPUT TRISTATE ;
    USE SIGNAL ;
    PORT
      LAYER met2 ;
        RECT 1874.130 736.000 1874.410 740.000 ;
    END
  END mprj_adr_o[27]
  PIN mprj_adr_o[28]
    DIRECTION OUTPUT TRISTATE ;
    USE SIGNAL ;
    PORT
      LAYER met2 ;
        RECT 1880.570 736.000 1880.850 740.000 ;
    END
  END mprj_adr_o[28]
  PIN mprj_adr_o[29]
    DIRECTION OUTPUT TRISTATE ;
    USE SIGNAL ;
    PORT
      LAYER met2 ;
        RECT 1887.010 736.000 1887.290 740.000 ;
    END
  END mprj_adr_o[29]
  PIN mprj_adr_o[2]
    DIRECTION OUTPUT TRISTATE ;
    USE SIGNAL ;
    PORT
      LAYER met2 ;
        RECT 1704.390 736.000 1704.670 740.000 ;
    END
  END mprj_adr_o[2]
  PIN mprj_adr_o[30]
    DIRECTION OUTPUT TRISTATE ;
    USE SIGNAL ;
    PORT
      LAYER met2 ;
        RECT 1893.450 736.000 1893.730 740.000 ;
    END
  END mprj_adr_o[30]
  PIN mprj_adr_o[31]
    DIRECTION OUTPUT TRISTATE ;
    USE SIGNAL ;
    PORT
      LAYER met2 ;
        RECT 1900.350 736.000 1900.630 740.000 ;
    END
  END mprj_adr_o[31]
  PIN mprj_adr_o[3]
    DIRECTION OUTPUT TRISTATE ;
    USE SIGNAL ;
    PORT
      LAYER met2 ;
        RECT 1714.050 736.000 1714.330 740.000 ;
    END
  END mprj_adr_o[3]
  PIN mprj_adr_o[4]
    DIRECTION OUTPUT TRISTATE ;
    USE SIGNAL ;
    PORT
      LAYER met2 ;
        RECT 1724.170 736.000 1724.450 740.000 ;
    END
  END mprj_adr_o[4]
  PIN mprj_adr_o[5]
    DIRECTION OUTPUT TRISTATE ;
    USE SIGNAL ;
    PORT
      LAYER met2 ;
        RECT 1730.610 736.000 1730.890 740.000 ;
    END
  END mprj_adr_o[5]
  PIN mprj_adr_o[6]
    DIRECTION OUTPUT TRISTATE ;
    USE SIGNAL ;
    PORT
      LAYER met2 ;
        RECT 1737.050 736.000 1737.330 740.000 ;
    END
  END mprj_adr_o[6]
  PIN mprj_adr_o[7]
    DIRECTION OUTPUT TRISTATE ;
    USE SIGNAL ;
    PORT
      LAYER met2 ;
        RECT 1743.490 736.000 1743.770 740.000 ;
    END
  END mprj_adr_o[7]
  PIN mprj_adr_o[8]
    DIRECTION OUTPUT TRISTATE ;
    USE SIGNAL ;
    PORT
      LAYER met2 ;
        RECT 1749.930 736.000 1750.210 740.000 ;
    END
  END mprj_adr_o[8]
  PIN mprj_adr_o[9]
    DIRECTION OUTPUT TRISTATE ;
    USE SIGNAL ;
    PORT
      LAYER met2 ;
        RECT 1756.830 736.000 1757.110 740.000 ;
    END
  END mprj_adr_o[9]
  PIN mprj_cyc_o
    DIRECTION OUTPUT TRISTATE ;
    USE SIGNAL ;
    PORT
      LAYER met2 ;
        RECT 1674.950 736.000 1675.230 740.000 ;
    END
  END mprj_cyc_o
  PIN mprj_dat_i[0]
    DIRECTION INPUT ;
    USE SIGNAL ;
    PORT
      LAYER met3 ;
        RECT 0.000 32.680 4.000 33.280 ;
    END
  END mprj_dat_i[0]
  PIN mprj_dat_i[10]
    DIRECTION INPUT ;
    USE SIGNAL ;
    PORT
      LAYER met3 ;
        RECT 0.000 167.320 4.000 167.920 ;
    END
  END mprj_dat_i[10]
  PIN mprj_dat_i[11]
    DIRECTION INPUT ;
    USE SIGNAL ;
    PORT
      LAYER met3 ;
        RECT 0.000 180.920 4.000 181.520 ;
    END
  END mprj_dat_i[11]
  PIN mprj_dat_i[12]
    DIRECTION INPUT ;
    USE SIGNAL ;
    PORT
      LAYER met3 ;
        RECT 0.000 193.840 4.000 194.440 ;
    END
  END mprj_dat_i[12]
  PIN mprj_dat_i[13]
    DIRECTION INPUT ;
    USE SIGNAL ;
    PORT
      LAYER met3 ;
        RECT 0.000 207.440 4.000 208.040 ;
    END
  END mprj_dat_i[13]
  PIN mprj_dat_i[14]
    DIRECTION INPUT ;
    USE SIGNAL ;
    PORT
      LAYER met3 ;
        RECT 0.000 221.040 4.000 221.640 ;
    END
  END mprj_dat_i[14]
  PIN mprj_dat_i[15]
    DIRECTION INPUT ;
    USE SIGNAL ;
    PORT
      LAYER met3 ;
        RECT 0.000 234.640 4.000 235.240 ;
    END
  END mprj_dat_i[15]
  PIN mprj_dat_i[16]
    DIRECTION INPUT ;
    USE SIGNAL ;
    PORT
      LAYER met3 ;
        RECT 0.000 248.240 4.000 248.840 ;
    END
  END mprj_dat_i[16]
  PIN mprj_dat_i[17]
    DIRECTION INPUT ;
    USE SIGNAL ;
    PORT
      LAYER met3 ;
        RECT 0.000 261.160 4.000 261.760 ;
    END
  END mprj_dat_i[17]
  PIN mprj_dat_i[18]
    DIRECTION INPUT ;
    USE SIGNAL ;
    PORT
      LAYER met3 ;
        RECT 0.000 274.760 4.000 275.360 ;
    END
  END mprj_dat_i[18]
  PIN mprj_dat_i[19]
    DIRECTION INPUT ;
    USE SIGNAL ;
    PORT
      LAYER met3 ;
        RECT 0.000 288.360 4.000 288.960 ;
    END
  END mprj_dat_i[19]
  PIN mprj_dat_i[1]
    DIRECTION INPUT ;
    USE SIGNAL ;
    PORT
      LAYER met3 ;
        RECT 0.000 46.280 4.000 46.880 ;
    END
  END mprj_dat_i[1]
  PIN mprj_dat_i[20]
    DIRECTION INPUT ;
    USE SIGNAL ;
    PORT
      LAYER met3 ;
        RECT 0.000 301.960 4.000 302.560 ;
    END
  END mprj_dat_i[20]
  PIN mprj_dat_i[21]
    DIRECTION INPUT ;
    USE SIGNAL ;
    PORT
      LAYER met3 ;
        RECT 0.000 314.880 4.000 315.480 ;
    END
  END mprj_dat_i[21]
  PIN mprj_dat_i[22]
    DIRECTION INPUT ;
    USE SIGNAL ;
    PORT
      LAYER met3 ;
        RECT 0.000 328.480 4.000 329.080 ;
    END
  END mprj_dat_i[22]
  PIN mprj_dat_i[23]
    DIRECTION INPUT ;
    USE SIGNAL ;
    PORT
      LAYER met3 ;
        RECT 0.000 342.080 4.000 342.680 ;
    END
  END mprj_dat_i[23]
  PIN mprj_dat_i[24]
    DIRECTION INPUT ;
    USE SIGNAL ;
    PORT
      LAYER met3 ;
        RECT 0.000 355.680 4.000 356.280 ;
    END
  END mprj_dat_i[24]
  PIN mprj_dat_i[25]
    DIRECTION INPUT ;
    USE SIGNAL ;
    PORT
      LAYER met3 ;
        RECT 0.000 369.280 4.000 369.880 ;
    END
  END mprj_dat_i[25]
  PIN mprj_dat_i[26]
    DIRECTION INPUT ;
    USE SIGNAL ;
    PORT
      LAYER met3 ;
        RECT 0.000 382.200 4.000 382.800 ;
    END
  END mprj_dat_i[26]
  PIN mprj_dat_i[27]
    DIRECTION INPUT ;
    USE SIGNAL ;
    PORT
      LAYER met3 ;
        RECT 0.000 395.800 4.000 396.400 ;
    END
  END mprj_dat_i[27]
  PIN mprj_dat_i[28]
    DIRECTION INPUT ;
    USE SIGNAL ;
    PORT
      LAYER met3 ;
        RECT 0.000 409.400 4.000 410.000 ;
    END
  END mprj_dat_i[28]
  PIN mprj_dat_i[29]
    DIRECTION INPUT ;
    USE SIGNAL ;
    PORT
      LAYER met3 ;
        RECT 0.000 423.000 4.000 423.600 ;
    END
  END mprj_dat_i[29]
  PIN mprj_dat_i[2]
    DIRECTION INPUT ;
    USE SIGNAL ;
    PORT
      LAYER met3 ;
        RECT 0.000 59.880 4.000 60.480 ;
    END
  END mprj_dat_i[2]
  PIN mprj_dat_i[30]
    DIRECTION INPUT ;
    USE SIGNAL ;
    PORT
      LAYER met3 ;
        RECT 0.000 436.600 4.000 437.200 ;
    END
  END mprj_dat_i[30]
  PIN mprj_dat_i[31]
    DIRECTION INPUT ;
    USE SIGNAL ;
    PORT
      LAYER met3 ;
        RECT 0.000 449.520 4.000 450.120 ;
    END
  END mprj_dat_i[31]
  PIN mprj_dat_i[3]
    DIRECTION INPUT ;
    USE SIGNAL ;
    PORT
      LAYER met3 ;
        RECT 0.000 72.800 4.000 73.400 ;
    END
  END mprj_dat_i[3]
  PIN mprj_dat_i[4]
    DIRECTION INPUT ;
    USE SIGNAL ;
    PORT
      LAYER met3 ;
        RECT 0.000 86.400 4.000 87.000 ;
    END
  END mprj_dat_i[4]
  PIN mprj_dat_i[5]
    DIRECTION INPUT ;
    USE SIGNAL ;
    PORT
      LAYER met3 ;
        RECT 0.000 100.000 4.000 100.600 ;
    END
  END mprj_dat_i[5]
  PIN mprj_dat_i[6]
    DIRECTION INPUT ;
    USE SIGNAL ;
    PORT
      LAYER met3 ;
        RECT 0.000 113.600 4.000 114.200 ;
    END
  END mprj_dat_i[6]
  PIN mprj_dat_i[7]
    DIRECTION INPUT ;
    USE SIGNAL ;
    PORT
      LAYER met3 ;
        RECT 0.000 127.200 4.000 127.800 ;
    END
  END mprj_dat_i[7]
  PIN mprj_dat_i[8]
    DIRECTION INPUT ;
    USE SIGNAL ;
    PORT
      LAYER met3 ;
        RECT 0.000 140.120 4.000 140.720 ;
    END
  END mprj_dat_i[8]
  PIN mprj_dat_i[9]
    DIRECTION INPUT ;
    USE SIGNAL ;
    PORT
      LAYER met3 ;
        RECT 0.000 153.720 4.000 154.320 ;
    END
  END mprj_dat_i[9]
  PIN mprj_dat_o[0]
    DIRECTION OUTPUT TRISTATE ;
    USE SIGNAL ;
    PORT
      LAYER met2 ;
        RECT 1688.290 736.000 1688.570 740.000 ;
    END
  END mprj_dat_o[0]
  PIN mprj_dat_o[10]
    DIRECTION OUTPUT TRISTATE ;
    USE SIGNAL ;
    PORT
      LAYER met2 ;
        RECT 1766.490 736.000 1766.770 740.000 ;
    END
  END mprj_dat_o[10]
  PIN mprj_dat_o[11]
    DIRECTION OUTPUT TRISTATE ;
    USE SIGNAL ;
    PORT
      LAYER met2 ;
        RECT 1772.930 736.000 1773.210 740.000 ;
    END
  END mprj_dat_o[11]
  PIN mprj_dat_o[12]
    DIRECTION OUTPUT TRISTATE ;
    USE SIGNAL ;
    PORT
      LAYER met2 ;
        RECT 1779.370 736.000 1779.650 740.000 ;
    END
  END mprj_dat_o[12]
  PIN mprj_dat_o[13]
    DIRECTION OUTPUT TRISTATE ;
    USE SIGNAL ;
    PORT
      LAYER met2 ;
        RECT 1785.810 736.000 1786.090 740.000 ;
    END
  END mprj_dat_o[13]
  PIN mprj_dat_o[14]
    DIRECTION OUTPUT TRISTATE ;
    USE SIGNAL ;
    PORT
      LAYER met2 ;
        RECT 1792.710 736.000 1792.990 740.000 ;
    END
  END mprj_dat_o[14]
  PIN mprj_dat_o[15]
    DIRECTION OUTPUT TRISTATE ;
    USE SIGNAL ;
    PORT
      LAYER met2 ;
        RECT 1799.150 736.000 1799.430 740.000 ;
    END
  END mprj_dat_o[15]
  PIN mprj_dat_o[16]
    DIRECTION OUTPUT TRISTATE ;
    USE SIGNAL ;
    PORT
      LAYER met2 ;
        RECT 1805.590 736.000 1805.870 740.000 ;
    END
  END mprj_dat_o[16]
  PIN mprj_dat_o[17]
    DIRECTION OUTPUT TRISTATE ;
    USE SIGNAL ;
    PORT
      LAYER met2 ;
        RECT 1812.030 736.000 1812.310 740.000 ;
    END
  END mprj_dat_o[17]
  PIN mprj_dat_o[18]
    DIRECTION OUTPUT TRISTATE ;
    USE SIGNAL ;
    PORT
      LAYER met2 ;
        RECT 1818.470 736.000 1818.750 740.000 ;
    END
  END mprj_dat_o[18]
  PIN mprj_dat_o[19]
    DIRECTION OUTPUT TRISTATE ;
    USE SIGNAL ;
    PORT
      LAYER met2 ;
        RECT 1824.910 736.000 1825.190 740.000 ;
    END
  END mprj_dat_o[19]
  PIN mprj_dat_o[1]
    DIRECTION OUTPUT TRISTATE ;
    USE SIGNAL ;
    PORT
      LAYER met2 ;
        RECT 1697.950 736.000 1698.230 740.000 ;
    END
  END mprj_dat_o[1]
  PIN mprj_dat_o[20]
    DIRECTION OUTPUT TRISTATE ;
    USE SIGNAL ;
    PORT
      LAYER met2 ;
        RECT 1831.810 736.000 1832.090 740.000 ;
    END
  END mprj_dat_o[20]
  PIN mprj_dat_o[21]
    DIRECTION OUTPUT TRISTATE ;
    USE SIGNAL ;
    PORT
      LAYER met2 ;
        RECT 1838.250 736.000 1838.530 740.000 ;
    END
  END mprj_dat_o[21]
  PIN mprj_dat_o[22]
    DIRECTION OUTPUT TRISTATE ;
    USE SIGNAL ;
    PORT
      LAYER met2 ;
        RECT 1844.690 736.000 1844.970 740.000 ;
    END
  END mprj_dat_o[22]
  PIN mprj_dat_o[23]
    DIRECTION OUTPUT TRISTATE ;
    USE SIGNAL ;
    PORT
      LAYER met2 ;
        RECT 1851.130 736.000 1851.410 740.000 ;
    END
  END mprj_dat_o[23]
  PIN mprj_dat_o[24]
    DIRECTION OUTPUT TRISTATE ;
    USE SIGNAL ;
    PORT
      LAYER met2 ;
        RECT 1857.570 736.000 1857.850 740.000 ;
    END
  END mprj_dat_o[24]
  PIN mprj_dat_o[25]
    DIRECTION OUTPUT TRISTATE ;
    USE SIGNAL ;
    PORT
      LAYER met2 ;
        RECT 1864.470 736.000 1864.750 740.000 ;
    END
  END mprj_dat_o[25]
  PIN mprj_dat_o[26]
    DIRECTION OUTPUT TRISTATE ;
    USE SIGNAL ;
    PORT
      LAYER met2 ;
        RECT 1870.910 736.000 1871.190 740.000 ;
    END
  END mprj_dat_o[26]
  PIN mprj_dat_o[27]
    DIRECTION OUTPUT TRISTATE ;
    USE SIGNAL ;
    PORT
      LAYER met2 ;
        RECT 1877.350 736.000 1877.630 740.000 ;
    END
  END mprj_dat_o[27]
  PIN mprj_dat_o[28]
    DIRECTION OUTPUT TRISTATE ;
    USE SIGNAL ;
    PORT
      LAYER met2 ;
        RECT 1883.790 736.000 1884.070 740.000 ;
    END
  END mprj_dat_o[28]
  PIN mprj_dat_o[29]
    DIRECTION OUTPUT TRISTATE ;
    USE SIGNAL ;
    PORT
      LAYER met2 ;
        RECT 1890.230 736.000 1890.510 740.000 ;
    END
  END mprj_dat_o[29]
  PIN mprj_dat_o[2]
    DIRECTION OUTPUT TRISTATE ;
    USE SIGNAL ;
    PORT
      LAYER met2 ;
        RECT 1707.610 736.000 1707.890 740.000 ;
    END
  END mprj_dat_o[2]
  PIN mprj_dat_o[30]
    DIRECTION OUTPUT TRISTATE ;
    USE SIGNAL ;
    PORT
      LAYER met2 ;
        RECT 1897.130 736.000 1897.410 740.000 ;
    END
  END mprj_dat_o[30]
  PIN mprj_dat_o[31]
    DIRECTION OUTPUT TRISTATE ;
    USE SIGNAL ;
    PORT
      LAYER met2 ;
        RECT 1903.570 736.000 1903.850 740.000 ;
    END
  END mprj_dat_o[31]
  PIN mprj_dat_o[3]
    DIRECTION OUTPUT TRISTATE ;
    USE SIGNAL ;
    PORT
      LAYER met2 ;
        RECT 1717.270 736.000 1717.550 740.000 ;
    END
  END mprj_dat_o[3]
  PIN mprj_dat_o[4]
    DIRECTION OUTPUT TRISTATE ;
    USE SIGNAL ;
    PORT
      LAYER met2 ;
        RECT 1727.390 736.000 1727.670 740.000 ;
    END
  END mprj_dat_o[4]
  PIN mprj_dat_o[5]
    DIRECTION OUTPUT TRISTATE ;
    USE SIGNAL ;
    PORT
      LAYER met2 ;
        RECT 1733.830 736.000 1734.110 740.000 ;
    END
  END mprj_dat_o[5]
  PIN mprj_dat_o[6]
    DIRECTION OUTPUT TRISTATE ;
    USE SIGNAL ;
    PORT
      LAYER met2 ;
        RECT 1740.270 736.000 1740.550 740.000 ;
    END
  END mprj_dat_o[6]
  PIN mprj_dat_o[7]
    DIRECTION OUTPUT TRISTATE ;
    USE SIGNAL ;
    PORT
      LAYER met2 ;
        RECT 1746.710 736.000 1746.990 740.000 ;
    END
  END mprj_dat_o[7]
  PIN mprj_dat_o[8]
    DIRECTION OUTPUT TRISTATE ;
    USE SIGNAL ;
    PORT
      LAYER met2 ;
        RECT 1753.150 736.000 1753.430 740.000 ;
    END
  END mprj_dat_o[8]
  PIN mprj_dat_o[9]
    DIRECTION OUTPUT TRISTATE ;
    USE SIGNAL ;
    PORT
      LAYER met2 ;
        RECT 1760.050 736.000 1760.330 740.000 ;
    END
  END mprj_dat_o[9]
  PIN mprj_sel_o[0]
    DIRECTION OUTPUT TRISTATE ;
    USE SIGNAL ;
    PORT
      LAYER met2 ;
        RECT 1691.510 736.000 1691.790 740.000 ;
    END
  END mprj_sel_o[0]
  PIN mprj_sel_o[1]
    DIRECTION OUTPUT TRISTATE ;
    USE SIGNAL ;
    PORT
      LAYER met2 ;
        RECT 1701.170 736.000 1701.450 740.000 ;
    END
  END mprj_sel_o[1]
  PIN mprj_sel_o[2]
    DIRECTION OUTPUT TRISTATE ;
    USE SIGNAL ;
    PORT
      LAYER met2 ;
        RECT 1710.830 736.000 1711.110 740.000 ;
    END
  END mprj_sel_o[2]
  PIN mprj_sel_o[3]
    DIRECTION OUTPUT TRISTATE ;
    USE SIGNAL ;
    PORT
      LAYER met2 ;
        RECT 1720.950 736.000 1721.230 740.000 ;
    END
  END mprj_sel_o[3]
  PIN mprj_stb_o
    DIRECTION OUTPUT TRISTATE ;
    USE SIGNAL ;
    PORT
      LAYER met2 ;
        RECT 1678.170 736.000 1678.450 740.000 ;
    END
  END mprj_stb_o
  PIN mprj_wb_iena
    DIRECTION OUTPUT TRISTATE ;
    USE SIGNAL ;
    PORT
      LAYER met2 ;
        RECT 1906.790 736.000 1907.070 740.000 ;
    END
  END mprj_wb_iena
  PIN mprj_we_o
    DIRECTION OUTPUT TRISTATE ;
    USE SIGNAL ;
    PORT
      LAYER met2 ;
        RECT 1681.390 736.000 1681.670 740.000 ;
    END
  END mprj_we_o
  PIN qspi_enabled
    DIRECTION OUTPUT TRISTATE ;
    USE SIGNAL ;
    PORT
      LAYER met2 ;
        RECT 272.870 0.000 273.150 4.000 ;
    END
  END qspi_enabled
  PIN serial_rx
    DIRECTION INPUT ;
    USE SIGNAL ;
    PORT
      LAYER met3 ;
        RECT 1996.000 18.400 2000.000 19.000 ;
    END
  END serial_rx
  PIN serial_tx
    DIRECTION OUTPUT TRISTATE ;
    USE SIGNAL ;
    PORT
      LAYER met2 ;
        RECT 1926.110 736.000 1926.390 740.000 ;
    END
  END serial_tx
  PIN spi_clk
    DIRECTION OUTPUT TRISTATE ;
    USE SIGNAL ;
    PORT
      LAYER met2 ;
        RECT 1929.330 736.000 1929.610 740.000 ;
    END
  END spi_clk
  PIN spi_cs_n
    DIRECTION OUTPUT TRISTATE ;
    USE SIGNAL ;
    PORT
      LAYER met3 ;
        RECT 1996.000 55.120 2000.000 55.720 ;
    END
  END spi_cs_n
  PIN spi_enabled
    DIRECTION OUTPUT TRISTATE ;
    USE SIGNAL ;
    PORT
      LAYER met2 ;
        RECT 1507.510 0.000 1507.790 4.000 ;
    END
  END spi_enabled
  PIN spi_miso
    DIRECTION INPUT ;
    USE SIGNAL ;
    PORT
      LAYER met2 ;
        RECT 1616.530 0.000 1616.810 4.000 ;
    END
  END spi_miso
  PIN spi_mosi
    DIRECTION OUTPUT TRISTATE ;
    USE SIGNAL ;
    PORT
      LAYER met2 ;
        RECT 1933.010 736.000 1933.290 740.000 ;
    END
  END spi_mosi
  PIN spi_sdoenb
    DIRECTION OUTPUT TRISTATE ;
    USE SIGNAL ;
    PORT
      LAYER met2 ;
        RECT 1522.690 0.000 1522.970 4.000 ;
    END
  END spi_sdoenb
  PIN sram_ro_addr[0]
    DIRECTION OUTPUT TRISTATE ;
    USE SIGNAL ;
    PORT
      LAYER met2 ;
        RECT 851.090 0.000 851.370 4.000 ;
    END
  END sram_ro_addr[0]
  PIN sram_ro_addr[1]
    DIRECTION OUTPUT TRISTATE ;
    USE SIGNAL ;
    PORT
      LAYER met2 ;
        RECT 866.730 0.000 867.010 4.000 ;
    END
  END sram_ro_addr[1]
  PIN sram_ro_addr[2]
    DIRECTION OUTPUT TRISTATE ;
    USE SIGNAL ;
    PORT
      LAYER met2 ;
        RECT 882.370 0.000 882.650 4.000 ;
    END
  END sram_ro_addr[2]
  PIN sram_ro_addr[3]
    DIRECTION OUTPUT TRISTATE ;
    USE SIGNAL ;
    PORT
      LAYER met2 ;
        RECT 898.010 0.000 898.290 4.000 ;
    END
  END sram_ro_addr[3]
  PIN sram_ro_addr[4]
    DIRECTION OUTPUT TRISTATE ;
    USE SIGNAL ;
    PORT
      LAYER met2 ;
        RECT 913.650 0.000 913.930 4.000 ;
    END
  END sram_ro_addr[4]
  PIN sram_ro_addr[5]
    DIRECTION OUTPUT TRISTATE ;
    USE SIGNAL ;
    PORT
      LAYER met2 ;
        RECT 929.290 0.000 929.570 4.000 ;
    END
  END sram_ro_addr[5]
  PIN sram_ro_addr[6]
    DIRECTION OUTPUT TRISTATE ;
    USE SIGNAL ;
    PORT
      LAYER met2 ;
        RECT 944.930 0.000 945.210 4.000 ;
    END
  END sram_ro_addr[6]
  PIN sram_ro_addr[7]
    DIRECTION OUTPUT TRISTATE ;
    USE SIGNAL ;
    PORT
      LAYER met2 ;
        RECT 960.570 0.000 960.850 4.000 ;
    END
  END sram_ro_addr[7]
  PIN sram_ro_clk
    DIRECTION OUTPUT TRISTATE ;
    USE SIGNAL ;
    PORT
      LAYER met2 ;
        RECT 819.810 0.000 820.090 4.000 ;
    END
  END sram_ro_clk
  PIN sram_ro_csb
    DIRECTION OUTPUT TRISTATE ;
    USE SIGNAL ;
    PORT
      LAYER met2 ;
        RECT 835.450 0.000 835.730 4.000 ;
    END
  END sram_ro_csb
  PIN sram_ro_data[0]
    DIRECTION OUTPUT TRISTATE ;
    USE SIGNAL ;
    PORT
      LAYER met2 ;
        RECT 976.210 0.000 976.490 4.000 ;
    END
  END sram_ro_data[0]
  PIN sram_ro_data[10]
    DIRECTION OUTPUT TRISTATE ;
    USE SIGNAL ;
    PORT
      LAYER met2 ;
        RECT 1132.150 0.000 1132.430 4.000 ;
    END
  END sram_ro_data[10]
  PIN sram_ro_data[11]
    DIRECTION OUTPUT TRISTATE ;
    USE SIGNAL ;
    PORT
      LAYER met2 ;
        RECT 1147.790 0.000 1148.070 4.000 ;
    END
  END sram_ro_data[11]
  PIN sram_ro_data[12]
    DIRECTION OUTPUT TRISTATE ;
    USE SIGNAL ;
    PORT
      LAYER met2 ;
        RECT 1163.430 0.000 1163.710 4.000 ;
    END
  END sram_ro_data[12]
  PIN sram_ro_data[13]
    DIRECTION OUTPUT TRISTATE ;
    USE SIGNAL ;
    PORT
      LAYER met2 ;
        RECT 1179.070 0.000 1179.350 4.000 ;
    END
  END sram_ro_data[13]
  PIN sram_ro_data[14]
    DIRECTION OUTPUT TRISTATE ;
    USE SIGNAL ;
    PORT
      LAYER met2 ;
        RECT 1194.710 0.000 1194.990 4.000 ;
    END
  END sram_ro_data[14]
  PIN sram_ro_data[15]
    DIRECTION OUTPUT TRISTATE ;
    USE SIGNAL ;
    PORT
      LAYER met2 ;
        RECT 1210.350 0.000 1210.630 4.000 ;
    END
  END sram_ro_data[15]
  PIN sram_ro_data[16]
    DIRECTION OUTPUT TRISTATE ;
    USE SIGNAL ;
    PORT
      LAYER met2 ;
        RECT 1225.990 0.000 1226.270 4.000 ;
    END
  END sram_ro_data[16]
  PIN sram_ro_data[17]
    DIRECTION OUTPUT TRISTATE ;
    USE SIGNAL ;
    PORT
      LAYER met2 ;
        RECT 1241.630 0.000 1241.910 4.000 ;
    END
  END sram_ro_data[17]
  PIN sram_ro_data[18]
    DIRECTION OUTPUT TRISTATE ;
    USE SIGNAL ;
    PORT
      LAYER met2 ;
        RECT 1257.270 0.000 1257.550 4.000 ;
    END
  END sram_ro_data[18]
  PIN sram_ro_data[19]
    DIRECTION OUTPUT TRISTATE ;
    USE SIGNAL ;
    PORT
      LAYER met2 ;
        RECT 1272.910 0.000 1273.190 4.000 ;
    END
  END sram_ro_data[19]
  PIN sram_ro_data[1]
    DIRECTION OUTPUT TRISTATE ;
    USE SIGNAL ;
    PORT
      LAYER met2 ;
        RECT 991.850 0.000 992.130 4.000 ;
    END
  END sram_ro_data[1]
  PIN sram_ro_data[20]
    DIRECTION OUTPUT TRISTATE ;
    USE SIGNAL ;
    PORT
      LAYER met2 ;
        RECT 1288.550 0.000 1288.830 4.000 ;
    END
  END sram_ro_data[20]
  PIN sram_ro_data[21]
    DIRECTION OUTPUT TRISTATE ;
    USE SIGNAL ;
    PORT
      LAYER met2 ;
        RECT 1304.190 0.000 1304.470 4.000 ;
    END
  END sram_ro_data[21]
  PIN sram_ro_data[22]
    DIRECTION OUTPUT TRISTATE ;
    USE SIGNAL ;
    PORT
      LAYER met2 ;
        RECT 1319.830 0.000 1320.110 4.000 ;
    END
  END sram_ro_data[22]
  PIN sram_ro_data[23]
    DIRECTION OUTPUT TRISTATE ;
    USE SIGNAL ;
    PORT
      LAYER met2 ;
        RECT 1335.470 0.000 1335.750 4.000 ;
    END
  END sram_ro_data[23]
  PIN sram_ro_data[24]
    DIRECTION OUTPUT TRISTATE ;
    USE SIGNAL ;
    PORT
      LAYER met2 ;
        RECT 1351.110 0.000 1351.390 4.000 ;
    END
  END sram_ro_data[24]
  PIN sram_ro_data[25]
    DIRECTION OUTPUT TRISTATE ;
    USE SIGNAL ;
    PORT
      LAYER met2 ;
        RECT 1366.750 0.000 1367.030 4.000 ;
    END
  END sram_ro_data[25]
  PIN sram_ro_data[26]
    DIRECTION OUTPUT TRISTATE ;
    USE SIGNAL ;
    PORT
      LAYER met2 ;
        RECT 1382.390 0.000 1382.670 4.000 ;
    END
  END sram_ro_data[26]
  PIN sram_ro_data[27]
    DIRECTION OUTPUT TRISTATE ;
    USE SIGNAL ;
    PORT
      LAYER met2 ;
        RECT 1398.030 0.000 1398.310 4.000 ;
    END
  END sram_ro_data[27]
  PIN sram_ro_data[28]
    DIRECTION OUTPUT TRISTATE ;
    USE SIGNAL ;
    PORT
      LAYER met2 ;
        RECT 1413.670 0.000 1413.950 4.000 ;
    END
  END sram_ro_data[28]
  PIN sram_ro_data[29]
    DIRECTION OUTPUT TRISTATE ;
    USE SIGNAL ;
    PORT
      LAYER met2 ;
        RECT 1429.310 0.000 1429.590 4.000 ;
    END
  END sram_ro_data[29]
  PIN sram_ro_data[2]
    DIRECTION OUTPUT TRISTATE ;
    USE SIGNAL ;
    PORT
      LAYER met2 ;
        RECT 1007.490 0.000 1007.770 4.000 ;
    END
  END sram_ro_data[2]
  PIN sram_ro_data[30]
    DIRECTION OUTPUT TRISTATE ;
    USE SIGNAL ;
    PORT
      LAYER met2 ;
        RECT 1444.950 0.000 1445.230 4.000 ;
    END
  END sram_ro_data[30]
  PIN sram_ro_data[31]
    DIRECTION OUTPUT TRISTATE ;
    USE SIGNAL ;
    PORT
      LAYER met2 ;
        RECT 1460.590 0.000 1460.870 4.000 ;
    END
  END sram_ro_data[31]
  PIN sram_ro_data[3]
    DIRECTION OUTPUT TRISTATE ;
    USE SIGNAL ;
    PORT
      LAYER met2 ;
        RECT 1022.670 0.000 1022.950 4.000 ;
    END
  END sram_ro_data[3]
  PIN sram_ro_data[4]
    DIRECTION OUTPUT TRISTATE ;
    USE SIGNAL ;
    PORT
      LAYER met2 ;
        RECT 1038.310 0.000 1038.590 4.000 ;
    END
  END sram_ro_data[4]
  PIN sram_ro_data[5]
    DIRECTION OUTPUT TRISTATE ;
    USE SIGNAL ;
    PORT
      LAYER met2 ;
        RECT 1053.950 0.000 1054.230 4.000 ;
    END
  END sram_ro_data[5]
  PIN sram_ro_data[6]
    DIRECTION OUTPUT TRISTATE ;
    USE SIGNAL ;
    PORT
      LAYER met2 ;
        RECT 1069.590 0.000 1069.870 4.000 ;
    END
  END sram_ro_data[6]
  PIN sram_ro_data[7]
    DIRECTION OUTPUT TRISTATE ;
    USE SIGNAL ;
    PORT
      LAYER met2 ;
        RECT 1085.230 0.000 1085.510 4.000 ;
    END
  END sram_ro_data[7]
  PIN sram_ro_data[8]
    DIRECTION OUTPUT TRISTATE ;
    USE SIGNAL ;
    PORT
      LAYER met2 ;
        RECT 1100.870 0.000 1101.150 4.000 ;
    END
  END sram_ro_data[8]
  PIN sram_ro_data[9]
    DIRECTION OUTPUT TRISTATE ;
    USE SIGNAL ;
    PORT
      LAYER met2 ;
        RECT 1116.510 0.000 1116.790 4.000 ;
    END
  END sram_ro_data[9]
  PIN trap
    DIRECTION INPUT ;
    USE SIGNAL ;
    PORT
      LAYER met2 ;
        RECT 1538.330 0.000 1538.610 4.000 ;
    END
  END trap
  PIN uart_enabled
    DIRECTION OUTPUT TRISTATE ;
    USE SIGNAL ;
    PORT
      LAYER met2 ;
        RECT 1553.970 0.000 1554.250 4.000 ;
    END
  END uart_enabled
  PIN user_irq[0]
    DIRECTION INPUT ;
    USE SIGNAL ;
    PORT
      LAYER met3 ;
        RECT 0.000 490.320 4.000 490.920 ;
    END
  END user_irq[0]
  PIN user_irq[1]
    DIRECTION INPUT ;
    USE SIGNAL ;
    PORT
      LAYER met2 ;
        RECT 1942.670 736.000 1942.950 740.000 ;
    END
  END user_irq[1]
  PIN user_irq[2]
    DIRECTION INPUT ;
    USE SIGNAL ;
    PORT
      LAYER met2 ;
        RECT 1694.730 0.000 1695.010 4.000 ;
    END
  END user_irq[2]
  PIN user_irq[3]
    DIRECTION INPUT ;
    USE SIGNAL ;
    PORT
      LAYER met2 ;
        RECT 1710.370 0.000 1710.650 4.000 ;
    END
  END user_irq[3]
  PIN user_irq[4]
    DIRECTION INPUT ;
    USE SIGNAL ;
    PORT
      LAYER met3 ;
        RECT 0.000 570.560 4.000 571.160 ;
    END
  END user_irq[4]
  PIN user_irq[5]
    DIRECTION INPUT ;
    USE SIGNAL ;
    PORT
      LAYER met2 ;
        RECT 1757.290 0.000 1757.570 4.000 ;
    END
  END user_irq[5]
  PIN user_irq_ena[0]
    DIRECTION OUTPUT TRISTATE ;
    USE SIGNAL ;
    PORT
      LAYER met2 ;
        RECT 1910.010 736.000 1910.290 740.000 ;
    END
  END user_irq_ena[0]
  PIN user_irq_ena[1]
    DIRECTION OUTPUT TRISTATE ;
    USE SIGNAL ;
    PORT
      LAYER met2 ;
        RECT 1913.230 736.000 1913.510 740.000 ;
    END
  END user_irq_ena[1]
  PIN user_irq_ena[2]
    DIRECTION OUTPUT TRISTATE ;
    USE SIGNAL ;
    PORT
      LAYER met2 ;
        RECT 1916.450 736.000 1916.730 740.000 ;
    END
  END user_irq_ena[2]
  OBS
      LAYER li1 ;
        RECT 10.120 10.795 1989.500 729.045 ;
      LAYER met1 ;
        RECT 4.670 6.840 1998.170 735.380 ;
      LAYER met2 ;
        RECT 0.090 735.720 1.190 736.170 ;
        RECT 2.030 735.720 4.410 736.170 ;
        RECT 5.250 735.720 7.630 736.170 ;
        RECT 8.470 735.720 10.850 736.170 ;
        RECT 11.690 735.720 14.070 736.170 ;
        RECT 14.910 735.720 17.290 736.170 ;
        RECT 18.130 735.720 20.510 736.170 ;
        RECT 21.350 735.720 23.730 736.170 ;
        RECT 24.570 735.720 26.950 736.170 ;
        RECT 27.790 735.720 30.170 736.170 ;
        RECT 31.010 735.720 33.390 736.170 ;
        RECT 34.230 735.720 37.070 736.170 ;
        RECT 37.910 735.720 40.290 736.170 ;
        RECT 41.130 735.720 43.510 736.170 ;
        RECT 44.350 735.720 46.730 736.170 ;
        RECT 47.570 735.720 49.950 736.170 ;
        RECT 50.790 735.720 53.170 736.170 ;
        RECT 54.010 735.720 56.390 736.170 ;
        RECT 57.230 735.720 59.610 736.170 ;
        RECT 60.450 735.720 62.830 736.170 ;
        RECT 63.670 735.720 66.050 736.170 ;
        RECT 66.890 735.720 69.270 736.170 ;
        RECT 70.110 735.720 72.950 736.170 ;
        RECT 73.790 735.720 76.170 736.170 ;
        RECT 77.010 735.720 79.390 736.170 ;
        RECT 80.230 735.720 82.610 736.170 ;
        RECT 83.450 735.720 85.830 736.170 ;
        RECT 86.670 735.720 89.050 736.170 ;
        RECT 89.890 735.720 92.270 736.170 ;
        RECT 93.110 735.720 95.490 736.170 ;
        RECT 96.330 735.720 98.710 736.170 ;
        RECT 99.550 735.720 101.930 736.170 ;
        RECT 102.770 735.720 105.150 736.170 ;
        RECT 105.990 735.720 108.830 736.170 ;
        RECT 109.670 735.720 112.050 736.170 ;
        RECT 112.890 735.720 115.270 736.170 ;
        RECT 116.110 735.720 118.490 736.170 ;
        RECT 119.330 735.720 121.710 736.170 ;
        RECT 122.550 735.720 124.930 736.170 ;
        RECT 125.770 735.720 128.150 736.170 ;
        RECT 128.990 735.720 131.370 736.170 ;
        RECT 132.210 735.720 134.590 736.170 ;
        RECT 135.430 735.720 137.810 736.170 ;
        RECT 138.650 735.720 141.030 736.170 ;
        RECT 141.870 735.720 144.710 736.170 ;
        RECT 145.550 735.720 147.930 736.170 ;
        RECT 148.770 735.720 151.150 736.170 ;
        RECT 151.990 735.720 154.370 736.170 ;
        RECT 155.210 735.720 157.590 736.170 ;
        RECT 158.430 735.720 160.810 736.170 ;
        RECT 161.650 735.720 164.030 736.170 ;
        RECT 164.870 735.720 167.250 736.170 ;
        RECT 168.090 735.720 170.470 736.170 ;
        RECT 171.310 735.720 173.690 736.170 ;
        RECT 174.530 735.720 177.370 736.170 ;
        RECT 178.210 735.720 180.590 736.170 ;
        RECT 181.430 735.720 183.810 736.170 ;
        RECT 184.650 735.720 187.030 736.170 ;
        RECT 187.870 735.720 190.250 736.170 ;
        RECT 191.090 735.720 193.470 736.170 ;
        RECT 194.310 735.720 196.690 736.170 ;
        RECT 197.530 735.720 199.910 736.170 ;
        RECT 200.750 735.720 203.130 736.170 ;
        RECT 203.970 735.720 206.350 736.170 ;
        RECT 207.190 735.720 209.570 736.170 ;
        RECT 210.410 735.720 213.250 736.170 ;
        RECT 214.090 735.720 216.470 736.170 ;
        RECT 217.310 735.720 219.690 736.170 ;
        RECT 220.530 735.720 222.910 736.170 ;
        RECT 223.750 735.720 226.130 736.170 ;
        RECT 226.970 735.720 229.350 736.170 ;
        RECT 230.190 735.720 232.570 736.170 ;
        RECT 233.410 735.720 235.790 736.170 ;
        RECT 236.630 735.720 239.010 736.170 ;
        RECT 239.850 735.720 242.230 736.170 ;
        RECT 243.070 735.720 245.450 736.170 ;
        RECT 246.290 735.720 249.130 736.170 ;
        RECT 249.970 735.720 252.350 736.170 ;
        RECT 253.190 735.720 255.570 736.170 ;
        RECT 256.410 735.720 258.790 736.170 ;
        RECT 259.630 735.720 262.010 736.170 ;
        RECT 262.850 735.720 265.230 736.170 ;
        RECT 266.070 735.720 268.450 736.170 ;
        RECT 269.290 735.720 271.670 736.170 ;
        RECT 272.510 735.720 274.890 736.170 ;
        RECT 275.730 735.720 278.110 736.170 ;
        RECT 278.950 735.720 281.330 736.170 ;
        RECT 282.170 735.720 285.010 736.170 ;
        RECT 285.850 735.720 288.230 736.170 ;
        RECT 289.070 735.720 291.450 736.170 ;
        RECT 292.290 735.720 294.670 736.170 ;
        RECT 295.510 735.720 297.890 736.170 ;
        RECT 298.730 735.720 301.110 736.170 ;
        RECT 301.950 735.720 304.330 736.170 ;
        RECT 305.170 735.720 307.550 736.170 ;
        RECT 308.390 735.720 310.770 736.170 ;
        RECT 311.610 735.720 313.990 736.170 ;
        RECT 314.830 735.720 317.670 736.170 ;
        RECT 318.510 735.720 320.890 736.170 ;
        RECT 321.730 735.720 324.110 736.170 ;
        RECT 324.950 735.720 327.330 736.170 ;
        RECT 328.170 735.720 330.550 736.170 ;
        RECT 331.390 735.720 333.770 736.170 ;
        RECT 334.610 735.720 336.990 736.170 ;
        RECT 337.830 735.720 340.210 736.170 ;
        RECT 341.050 735.720 343.430 736.170 ;
        RECT 344.270 735.720 346.650 736.170 ;
        RECT 347.490 735.720 349.870 736.170 ;
        RECT 350.710 735.720 353.550 736.170 ;
        RECT 354.390 735.720 356.770 736.170 ;
        RECT 357.610 735.720 359.990 736.170 ;
        RECT 360.830 735.720 363.210 736.170 ;
        RECT 364.050 735.720 366.430 736.170 ;
        RECT 367.270 735.720 369.650 736.170 ;
        RECT 370.490 735.720 372.870 736.170 ;
        RECT 373.710 735.720 376.090 736.170 ;
        RECT 376.930 735.720 379.310 736.170 ;
        RECT 380.150 735.720 382.530 736.170 ;
        RECT 383.370 735.720 385.750 736.170 ;
        RECT 386.590 735.720 389.430 736.170 ;
        RECT 390.270 735.720 392.650 736.170 ;
        RECT 393.490 735.720 395.870 736.170 ;
        RECT 396.710 735.720 399.090 736.170 ;
        RECT 399.930 735.720 402.310 736.170 ;
        RECT 403.150 735.720 405.530 736.170 ;
        RECT 406.370 735.720 408.750 736.170 ;
        RECT 409.590 735.720 411.970 736.170 ;
        RECT 412.810 735.720 415.190 736.170 ;
        RECT 416.030 735.720 418.410 736.170 ;
        RECT 419.250 735.720 421.630 736.170 ;
        RECT 422.470 735.720 425.310 736.170 ;
        RECT 426.150 735.720 428.530 736.170 ;
        RECT 429.370 735.720 431.750 736.170 ;
        RECT 432.590 735.720 434.970 736.170 ;
        RECT 435.810 735.720 438.190 736.170 ;
        RECT 439.030 735.720 441.410 736.170 ;
        RECT 442.250 735.720 444.630 736.170 ;
        RECT 445.470 735.720 447.850 736.170 ;
        RECT 448.690 735.720 451.070 736.170 ;
        RECT 451.910 735.720 454.290 736.170 ;
        RECT 455.130 735.720 457.970 736.170 ;
        RECT 458.810 735.720 461.190 736.170 ;
        RECT 462.030 735.720 464.410 736.170 ;
        RECT 465.250 735.720 467.630 736.170 ;
        RECT 468.470 735.720 470.850 736.170 ;
        RECT 471.690 735.720 474.070 736.170 ;
        RECT 474.910 735.720 477.290 736.170 ;
        RECT 478.130 735.720 480.510 736.170 ;
        RECT 481.350 735.720 483.730 736.170 ;
        RECT 484.570 735.720 486.950 736.170 ;
        RECT 487.790 735.720 490.170 736.170 ;
        RECT 491.010 735.720 493.850 736.170 ;
        RECT 494.690 735.720 497.070 736.170 ;
        RECT 497.910 735.720 500.290 736.170 ;
        RECT 501.130 735.720 503.510 736.170 ;
        RECT 504.350 735.720 506.730 736.170 ;
        RECT 507.570 735.720 509.950 736.170 ;
        RECT 510.790 735.720 513.170 736.170 ;
        RECT 514.010 735.720 516.390 736.170 ;
        RECT 517.230 735.720 519.610 736.170 ;
        RECT 520.450 735.720 522.830 736.170 ;
        RECT 523.670 735.720 526.050 736.170 ;
        RECT 526.890 735.720 529.730 736.170 ;
        RECT 530.570 735.720 532.950 736.170 ;
        RECT 533.790 735.720 536.170 736.170 ;
        RECT 537.010 735.720 539.390 736.170 ;
        RECT 540.230 735.720 542.610 736.170 ;
        RECT 543.450 735.720 545.830 736.170 ;
        RECT 546.670 735.720 549.050 736.170 ;
        RECT 549.890 735.720 552.270 736.170 ;
        RECT 553.110 735.720 555.490 736.170 ;
        RECT 556.330 735.720 558.710 736.170 ;
        RECT 559.550 735.720 561.930 736.170 ;
        RECT 562.770 735.720 565.610 736.170 ;
        RECT 566.450 735.720 568.830 736.170 ;
        RECT 569.670 735.720 572.050 736.170 ;
        RECT 572.890 735.720 575.270 736.170 ;
        RECT 576.110 735.720 578.490 736.170 ;
        RECT 579.330 735.720 581.710 736.170 ;
        RECT 582.550 735.720 584.930 736.170 ;
        RECT 585.770 735.720 588.150 736.170 ;
        RECT 588.990 735.720 591.370 736.170 ;
        RECT 592.210 735.720 594.590 736.170 ;
        RECT 595.430 735.720 598.270 736.170 ;
        RECT 599.110 735.720 601.490 736.170 ;
        RECT 602.330 735.720 604.710 736.170 ;
        RECT 605.550 735.720 607.930 736.170 ;
        RECT 608.770 735.720 611.150 736.170 ;
        RECT 611.990 735.720 614.370 736.170 ;
        RECT 615.210 735.720 617.590 736.170 ;
        RECT 618.430 735.720 620.810 736.170 ;
        RECT 621.650 735.720 624.030 736.170 ;
        RECT 624.870 735.720 627.250 736.170 ;
        RECT 628.090 735.720 630.470 736.170 ;
        RECT 631.310 735.720 634.150 736.170 ;
        RECT 634.990 735.720 637.370 736.170 ;
        RECT 638.210 735.720 640.590 736.170 ;
        RECT 641.430 735.720 643.810 736.170 ;
        RECT 644.650 735.720 647.030 736.170 ;
        RECT 647.870 735.720 650.250 736.170 ;
        RECT 651.090 735.720 653.470 736.170 ;
        RECT 654.310 735.720 656.690 736.170 ;
        RECT 657.530 735.720 659.910 736.170 ;
        RECT 660.750 735.720 663.130 736.170 ;
        RECT 663.970 735.720 666.350 736.170 ;
        RECT 667.190 735.720 670.030 736.170 ;
        RECT 670.870 735.720 673.250 736.170 ;
        RECT 674.090 735.720 676.470 736.170 ;
        RECT 677.310 735.720 679.690 736.170 ;
        RECT 680.530 735.720 682.910 736.170 ;
        RECT 683.750 735.720 686.130 736.170 ;
        RECT 686.970 735.720 689.350 736.170 ;
        RECT 690.190 735.720 692.570 736.170 ;
        RECT 693.410 735.720 695.790 736.170 ;
        RECT 696.630 735.720 699.010 736.170 ;
        RECT 699.850 735.720 702.230 736.170 ;
        RECT 703.070 735.720 705.910 736.170 ;
        RECT 706.750 735.720 709.130 736.170 ;
        RECT 709.970 735.720 712.350 736.170 ;
        RECT 713.190 735.720 715.570 736.170 ;
        RECT 716.410 735.720 718.790 736.170 ;
        RECT 719.630 735.720 722.010 736.170 ;
        RECT 722.850 735.720 725.230 736.170 ;
        RECT 726.070 735.720 728.450 736.170 ;
        RECT 729.290 735.720 731.670 736.170 ;
        RECT 732.510 735.720 734.890 736.170 ;
        RECT 735.730 735.720 738.570 736.170 ;
        RECT 739.410 735.720 741.790 736.170 ;
        RECT 742.630 735.720 745.010 736.170 ;
        RECT 745.850 735.720 748.230 736.170 ;
        RECT 749.070 735.720 751.450 736.170 ;
        RECT 752.290 735.720 754.670 736.170 ;
        RECT 755.510 735.720 757.890 736.170 ;
        RECT 758.730 735.720 761.110 736.170 ;
        RECT 761.950 735.720 764.330 736.170 ;
        RECT 765.170 735.720 767.550 736.170 ;
        RECT 768.390 735.720 770.770 736.170 ;
        RECT 771.610 735.720 774.450 736.170 ;
        RECT 775.290 735.720 777.670 736.170 ;
        RECT 778.510 735.720 780.890 736.170 ;
        RECT 781.730 735.720 784.110 736.170 ;
        RECT 784.950 735.720 787.330 736.170 ;
        RECT 788.170 735.720 790.550 736.170 ;
        RECT 791.390 735.720 793.770 736.170 ;
        RECT 794.610 735.720 796.990 736.170 ;
        RECT 797.830 735.720 800.210 736.170 ;
        RECT 801.050 735.720 803.430 736.170 ;
        RECT 804.270 735.720 806.650 736.170 ;
        RECT 807.490 735.720 810.330 736.170 ;
        RECT 811.170 735.720 813.550 736.170 ;
        RECT 814.390 735.720 816.770 736.170 ;
        RECT 817.610 735.720 819.990 736.170 ;
        RECT 820.830 735.720 823.210 736.170 ;
        RECT 824.050 735.720 826.430 736.170 ;
        RECT 827.270 735.720 829.650 736.170 ;
        RECT 830.490 735.720 832.870 736.170 ;
        RECT 833.710 735.720 836.090 736.170 ;
        RECT 836.930 735.720 839.310 736.170 ;
        RECT 840.150 735.720 842.530 736.170 ;
        RECT 843.370 735.720 846.210 736.170 ;
        RECT 847.050 735.720 849.430 736.170 ;
        RECT 850.270 735.720 852.650 736.170 ;
        RECT 853.490 735.720 855.870 736.170 ;
        RECT 856.710 735.720 859.090 736.170 ;
        RECT 859.930 735.720 862.310 736.170 ;
        RECT 863.150 735.720 865.530 736.170 ;
        RECT 866.370 735.720 868.750 736.170 ;
        RECT 869.590 735.720 871.970 736.170 ;
        RECT 872.810 735.720 875.190 736.170 ;
        RECT 876.030 735.720 878.870 736.170 ;
        RECT 879.710 735.720 882.090 736.170 ;
        RECT 882.930 735.720 885.310 736.170 ;
        RECT 886.150 735.720 888.530 736.170 ;
        RECT 889.370 735.720 891.750 736.170 ;
        RECT 892.590 735.720 894.970 736.170 ;
        RECT 895.810 735.720 898.190 736.170 ;
        RECT 899.030 735.720 901.410 736.170 ;
        RECT 902.250 735.720 904.630 736.170 ;
        RECT 905.470 735.720 907.850 736.170 ;
        RECT 908.690 735.720 911.070 736.170 ;
        RECT 911.910 735.720 914.750 736.170 ;
        RECT 915.590 735.720 917.970 736.170 ;
        RECT 918.810 735.720 921.190 736.170 ;
        RECT 922.030 735.720 924.410 736.170 ;
        RECT 925.250 735.720 927.630 736.170 ;
        RECT 928.470 735.720 930.850 736.170 ;
        RECT 931.690 735.720 934.070 736.170 ;
        RECT 934.910 735.720 937.290 736.170 ;
        RECT 938.130 735.720 940.510 736.170 ;
        RECT 941.350 735.720 943.730 736.170 ;
        RECT 944.570 735.720 946.950 736.170 ;
        RECT 947.790 735.720 950.630 736.170 ;
        RECT 951.470 735.720 953.850 736.170 ;
        RECT 954.690 735.720 957.070 736.170 ;
        RECT 957.910 735.720 960.290 736.170 ;
        RECT 961.130 735.720 963.510 736.170 ;
        RECT 964.350 735.720 966.730 736.170 ;
        RECT 967.570 735.720 969.950 736.170 ;
        RECT 970.790 735.720 973.170 736.170 ;
        RECT 974.010 735.720 976.390 736.170 ;
        RECT 977.230 735.720 979.610 736.170 ;
        RECT 980.450 735.720 982.830 736.170 ;
        RECT 983.670 735.720 986.510 736.170 ;
        RECT 987.350 735.720 989.730 736.170 ;
        RECT 990.570 735.720 992.950 736.170 ;
        RECT 993.790 735.720 996.170 736.170 ;
        RECT 997.010 735.720 999.390 736.170 ;
        RECT 1000.230 735.720 1002.610 736.170 ;
        RECT 1003.450 735.720 1005.830 736.170 ;
        RECT 1006.670 735.720 1009.050 736.170 ;
        RECT 1009.890 735.720 1012.270 736.170 ;
        RECT 1013.110 735.720 1015.490 736.170 ;
        RECT 1016.330 735.720 1019.170 736.170 ;
        RECT 1020.010 735.720 1022.390 736.170 ;
        RECT 1023.230 735.720 1025.610 736.170 ;
        RECT 1026.450 735.720 1028.830 736.170 ;
        RECT 1029.670 735.720 1032.050 736.170 ;
        RECT 1032.890 735.720 1035.270 736.170 ;
        RECT 1036.110 735.720 1038.490 736.170 ;
        RECT 1039.330 735.720 1041.710 736.170 ;
        RECT 1042.550 735.720 1044.930 736.170 ;
        RECT 1045.770 735.720 1048.150 736.170 ;
        RECT 1048.990 735.720 1051.370 736.170 ;
        RECT 1052.210 735.720 1055.050 736.170 ;
        RECT 1055.890 735.720 1058.270 736.170 ;
        RECT 1059.110 735.720 1061.490 736.170 ;
        RECT 1062.330 735.720 1064.710 736.170 ;
        RECT 1065.550 735.720 1067.930 736.170 ;
        RECT 1068.770 735.720 1071.150 736.170 ;
        RECT 1071.990 735.720 1074.370 736.170 ;
        RECT 1075.210 735.720 1077.590 736.170 ;
        RECT 1078.430 735.720 1080.810 736.170 ;
        RECT 1081.650 735.720 1084.030 736.170 ;
        RECT 1084.870 735.720 1087.250 736.170 ;
        RECT 1088.090 735.720 1090.930 736.170 ;
        RECT 1091.770 735.720 1094.150 736.170 ;
        RECT 1094.990 735.720 1097.370 736.170 ;
        RECT 1098.210 735.720 1100.590 736.170 ;
        RECT 1101.430 735.720 1103.810 736.170 ;
        RECT 1104.650 735.720 1107.030 736.170 ;
        RECT 1107.870 735.720 1110.250 736.170 ;
        RECT 1111.090 735.720 1113.470 736.170 ;
        RECT 1114.310 735.720 1116.690 736.170 ;
        RECT 1117.530 735.720 1119.910 736.170 ;
        RECT 1120.750 735.720 1123.130 736.170 ;
        RECT 1123.970 735.720 1126.810 736.170 ;
        RECT 1127.650 735.720 1130.030 736.170 ;
        RECT 1130.870 735.720 1133.250 736.170 ;
        RECT 1134.090 735.720 1136.470 736.170 ;
        RECT 1137.310 735.720 1139.690 736.170 ;
        RECT 1140.530 735.720 1142.910 736.170 ;
        RECT 1143.750 735.720 1146.130 736.170 ;
        RECT 1146.970 735.720 1149.350 736.170 ;
        RECT 1150.190 735.720 1152.570 736.170 ;
        RECT 1153.410 735.720 1155.790 736.170 ;
        RECT 1156.630 735.720 1159.470 736.170 ;
        RECT 1160.310 735.720 1162.690 736.170 ;
        RECT 1163.530 735.720 1165.910 736.170 ;
        RECT 1166.750 735.720 1169.130 736.170 ;
        RECT 1169.970 735.720 1172.350 736.170 ;
        RECT 1173.190 735.720 1175.570 736.170 ;
        RECT 1176.410 735.720 1178.790 736.170 ;
        RECT 1179.630 735.720 1182.010 736.170 ;
        RECT 1182.850 735.720 1185.230 736.170 ;
        RECT 1186.070 735.720 1188.450 736.170 ;
        RECT 1189.290 735.720 1191.670 736.170 ;
        RECT 1192.510 735.720 1195.350 736.170 ;
        RECT 1196.190 735.720 1198.570 736.170 ;
        RECT 1199.410 735.720 1201.790 736.170 ;
        RECT 1202.630 735.720 1205.010 736.170 ;
        RECT 1205.850 735.720 1208.230 736.170 ;
        RECT 1209.070 735.720 1211.450 736.170 ;
        RECT 1212.290 735.720 1214.670 736.170 ;
        RECT 1215.510 735.720 1217.890 736.170 ;
        RECT 1218.730 735.720 1221.110 736.170 ;
        RECT 1221.950 735.720 1224.330 736.170 ;
        RECT 1225.170 735.720 1227.550 736.170 ;
        RECT 1228.390 735.720 1231.230 736.170 ;
        RECT 1232.070 735.720 1234.450 736.170 ;
        RECT 1235.290 735.720 1237.670 736.170 ;
        RECT 1238.510 735.720 1240.890 736.170 ;
        RECT 1241.730 735.720 1244.110 736.170 ;
        RECT 1244.950 735.720 1247.330 736.170 ;
        RECT 1248.170 735.720 1250.550 736.170 ;
        RECT 1251.390 735.720 1253.770 736.170 ;
        RECT 1254.610 735.720 1256.990 736.170 ;
        RECT 1257.830 735.720 1260.210 736.170 ;
        RECT 1261.050 735.720 1263.430 736.170 ;
        RECT 1264.270 735.720 1267.110 736.170 ;
        RECT 1267.950 735.720 1270.330 736.170 ;
        RECT 1271.170 735.720 1273.550 736.170 ;
        RECT 1274.390 735.720 1276.770 736.170 ;
        RECT 1277.610 735.720 1279.990 736.170 ;
        RECT 1280.830 735.720 1283.210 736.170 ;
        RECT 1284.050 735.720 1286.430 736.170 ;
        RECT 1287.270 735.720 1289.650 736.170 ;
        RECT 1290.490 735.720 1292.870 736.170 ;
        RECT 1293.710 735.720 1296.090 736.170 ;
        RECT 1296.930 735.720 1299.770 736.170 ;
        RECT 1300.610 735.720 1302.990 736.170 ;
        RECT 1303.830 735.720 1306.210 736.170 ;
        RECT 1307.050 735.720 1309.430 736.170 ;
        RECT 1310.270 735.720 1312.650 736.170 ;
        RECT 1313.490 735.720 1315.870 736.170 ;
        RECT 1316.710 735.720 1319.090 736.170 ;
        RECT 1319.930 735.720 1322.310 736.170 ;
        RECT 1323.150 735.720 1325.530 736.170 ;
        RECT 1326.370 735.720 1328.750 736.170 ;
        RECT 1329.590 735.720 1331.970 736.170 ;
        RECT 1332.810 735.720 1335.650 736.170 ;
        RECT 1336.490 735.720 1338.870 736.170 ;
        RECT 1339.710 735.720 1342.090 736.170 ;
        RECT 1342.930 735.720 1345.310 736.170 ;
        RECT 1346.150 735.720 1348.530 736.170 ;
        RECT 1349.370 735.720 1351.750 736.170 ;
        RECT 1352.590 735.720 1354.970 736.170 ;
        RECT 1355.810 735.720 1358.190 736.170 ;
        RECT 1359.030 735.720 1361.410 736.170 ;
        RECT 1362.250 735.720 1364.630 736.170 ;
        RECT 1365.470 735.720 1367.850 736.170 ;
        RECT 1368.690 735.720 1371.530 736.170 ;
        RECT 1372.370 735.720 1374.750 736.170 ;
        RECT 1375.590 735.720 1377.970 736.170 ;
        RECT 1378.810 735.720 1381.190 736.170 ;
        RECT 1382.030 735.720 1384.410 736.170 ;
        RECT 1385.250 735.720 1387.630 736.170 ;
        RECT 1388.470 735.720 1390.850 736.170 ;
        RECT 1391.690 735.720 1394.070 736.170 ;
        RECT 1394.910 735.720 1397.290 736.170 ;
        RECT 1398.130 735.720 1400.510 736.170 ;
        RECT 1401.350 735.720 1403.730 736.170 ;
        RECT 1404.570 735.720 1407.410 736.170 ;
        RECT 1408.250 735.720 1410.630 736.170 ;
        RECT 1411.470 735.720 1413.850 736.170 ;
        RECT 1414.690 735.720 1417.070 736.170 ;
        RECT 1417.910 735.720 1420.290 736.170 ;
        RECT 1421.130 735.720 1423.510 736.170 ;
        RECT 1424.350 735.720 1426.730 736.170 ;
        RECT 1427.570 735.720 1429.950 736.170 ;
        RECT 1430.790 735.720 1433.170 736.170 ;
        RECT 1434.010 735.720 1436.390 736.170 ;
        RECT 1437.230 735.720 1440.070 736.170 ;
        RECT 1440.910 735.720 1443.290 736.170 ;
        RECT 1444.130 735.720 1446.510 736.170 ;
        RECT 1447.350 735.720 1449.730 736.170 ;
        RECT 1450.570 735.720 1452.950 736.170 ;
        RECT 1453.790 735.720 1456.170 736.170 ;
        RECT 1457.010 735.720 1459.390 736.170 ;
        RECT 1460.230 735.720 1462.610 736.170 ;
        RECT 1463.450 735.720 1465.830 736.170 ;
        RECT 1466.670 735.720 1469.050 736.170 ;
        RECT 1469.890 735.720 1472.270 736.170 ;
        RECT 1473.110 735.720 1475.950 736.170 ;
        RECT 1476.790 735.720 1479.170 736.170 ;
        RECT 1480.010 735.720 1482.390 736.170 ;
        RECT 1483.230 735.720 1485.610 736.170 ;
        RECT 1486.450 735.720 1488.830 736.170 ;
        RECT 1489.670 735.720 1492.050 736.170 ;
        RECT 1492.890 735.720 1495.270 736.170 ;
        RECT 1496.110 735.720 1498.490 736.170 ;
        RECT 1499.330 735.720 1501.710 736.170 ;
        RECT 1502.550 735.720 1504.930 736.170 ;
        RECT 1505.770 735.720 1508.150 736.170 ;
        RECT 1508.990 735.720 1511.830 736.170 ;
        RECT 1512.670 735.720 1515.050 736.170 ;
        RECT 1515.890 735.720 1518.270 736.170 ;
        RECT 1519.110 735.720 1521.490 736.170 ;
        RECT 1522.330 735.720 1524.710 736.170 ;
        RECT 1525.550 735.720 1527.930 736.170 ;
        RECT 1528.770 735.720 1531.150 736.170 ;
        RECT 1531.990 735.720 1534.370 736.170 ;
        RECT 1535.210 735.720 1537.590 736.170 ;
        RECT 1538.430 735.720 1540.810 736.170 ;
        RECT 1541.650 735.720 1544.030 736.170 ;
        RECT 1544.870 735.720 1547.710 736.170 ;
        RECT 1548.550 735.720 1550.930 736.170 ;
        RECT 1551.770 735.720 1554.150 736.170 ;
        RECT 1554.990 735.720 1557.370 736.170 ;
        RECT 1558.210 735.720 1560.590 736.170 ;
        RECT 1561.430 735.720 1563.810 736.170 ;
        RECT 1564.650 735.720 1567.030 736.170 ;
        RECT 1567.870 735.720 1570.250 736.170 ;
        RECT 1571.090 735.720 1573.470 736.170 ;
        RECT 1574.310 735.720 1576.690 736.170 ;
        RECT 1577.530 735.720 1580.370 736.170 ;
        RECT 1581.210 735.720 1583.590 736.170 ;
        RECT 1584.430 735.720 1586.810 736.170 ;
        RECT 1587.650 735.720 1590.030 736.170 ;
        RECT 1590.870 735.720 1593.250 736.170 ;
        RECT 1594.090 735.720 1596.470 736.170 ;
        RECT 1597.310 735.720 1599.690 736.170 ;
        RECT 1600.530 735.720 1602.910 736.170 ;
        RECT 1603.750 735.720 1606.130 736.170 ;
        RECT 1606.970 735.720 1609.350 736.170 ;
        RECT 1610.190 735.720 1612.570 736.170 ;
        RECT 1613.410 735.720 1616.250 736.170 ;
        RECT 1617.090 735.720 1619.470 736.170 ;
        RECT 1620.310 735.720 1622.690 736.170 ;
        RECT 1623.530 735.720 1625.910 736.170 ;
        RECT 1626.750 735.720 1629.130 736.170 ;
        RECT 1629.970 735.720 1632.350 736.170 ;
        RECT 1633.190 735.720 1635.570 736.170 ;
        RECT 1636.410 735.720 1638.790 736.170 ;
        RECT 1639.630 735.720 1642.010 736.170 ;
        RECT 1642.850 735.720 1645.230 736.170 ;
        RECT 1646.070 735.720 1648.450 736.170 ;
        RECT 1649.290 735.720 1652.130 736.170 ;
        RECT 1652.970 735.720 1655.350 736.170 ;
        RECT 1656.190 735.720 1658.570 736.170 ;
        RECT 1659.410 735.720 1661.790 736.170 ;
        RECT 1662.630 735.720 1665.010 736.170 ;
        RECT 1665.850 735.720 1668.230 736.170 ;
        RECT 1669.070 735.720 1671.450 736.170 ;
        RECT 1672.290 735.720 1674.670 736.170 ;
        RECT 1675.510 735.720 1677.890 736.170 ;
        RECT 1678.730 735.720 1681.110 736.170 ;
        RECT 1681.950 735.720 1684.330 736.170 ;
        RECT 1685.170 735.720 1688.010 736.170 ;
        RECT 1688.850 735.720 1691.230 736.170 ;
        RECT 1692.070 735.720 1694.450 736.170 ;
        RECT 1695.290 735.720 1697.670 736.170 ;
        RECT 1698.510 735.720 1700.890 736.170 ;
        RECT 1701.730 735.720 1704.110 736.170 ;
        RECT 1704.950 735.720 1707.330 736.170 ;
        RECT 1708.170 735.720 1710.550 736.170 ;
        RECT 1711.390 735.720 1713.770 736.170 ;
        RECT 1714.610 735.720 1716.990 736.170 ;
        RECT 1717.830 735.720 1720.670 736.170 ;
        RECT 1721.510 735.720 1723.890 736.170 ;
        RECT 1724.730 735.720 1727.110 736.170 ;
        RECT 1727.950 735.720 1730.330 736.170 ;
        RECT 1731.170 735.720 1733.550 736.170 ;
        RECT 1734.390 735.720 1736.770 736.170 ;
        RECT 1737.610 735.720 1739.990 736.170 ;
        RECT 1740.830 735.720 1743.210 736.170 ;
        RECT 1744.050 735.720 1746.430 736.170 ;
        RECT 1747.270 735.720 1749.650 736.170 ;
        RECT 1750.490 735.720 1752.870 736.170 ;
        RECT 1753.710 735.720 1756.550 736.170 ;
        RECT 1757.390 735.720 1759.770 736.170 ;
        RECT 1760.610 735.720 1762.990 736.170 ;
        RECT 1763.830 735.720 1766.210 736.170 ;
        RECT 1767.050 735.720 1769.430 736.170 ;
        RECT 1770.270 735.720 1772.650 736.170 ;
        RECT 1773.490 735.720 1775.870 736.170 ;
        RECT 1776.710 735.720 1779.090 736.170 ;
        RECT 1779.930 735.720 1782.310 736.170 ;
        RECT 1783.150 735.720 1785.530 736.170 ;
        RECT 1786.370 735.720 1788.750 736.170 ;
        RECT 1789.590 735.720 1792.430 736.170 ;
        RECT 1793.270 735.720 1795.650 736.170 ;
        RECT 1796.490 735.720 1798.870 736.170 ;
        RECT 1799.710 735.720 1802.090 736.170 ;
        RECT 1802.930 735.720 1805.310 736.170 ;
        RECT 1806.150 735.720 1808.530 736.170 ;
        RECT 1809.370 735.720 1811.750 736.170 ;
        RECT 1812.590 735.720 1814.970 736.170 ;
        RECT 1815.810 735.720 1818.190 736.170 ;
        RECT 1819.030 735.720 1821.410 736.170 ;
        RECT 1822.250 735.720 1824.630 736.170 ;
        RECT 1825.470 735.720 1828.310 736.170 ;
        RECT 1829.150 735.720 1831.530 736.170 ;
        RECT 1832.370 735.720 1834.750 736.170 ;
        RECT 1835.590 735.720 1837.970 736.170 ;
        RECT 1838.810 735.720 1841.190 736.170 ;
        RECT 1842.030 735.720 1844.410 736.170 ;
        RECT 1845.250 735.720 1847.630 736.170 ;
        RECT 1848.470 735.720 1850.850 736.170 ;
        RECT 1851.690 735.720 1854.070 736.170 ;
        RECT 1854.910 735.720 1857.290 736.170 ;
        RECT 1858.130 735.720 1860.970 736.170 ;
        RECT 1861.810 735.720 1864.190 736.170 ;
        RECT 1865.030 735.720 1867.410 736.170 ;
        RECT 1868.250 735.720 1870.630 736.170 ;
        RECT 1871.470 735.720 1873.850 736.170 ;
        RECT 1874.690 735.720 1877.070 736.170 ;
        RECT 1877.910 735.720 1880.290 736.170 ;
        RECT 1881.130 735.720 1883.510 736.170 ;
        RECT 1884.350 735.720 1886.730 736.170 ;
        RECT 1887.570 735.720 1889.950 736.170 ;
        RECT 1890.790 735.720 1893.170 736.170 ;
        RECT 1894.010 735.720 1896.850 736.170 ;
        RECT 1897.690 735.720 1900.070 736.170 ;
        RECT 1900.910 735.720 1903.290 736.170 ;
        RECT 1904.130 735.720 1906.510 736.170 ;
        RECT 1907.350 735.720 1909.730 736.170 ;
        RECT 1910.570 735.720 1912.950 736.170 ;
        RECT 1913.790 735.720 1916.170 736.170 ;
        RECT 1917.010 735.720 1919.390 736.170 ;
        RECT 1920.230 735.720 1922.610 736.170 ;
        RECT 1923.450 735.720 1925.830 736.170 ;
        RECT 1926.670 735.720 1929.050 736.170 ;
        RECT 1929.890 735.720 1932.730 736.170 ;
        RECT 1933.570 735.720 1935.950 736.170 ;
        RECT 1936.790 735.720 1939.170 736.170 ;
        RECT 1940.010 735.720 1942.390 736.170 ;
        RECT 1943.230 735.720 1945.610 736.170 ;
        RECT 1946.450 735.720 1948.830 736.170 ;
        RECT 1949.670 735.720 1952.050 736.170 ;
        RECT 1952.890 735.720 1955.270 736.170 ;
        RECT 1956.110 735.720 1958.490 736.170 ;
        RECT 1959.330 735.720 1961.710 736.170 ;
        RECT 1962.550 735.720 1964.930 736.170 ;
        RECT 1965.770 735.720 1968.610 736.170 ;
        RECT 1969.450 735.720 1971.830 736.170 ;
        RECT 1972.670 735.720 1975.050 736.170 ;
        RECT 1975.890 735.720 1978.270 736.170 ;
        RECT 1979.110 735.720 1981.490 736.170 ;
        RECT 1982.330 735.720 1984.710 736.170 ;
        RECT 1985.550 735.720 1987.930 736.170 ;
        RECT 1988.770 735.720 1991.150 736.170 ;
        RECT 1991.990 735.720 1994.370 736.170 ;
        RECT 1995.210 735.720 1997.590 736.170 ;
        RECT 0.090 4.280 1998.140 735.720 ;
        RECT 0.090 3.670 7.170 4.280 ;
        RECT 8.010 3.670 22.350 4.280 ;
        RECT 23.190 3.670 37.990 4.280 ;
        RECT 38.830 3.670 53.630 4.280 ;
        RECT 54.470 3.670 69.270 4.280 ;
        RECT 70.110 3.670 84.910 4.280 ;
        RECT 85.750 3.670 100.550 4.280 ;
        RECT 101.390 3.670 116.190 4.280 ;
        RECT 117.030 3.670 131.830 4.280 ;
        RECT 132.670 3.670 147.470 4.280 ;
        RECT 148.310 3.670 163.110 4.280 ;
        RECT 163.950 3.670 178.750 4.280 ;
        RECT 179.590 3.670 194.390 4.280 ;
        RECT 195.230 3.670 210.030 4.280 ;
        RECT 210.870 3.670 225.670 4.280 ;
        RECT 226.510 3.670 241.310 4.280 ;
        RECT 242.150 3.670 256.950 4.280 ;
        RECT 257.790 3.670 272.590 4.280 ;
        RECT 273.430 3.670 288.230 4.280 ;
        RECT 289.070 3.670 303.870 4.280 ;
        RECT 304.710 3.670 319.510 4.280 ;
        RECT 320.350 3.670 335.150 4.280 ;
        RECT 335.990 3.670 350.790 4.280 ;
        RECT 351.630 3.670 366.430 4.280 ;
        RECT 367.270 3.670 382.070 4.280 ;
        RECT 382.910 3.670 397.710 4.280 ;
        RECT 398.550 3.670 413.350 4.280 ;
        RECT 414.190 3.670 428.990 4.280 ;
        RECT 429.830 3.670 444.630 4.280 ;
        RECT 445.470 3.670 460.270 4.280 ;
        RECT 461.110 3.670 475.910 4.280 ;
        RECT 476.750 3.670 491.550 4.280 ;
        RECT 492.390 3.670 507.190 4.280 ;
        RECT 508.030 3.670 522.370 4.280 ;
        RECT 523.210 3.670 538.010 4.280 ;
        RECT 538.850 3.670 553.650 4.280 ;
        RECT 554.490 3.670 569.290 4.280 ;
        RECT 570.130 3.670 584.930 4.280 ;
        RECT 585.770 3.670 600.570 4.280 ;
        RECT 601.410 3.670 616.210 4.280 ;
        RECT 617.050 3.670 631.850 4.280 ;
        RECT 632.690 3.670 647.490 4.280 ;
        RECT 648.330 3.670 663.130 4.280 ;
        RECT 663.970 3.670 678.770 4.280 ;
        RECT 679.610 3.670 694.410 4.280 ;
        RECT 695.250 3.670 710.050 4.280 ;
        RECT 710.890 3.670 725.690 4.280 ;
        RECT 726.530 3.670 741.330 4.280 ;
        RECT 742.170 3.670 756.970 4.280 ;
        RECT 757.810 3.670 772.610 4.280 ;
        RECT 773.450 3.670 788.250 4.280 ;
        RECT 789.090 3.670 803.890 4.280 ;
        RECT 804.730 3.670 819.530 4.280 ;
        RECT 820.370 3.670 835.170 4.280 ;
        RECT 836.010 3.670 850.810 4.280 ;
        RECT 851.650 3.670 866.450 4.280 ;
        RECT 867.290 3.670 882.090 4.280 ;
        RECT 882.930 3.670 897.730 4.280 ;
        RECT 898.570 3.670 913.370 4.280 ;
        RECT 914.210 3.670 929.010 4.280 ;
        RECT 929.850 3.670 944.650 4.280 ;
        RECT 945.490 3.670 960.290 4.280 ;
        RECT 961.130 3.670 975.930 4.280 ;
        RECT 976.770 3.670 991.570 4.280 ;
        RECT 992.410 3.670 1007.210 4.280 ;
        RECT 1008.050 3.670 1022.390 4.280 ;
        RECT 1023.230 3.670 1038.030 4.280 ;
        RECT 1038.870 3.670 1053.670 4.280 ;
        RECT 1054.510 3.670 1069.310 4.280 ;
        RECT 1070.150 3.670 1084.950 4.280 ;
        RECT 1085.790 3.670 1100.590 4.280 ;
        RECT 1101.430 3.670 1116.230 4.280 ;
        RECT 1117.070 3.670 1131.870 4.280 ;
        RECT 1132.710 3.670 1147.510 4.280 ;
        RECT 1148.350 3.670 1163.150 4.280 ;
        RECT 1163.990 3.670 1178.790 4.280 ;
        RECT 1179.630 3.670 1194.430 4.280 ;
        RECT 1195.270 3.670 1210.070 4.280 ;
        RECT 1210.910 3.670 1225.710 4.280 ;
        RECT 1226.550 3.670 1241.350 4.280 ;
        RECT 1242.190 3.670 1256.990 4.280 ;
        RECT 1257.830 3.670 1272.630 4.280 ;
        RECT 1273.470 3.670 1288.270 4.280 ;
        RECT 1289.110 3.670 1303.910 4.280 ;
        RECT 1304.750 3.670 1319.550 4.280 ;
        RECT 1320.390 3.670 1335.190 4.280 ;
        RECT 1336.030 3.670 1350.830 4.280 ;
        RECT 1351.670 3.670 1366.470 4.280 ;
        RECT 1367.310 3.670 1382.110 4.280 ;
        RECT 1382.950 3.670 1397.750 4.280 ;
        RECT 1398.590 3.670 1413.390 4.280 ;
        RECT 1414.230 3.670 1429.030 4.280 ;
        RECT 1429.870 3.670 1444.670 4.280 ;
        RECT 1445.510 3.670 1460.310 4.280 ;
        RECT 1461.150 3.670 1475.950 4.280 ;
        RECT 1476.790 3.670 1491.590 4.280 ;
        RECT 1492.430 3.670 1507.230 4.280 ;
        RECT 1508.070 3.670 1522.410 4.280 ;
        RECT 1523.250 3.670 1538.050 4.280 ;
        RECT 1538.890 3.670 1553.690 4.280 ;
        RECT 1554.530 3.670 1569.330 4.280 ;
        RECT 1570.170 3.670 1584.970 4.280 ;
        RECT 1585.810 3.670 1600.610 4.280 ;
        RECT 1601.450 3.670 1616.250 4.280 ;
        RECT 1617.090 3.670 1631.890 4.280 ;
        RECT 1632.730 3.670 1647.530 4.280 ;
        RECT 1648.370 3.670 1663.170 4.280 ;
        RECT 1664.010 3.670 1678.810 4.280 ;
        RECT 1679.650 3.670 1694.450 4.280 ;
        RECT 1695.290 3.670 1710.090 4.280 ;
        RECT 1710.930 3.670 1725.730 4.280 ;
        RECT 1726.570 3.670 1741.370 4.280 ;
        RECT 1742.210 3.670 1757.010 4.280 ;
        RECT 1757.850 3.670 1772.650 4.280 ;
        RECT 1773.490 3.670 1788.290 4.280 ;
        RECT 1789.130 3.670 1803.930 4.280 ;
        RECT 1804.770 3.670 1819.570 4.280 ;
        RECT 1820.410 3.670 1835.210 4.280 ;
        RECT 1836.050 3.670 1850.850 4.280 ;
        RECT 1851.690 3.670 1866.490 4.280 ;
        RECT 1867.330 3.670 1882.130 4.280 ;
        RECT 1882.970 3.670 1897.770 4.280 ;
        RECT 1898.610 3.670 1913.410 4.280 ;
        RECT 1914.250 3.670 1929.050 4.280 ;
        RECT 1929.890 3.670 1944.690 4.280 ;
        RECT 1945.530 3.670 1960.330 4.280 ;
        RECT 1961.170 3.670 1975.970 4.280 ;
        RECT 1976.810 3.670 1991.610 4.280 ;
        RECT 1992.450 3.670 1998.140 4.280 ;
      LAYER met3 ;
        RECT 4.400 732.000 1996.000 732.865 ;
        RECT 0.065 721.840 1996.000 732.000 ;
        RECT 0.065 720.440 1995.600 721.840 ;
        RECT 0.065 719.800 1996.000 720.440 ;
        RECT 4.400 718.400 1996.000 719.800 ;
        RECT 0.065 706.200 1996.000 718.400 ;
        RECT 4.400 704.800 1996.000 706.200 ;
        RECT 0.065 692.600 1996.000 704.800 ;
        RECT 4.400 691.200 1996.000 692.600 ;
        RECT 0.065 685.120 1996.000 691.200 ;
        RECT 0.065 683.720 1995.600 685.120 ;
        RECT 0.065 679.680 1996.000 683.720 ;
        RECT 4.400 678.280 1996.000 679.680 ;
        RECT 0.065 666.080 1996.000 678.280 ;
        RECT 4.400 664.680 1996.000 666.080 ;
        RECT 0.065 652.480 1996.000 664.680 ;
        RECT 4.400 651.080 1996.000 652.480 ;
        RECT 0.065 647.720 1996.000 651.080 ;
        RECT 0.065 646.320 1995.600 647.720 ;
        RECT 0.065 638.880 1996.000 646.320 ;
        RECT 4.400 637.480 1996.000 638.880 ;
        RECT 0.065 625.280 1996.000 637.480 ;
        RECT 4.400 623.880 1996.000 625.280 ;
        RECT 0.065 612.360 1996.000 623.880 ;
        RECT 4.400 611.000 1996.000 612.360 ;
        RECT 4.400 610.960 1995.600 611.000 ;
        RECT 0.065 609.600 1995.600 610.960 ;
        RECT 0.065 598.760 1996.000 609.600 ;
        RECT 4.400 597.360 1996.000 598.760 ;
        RECT 0.065 585.160 1996.000 597.360 ;
        RECT 4.400 583.760 1996.000 585.160 ;
        RECT 0.065 574.280 1996.000 583.760 ;
        RECT 0.065 572.880 1995.600 574.280 ;
        RECT 0.065 571.560 1996.000 572.880 ;
        RECT 4.400 570.160 1996.000 571.560 ;
        RECT 0.065 558.640 1996.000 570.160 ;
        RECT 4.400 557.240 1996.000 558.640 ;
        RECT 0.065 545.040 1996.000 557.240 ;
        RECT 4.400 543.640 1996.000 545.040 ;
        RECT 0.065 536.880 1996.000 543.640 ;
        RECT 0.065 535.480 1995.600 536.880 ;
        RECT 0.065 531.440 1996.000 535.480 ;
        RECT 4.400 530.040 1996.000 531.440 ;
        RECT 0.065 517.840 1996.000 530.040 ;
        RECT 4.400 516.440 1996.000 517.840 ;
        RECT 0.065 504.240 1996.000 516.440 ;
        RECT 4.400 502.840 1996.000 504.240 ;
        RECT 0.065 500.160 1996.000 502.840 ;
        RECT 0.065 498.760 1995.600 500.160 ;
        RECT 0.065 491.320 1996.000 498.760 ;
        RECT 4.400 489.920 1996.000 491.320 ;
        RECT 0.065 477.720 1996.000 489.920 ;
        RECT 4.400 476.320 1996.000 477.720 ;
        RECT 0.065 464.120 1996.000 476.320 ;
        RECT 4.400 462.760 1996.000 464.120 ;
        RECT 4.400 462.720 1995.600 462.760 ;
        RECT 0.065 461.360 1995.600 462.720 ;
        RECT 0.065 450.520 1996.000 461.360 ;
        RECT 4.400 449.120 1996.000 450.520 ;
        RECT 0.065 437.600 1996.000 449.120 ;
        RECT 4.400 436.200 1996.000 437.600 ;
        RECT 0.065 426.040 1996.000 436.200 ;
        RECT 0.065 424.640 1995.600 426.040 ;
        RECT 0.065 424.000 1996.000 424.640 ;
        RECT 4.400 422.600 1996.000 424.000 ;
        RECT 0.065 410.400 1996.000 422.600 ;
        RECT 4.400 409.000 1996.000 410.400 ;
        RECT 0.065 396.800 1996.000 409.000 ;
        RECT 4.400 395.400 1996.000 396.800 ;
        RECT 0.065 389.320 1996.000 395.400 ;
        RECT 0.065 387.920 1995.600 389.320 ;
        RECT 0.065 383.200 1996.000 387.920 ;
        RECT 4.400 381.800 1996.000 383.200 ;
        RECT 0.065 370.280 1996.000 381.800 ;
        RECT 4.400 368.880 1996.000 370.280 ;
        RECT 0.065 356.680 1996.000 368.880 ;
        RECT 4.400 355.280 1996.000 356.680 ;
        RECT 0.065 351.920 1996.000 355.280 ;
        RECT 0.065 350.520 1995.600 351.920 ;
        RECT 0.065 343.080 1996.000 350.520 ;
        RECT 4.400 341.680 1996.000 343.080 ;
        RECT 0.065 329.480 1996.000 341.680 ;
        RECT 4.400 328.080 1996.000 329.480 ;
        RECT 0.065 315.880 1996.000 328.080 ;
        RECT 4.400 315.200 1996.000 315.880 ;
        RECT 4.400 314.480 1995.600 315.200 ;
        RECT 0.065 313.800 1995.600 314.480 ;
        RECT 0.065 302.960 1996.000 313.800 ;
        RECT 4.400 301.560 1996.000 302.960 ;
        RECT 0.065 289.360 1996.000 301.560 ;
        RECT 4.400 287.960 1996.000 289.360 ;
        RECT 0.065 277.800 1996.000 287.960 ;
        RECT 0.065 276.400 1995.600 277.800 ;
        RECT 0.065 275.760 1996.000 276.400 ;
        RECT 4.400 274.360 1996.000 275.760 ;
        RECT 0.065 262.160 1996.000 274.360 ;
        RECT 4.400 260.760 1996.000 262.160 ;
        RECT 0.065 249.240 1996.000 260.760 ;
        RECT 4.400 247.840 1996.000 249.240 ;
        RECT 0.065 241.080 1996.000 247.840 ;
        RECT 0.065 239.680 1995.600 241.080 ;
        RECT 0.065 235.640 1996.000 239.680 ;
        RECT 4.400 234.240 1996.000 235.640 ;
        RECT 0.065 222.040 1996.000 234.240 ;
        RECT 4.400 220.640 1996.000 222.040 ;
        RECT 0.065 208.440 1996.000 220.640 ;
        RECT 4.400 207.040 1996.000 208.440 ;
        RECT 0.065 204.360 1996.000 207.040 ;
        RECT 0.065 202.960 1995.600 204.360 ;
        RECT 0.065 194.840 1996.000 202.960 ;
        RECT 4.400 193.440 1996.000 194.840 ;
        RECT 0.065 181.920 1996.000 193.440 ;
        RECT 4.400 180.520 1996.000 181.920 ;
        RECT 0.065 168.320 1996.000 180.520 ;
        RECT 4.400 166.960 1996.000 168.320 ;
        RECT 4.400 166.920 1995.600 166.960 ;
        RECT 0.065 165.560 1995.600 166.920 ;
        RECT 0.065 154.720 1996.000 165.560 ;
        RECT 4.400 153.320 1996.000 154.720 ;
        RECT 0.065 141.120 1996.000 153.320 ;
        RECT 4.400 139.720 1996.000 141.120 ;
        RECT 0.065 130.240 1996.000 139.720 ;
        RECT 0.065 128.840 1995.600 130.240 ;
        RECT 0.065 128.200 1996.000 128.840 ;
        RECT 4.400 126.800 1996.000 128.200 ;
        RECT 0.065 114.600 1996.000 126.800 ;
        RECT 4.400 113.200 1996.000 114.600 ;
        RECT 0.065 101.000 1996.000 113.200 ;
        RECT 4.400 99.600 1996.000 101.000 ;
        RECT 0.065 92.840 1996.000 99.600 ;
        RECT 0.065 91.440 1995.600 92.840 ;
        RECT 0.065 87.400 1996.000 91.440 ;
        RECT 4.400 86.000 1996.000 87.400 ;
        RECT 0.065 73.800 1996.000 86.000 ;
        RECT 4.400 72.400 1996.000 73.800 ;
        RECT 0.065 60.880 1996.000 72.400 ;
        RECT 4.400 59.480 1996.000 60.880 ;
        RECT 0.065 56.120 1996.000 59.480 ;
        RECT 0.065 54.720 1995.600 56.120 ;
        RECT 0.065 47.280 1996.000 54.720 ;
        RECT 4.400 45.880 1996.000 47.280 ;
        RECT 0.065 33.680 1996.000 45.880 ;
        RECT 4.400 32.280 1996.000 33.680 ;
        RECT 0.065 20.080 1996.000 32.280 ;
        RECT 4.400 19.400 1996.000 20.080 ;
        RECT 4.400 18.680 1995.600 19.400 ;
        RECT 0.065 18.000 1995.600 18.680 ;
        RECT 0.065 10.375 1996.000 18.000 ;
      LAYER met4 ;
        RECT 15.510 11.735 25.240 724.705 ;
        RECT 27.640 11.735 50.240 724.705 ;
        RECT 52.640 11.735 75.240 724.705 ;
        RECT 77.640 536.900 100.240 724.705 ;
        RECT 102.640 536.900 125.240 724.705 ;
        RECT 127.640 536.900 150.240 724.705 ;
        RECT 152.640 536.900 175.240 724.705 ;
        RECT 177.640 536.900 200.240 724.705 ;
        RECT 202.640 536.900 225.240 724.705 ;
        RECT 227.640 536.900 250.240 724.705 ;
        RECT 252.640 536.900 275.240 724.705 ;
        RECT 277.640 536.900 300.240 724.705 ;
        RECT 302.640 536.900 325.240 724.705 ;
        RECT 327.640 536.900 350.240 724.705 ;
        RECT 352.640 536.900 375.240 724.705 ;
        RECT 377.640 536.900 400.240 724.705 ;
        RECT 402.640 536.900 425.240 724.705 ;
        RECT 427.640 536.900 450.240 724.705 ;
        RECT 452.640 536.900 475.240 724.705 ;
        RECT 477.640 536.900 500.240 724.705 ;
        RECT 502.640 536.900 525.240 724.705 ;
        RECT 527.640 536.900 550.240 724.705 ;
        RECT 552.640 536.900 575.240 724.705 ;
        RECT 577.640 536.900 600.240 724.705 ;
        RECT 602.640 536.900 625.240 724.705 ;
        RECT 627.640 536.900 650.240 724.705 ;
        RECT 652.640 536.900 675.240 724.705 ;
        RECT 677.640 536.900 700.240 724.705 ;
        RECT 702.640 536.900 725.240 724.705 ;
        RECT 727.640 536.900 750.240 724.705 ;
        RECT 752.640 536.900 775.240 724.705 ;
        RECT 777.640 536.900 800.240 724.705 ;
        RECT 77.640 101.640 800.240 536.900 ;
        RECT 77.640 11.735 100.240 101.640 ;
        RECT 102.640 11.735 125.240 101.640 ;
        RECT 127.640 11.735 150.240 101.640 ;
        RECT 152.640 11.735 175.240 101.640 ;
        RECT 177.640 11.735 200.240 101.640 ;
        RECT 202.640 11.735 225.240 101.640 ;
        RECT 227.640 11.735 250.240 101.640 ;
        RECT 252.640 11.735 275.240 101.640 ;
        RECT 277.640 11.735 300.240 101.640 ;
        RECT 302.640 11.735 325.240 101.640 ;
        RECT 327.640 11.735 350.240 101.640 ;
        RECT 352.640 11.735 375.240 101.640 ;
        RECT 377.640 11.735 400.240 101.640 ;
        RECT 402.640 11.735 425.240 101.640 ;
        RECT 427.640 11.735 450.240 101.640 ;
        RECT 452.640 11.735 475.240 101.640 ;
        RECT 477.640 11.735 500.240 101.640 ;
        RECT 502.640 11.735 525.240 101.640 ;
        RECT 527.640 11.735 550.240 101.640 ;
        RECT 552.640 11.735 575.240 101.640 ;
        RECT 577.640 11.735 600.240 101.640 ;
        RECT 602.640 11.735 625.240 101.640 ;
        RECT 627.640 11.735 650.240 101.640 ;
        RECT 652.640 11.735 675.240 101.640 ;
        RECT 677.640 11.735 700.240 101.640 ;
        RECT 702.640 11.735 725.240 101.640 ;
        RECT 727.640 11.735 750.240 101.640 ;
        RECT 752.640 11.735 775.240 101.640 ;
        RECT 777.640 11.735 800.240 101.640 ;
        RECT 802.640 11.735 825.240 724.705 ;
        RECT 827.640 11.735 850.240 724.705 ;
        RECT 852.640 11.735 875.240 724.705 ;
        RECT 877.640 11.735 900.240 724.705 ;
        RECT 902.640 11.735 925.240 724.705 ;
        RECT 927.640 11.735 950.240 724.705 ;
        RECT 952.640 11.735 975.240 724.705 ;
        RECT 977.640 11.735 1000.240 724.705 ;
        RECT 1002.640 11.735 1025.240 724.705 ;
        RECT 1027.640 11.735 1050.240 724.705 ;
        RECT 1052.640 11.735 1075.240 724.705 ;
        RECT 1077.640 11.735 1100.240 724.705 ;
        RECT 1102.640 11.735 1125.240 724.705 ;
        RECT 1127.640 11.735 1150.240 724.705 ;
        RECT 1152.640 11.735 1175.240 724.705 ;
        RECT 1177.640 11.735 1200.240 724.705 ;
        RECT 1202.640 11.735 1225.240 724.705 ;
        RECT 1227.640 11.735 1250.240 724.705 ;
        RECT 1252.640 11.735 1275.240 724.705 ;
        RECT 1277.640 11.735 1300.240 724.705 ;
        RECT 1302.640 11.735 1325.240 724.705 ;
        RECT 1327.640 11.735 1350.240 724.705 ;
        RECT 1352.640 11.735 1375.240 724.705 ;
        RECT 1377.640 11.735 1400.240 724.705 ;
        RECT 1402.640 11.735 1425.240 724.705 ;
        RECT 1427.640 11.735 1450.240 724.705 ;
        RECT 1452.640 11.735 1475.240 724.705 ;
        RECT 1477.640 11.735 1500.240 724.705 ;
        RECT 1502.640 11.735 1525.240 724.705 ;
        RECT 1527.640 11.735 1550.240 724.705 ;
        RECT 1552.640 11.735 1575.240 724.705 ;
        RECT 1577.640 11.735 1600.240 724.705 ;
        RECT 1602.640 11.735 1625.240 724.705 ;
        RECT 1627.640 11.735 1650.240 724.705 ;
        RECT 1652.640 11.735 1675.240 724.705 ;
        RECT 1677.640 11.735 1700.240 724.705 ;
        RECT 1702.640 11.735 1725.240 724.705 ;
        RECT 1727.640 11.735 1750.240 724.705 ;
        RECT 1752.640 11.735 1775.240 724.705 ;
        RECT 1777.640 11.735 1800.240 724.705 ;
        RECT 1802.640 11.735 1825.240 724.705 ;
        RECT 1827.640 11.735 1850.240 724.705 ;
        RECT 1852.640 11.735 1875.240 724.705 ;
        RECT 1877.640 11.735 1900.240 724.705 ;
        RECT 1902.640 11.735 1925.240 724.705 ;
        RECT 1927.640 11.735 1950.240 724.705 ;
        RECT 1952.640 11.735 1974.945 724.705 ;
      LAYER met5 ;
        RECT 15.300 679.690 1921.300 702.900 ;
        RECT 15.300 614.690 1921.300 674.890 ;
        RECT 15.300 549.690 1921.300 609.890 ;
        RECT 15.300 484.690 1921.300 544.890 ;
        RECT 15.300 419.690 1921.300 479.890 ;
        RECT 15.300 354.690 1921.300 414.890 ;
        RECT 15.300 289.690 1921.300 349.890 ;
        RECT 15.300 224.690 1921.300 284.890 ;
        RECT 15.300 159.690 1921.300 219.890 ;
        RECT 15.300 96.100 1921.300 154.890 ;
  END
END mgmt_core
END LIBRARY

